VERSION 5.8 ;
BUSBITCHARS "[]" ;
DIVIDERCHAR "/" ;
UNITS
    DATABASE MICRONS 1000 ;
END UNITS

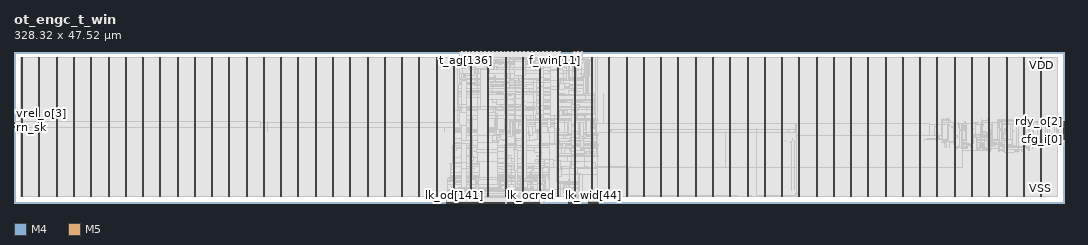
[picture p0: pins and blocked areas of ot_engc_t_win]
MACRO ot_engc_t_win
  FOREIGN ot_engc_t_win 0 0 ;
  CLASS BLOCK ;
  SIZE 328.32 BY 47.52 ;
  PIN cfg_i[0]
    DIRECTION INPUT ;
    USE SIGNAL ;
    PORT
      LAYER M4 ;
        RECT  328.236 19.92 328.32 19.944 ;
    END
  END cfg_i[0]
  PIN cfg_i[1]
    DIRECTION INPUT ;
    USE SIGNAL ;
    PORT
      LAYER M4 ;
        RECT  328.236 20.016 328.32 20.04 ;
    END
  END cfg_i[1]
  PIN cfg_i[2]
    DIRECTION INPUT ;
    USE SIGNAL ;
    PORT
      LAYER M4 ;
        RECT  328.236 20.112 328.32 20.136 ;
    END
  END cfg_i[2]
  PIN cfg_o[0]
    DIRECTION OUTPUT ;
    USE SIGNAL ;
    PORT
      LAYER M5 ;
        RECT  160.464 0 160.488 0.084 ;
    END
  END cfg_o[0]
  PIN cfg_o[1]
    DIRECTION OUTPUT ;
    USE SIGNAL ;
    PORT
      LAYER M5 ;
        RECT  160.56 0 160.584 0.084 ;
    END
  END cfg_o[1]
  PIN cfg_o[2]
    DIRECTION OUTPUT ;
    USE SIGNAL ;
    PORT
      LAYER M5 ;
        RECT  160.656 0 160.68 0.084 ;
    END
  END cfg_o[2]
  PIN ck
    DIRECTION INPUT ;
    USE SIGNAL ;
    PORT
      LAYER M5 ;
        RECT  167.856 47.436 167.88 47.52 ;
    END
  END ck
  PIN f_agc
    DIRECTION INPUT ;
    USE SIGNAL ;
    PORT
      LAYER M5 ;
        RECT  167.952 47.436 167.976 47.52 ;
    END
  END f_agc
  PIN f_win[0]
    DIRECTION INPUT ;
    USE SIGNAL ;
    PORT
      LAYER M5 ;
        RECT  168.048 47.436 168.072 47.52 ;
    END
  END f_win[0]
  PIN f_win[10]
    DIRECTION INPUT ;
    USE SIGNAL ;
    PORT
      LAYER M5 ;
        RECT  169.008 47.436 169.032 47.52 ;
    END
  END f_win[10]
  PIN f_win[11]
    DIRECTION INPUT ;
    USE SIGNAL ;
    PORT
      LAYER M5 ;
        RECT  169.104 47.436 169.128 47.52 ;
    END
  END f_win[11]
  PIN f_win[12]
    DIRECTION INPUT ;
    USE SIGNAL ;
    PORT
      LAYER M5 ;
        RECT  169.2 47.436 169.224 47.52 ;
    END
  END f_win[12]
  PIN f_win[13]
    DIRECTION INPUT ;
    USE SIGNAL ;
    PORT
      LAYER M5 ;
        RECT  169.296 47.436 169.32 47.52 ;
    END
  END f_win[13]
  PIN f_win[14]
    DIRECTION INPUT ;
    USE SIGNAL ;
    PORT
      LAYER M5 ;
        RECT  169.392 47.436 169.416 47.52 ;
    END
  END f_win[14]
  PIN f_win[15]
    DIRECTION INPUT ;
    USE SIGNAL ;
    PORT
      LAYER M5 ;
        RECT  169.488 47.436 169.512 47.52 ;
    END
  END f_win[15]
  PIN f_win[16]
    DIRECTION INPUT ;
    USE SIGNAL ;
    PORT
      LAYER M5 ;
        RECT  169.584 47.436 169.608 47.52 ;
    END
  END f_win[16]
  PIN f_win[17]
    DIRECTION INPUT ;
    USE SIGNAL ;
    PORT
      LAYER M5 ;
        RECT  169.68 47.436 169.704 47.52 ;
    END
  END f_win[17]
  PIN f_win[18]
    DIRECTION INPUT ;
    USE SIGNAL ;
    PORT
      LAYER M5 ;
        RECT  169.776 47.436 169.8 47.52 ;
    END
  END f_win[18]
  PIN f_win[19]
    DIRECTION INPUT ;
    USE SIGNAL ;
    PORT
      LAYER M5 ;
        RECT  169.872 47.436 169.896 47.52 ;
    END
  END f_win[19]
  PIN f_win[1]
    DIRECTION INPUT ;
    USE SIGNAL ;
    PORT
      LAYER M5 ;
        RECT  168.144 47.436 168.168 47.52 ;
    END
  END f_win[1]
  PIN f_win[20]
    DIRECTION INPUT ;
    USE SIGNAL ;
    PORT
      LAYER M5 ;
        RECT  169.968 47.436 169.992 47.52 ;
    END
  END f_win[20]
  PIN f_win[21]
    DIRECTION INPUT ;
    USE SIGNAL ;
    PORT
      LAYER M5 ;
        RECT  170.064 47.436 170.088 47.52 ;
    END
  END f_win[21]
  PIN f_win[22]
    DIRECTION INPUT ;
    USE SIGNAL ;
    PORT
      LAYER M5 ;
        RECT  170.16 47.436 170.184 47.52 ;
    END
  END f_win[22]
  PIN f_win[23]
    DIRECTION INPUT ;
    USE SIGNAL ;
    PORT
      LAYER M5 ;
        RECT  170.256 47.436 170.28 47.52 ;
    END
  END f_win[23]
  PIN f_win[24]
    DIRECTION INPUT ;
    USE SIGNAL ;
    PORT
      LAYER M5 ;
        RECT  170.352 47.436 170.376 47.52 ;
    END
  END f_win[24]
  PIN f_win[25]
    DIRECTION INPUT ;
    USE SIGNAL ;
    PORT
      LAYER M5 ;
        RECT  170.448 47.436 170.472 47.52 ;
    END
  END f_win[25]
  PIN f_win[26]
    DIRECTION INPUT ;
    USE SIGNAL ;
    PORT
      LAYER M5 ;
        RECT  170.544 47.436 170.568 47.52 ;
    END
  END f_win[26]
  PIN f_win[27]
    DIRECTION INPUT ;
    USE SIGNAL ;
    PORT
      LAYER M5 ;
        RECT  170.64 47.436 170.664 47.52 ;
    END
  END f_win[27]
  PIN f_win[28]
    DIRECTION INPUT ;
    USE SIGNAL ;
    PORT
      LAYER M5 ;
        RECT  170.736 47.436 170.76 47.52 ;
    END
  END f_win[28]
  PIN f_win[29]
    DIRECTION INPUT ;
    USE SIGNAL ;
    PORT
      LAYER M5 ;
        RECT  170.832 47.436 170.856 47.52 ;
    END
  END f_win[29]
  PIN f_win[2]
    DIRECTION INPUT ;
    USE SIGNAL ;
    PORT
      LAYER M5 ;
        RECT  168.24 47.436 168.264 47.52 ;
    END
  END f_win[2]
  PIN f_win[30]
    DIRECTION INPUT ;
    USE SIGNAL ;
    PORT
      LAYER M5 ;
        RECT  174.768 47.436 174.792 47.52 ;
    END
  END f_win[30]
  PIN f_win[31]
    DIRECTION INPUT ;
    USE SIGNAL ;
    PORT
      LAYER M5 ;
        RECT  174.864 47.436 174.888 47.52 ;
    END
  END f_win[31]
  PIN f_win[32]
    DIRECTION INPUT ;
    USE SIGNAL ;
    PORT
      LAYER M5 ;
        RECT  174.96 47.436 174.984 47.52 ;
    END
  END f_win[32]
  PIN f_win[33]
    DIRECTION INPUT ;
    USE SIGNAL ;
    PORT
      LAYER M5 ;
        RECT  175.056 47.436 175.08 47.52 ;
    END
  END f_win[33]
  PIN f_win[34]
    DIRECTION INPUT ;
    USE SIGNAL ;
    PORT
      LAYER M5 ;
        RECT  175.152 47.436 175.176 47.52 ;
    END
  END f_win[34]
  PIN f_win[35]
    DIRECTION INPUT ;
    USE SIGNAL ;
    PORT
      LAYER M5 ;
        RECT  175.248 47.436 175.272 47.52 ;
    END
  END f_win[35]
  PIN f_win[36]
    DIRECTION INPUT ;
    USE SIGNAL ;
    PORT
      LAYER M5 ;
        RECT  175.344 47.436 175.368 47.52 ;
    END
  END f_win[36]
  PIN f_win[37]
    DIRECTION INPUT ;
    USE SIGNAL ;
    PORT
      LAYER M5 ;
        RECT  175.44 47.436 175.464 47.52 ;
    END
  END f_win[37]
  PIN f_win[38]
    DIRECTION INPUT ;
    USE SIGNAL ;
    PORT
      LAYER M5 ;
        RECT  175.536 47.436 175.56 47.52 ;
    END
  END f_win[38]
  PIN f_win[39]
    DIRECTION INPUT ;
    USE SIGNAL ;
    PORT
      LAYER M5 ;
        RECT  175.632 47.436 175.656 47.52 ;
    END
  END f_win[39]
  PIN f_win[3]
    DIRECTION INPUT ;
    USE SIGNAL ;
    PORT
      LAYER M5 ;
        RECT  168.336 47.436 168.36 47.52 ;
    END
  END f_win[3]
  PIN f_win[40]
    DIRECTION INPUT ;
    USE SIGNAL ;
    PORT
      LAYER M5 ;
        RECT  175.728 47.436 175.752 47.52 ;
    END
  END f_win[40]
  PIN f_win[41]
    DIRECTION INPUT ;
    USE SIGNAL ;
    PORT
      LAYER M5 ;
        RECT  175.824 47.436 175.848 47.52 ;
    END
  END f_win[41]
  PIN f_win[42]
    DIRECTION INPUT ;
    USE SIGNAL ;
    PORT
      LAYER M5 ;
        RECT  175.92 47.436 175.944 47.52 ;
    END
  END f_win[42]
  PIN f_win[43]
    DIRECTION INPUT ;
    USE SIGNAL ;
    PORT
      LAYER M5 ;
        RECT  176.016 47.436 176.04 47.52 ;
    END
  END f_win[43]
  PIN f_win[44]
    DIRECTION INPUT ;
    USE SIGNAL ;
    PORT
      LAYER M5 ;
        RECT  176.112 47.436 176.136 47.52 ;
    END
  END f_win[44]
  PIN f_win[45]
    DIRECTION INPUT ;
    USE SIGNAL ;
    PORT
      LAYER M5 ;
        RECT  176.208 47.436 176.232 47.52 ;
    END
  END f_win[45]
  PIN f_win[46]
    DIRECTION INPUT ;
    USE SIGNAL ;
    PORT
      LAYER M5 ;
        RECT  176.304 47.436 176.328 47.52 ;
    END
  END f_win[46]
  PIN f_win[47]
    DIRECTION INPUT ;
    USE SIGNAL ;
    PORT
      LAYER M5 ;
        RECT  176.4 47.436 176.424 47.52 ;
    END
  END f_win[47]
  PIN f_win[48]
    DIRECTION INPUT ;
    USE SIGNAL ;
    PORT
      LAYER M5 ;
        RECT  176.496 47.436 176.52 47.52 ;
    END
  END f_win[48]
  PIN f_win[49]
    DIRECTION INPUT ;
    USE SIGNAL ;
    PORT
      LAYER M5 ;
        RECT  176.592 47.436 176.616 47.52 ;
    END
  END f_win[49]
  PIN f_win[4]
    DIRECTION INPUT ;
    USE SIGNAL ;
    PORT
      LAYER M5 ;
        RECT  168.432 47.436 168.456 47.52 ;
    END
  END f_win[4]
  PIN f_win[50]
    DIRECTION INPUT ;
    USE SIGNAL ;
    PORT
      LAYER M5 ;
        RECT  176.688 47.436 176.712 47.52 ;
    END
  END f_win[50]
  PIN f_win[51]
    DIRECTION INPUT ;
    USE SIGNAL ;
    PORT
      LAYER M5 ;
        RECT  176.784 47.436 176.808 47.52 ;
    END
  END f_win[51]
  PIN f_win[52]
    DIRECTION INPUT ;
    USE SIGNAL ;
    PORT
      LAYER M5 ;
        RECT  176.88 47.436 176.904 47.52 ;
    END
  END f_win[52]
  PIN f_win[53]
    DIRECTION INPUT ;
    USE SIGNAL ;
    PORT
      LAYER M5 ;
        RECT  176.976 47.436 177 47.52 ;
    END
  END f_win[53]
  PIN f_win[54]
    DIRECTION INPUT ;
    USE SIGNAL ;
    PORT
      LAYER M5 ;
        RECT  177.072 47.436 177.096 47.52 ;
    END
  END f_win[54]
  PIN f_win[55]
    DIRECTION INPUT ;
    USE SIGNAL ;
    PORT
      LAYER M5 ;
        RECT  177.168 47.436 177.192 47.52 ;
    END
  END f_win[55]
  PIN f_win[56]
    DIRECTION INPUT ;
    USE SIGNAL ;
    PORT
      LAYER M5 ;
        RECT  177.264 47.436 177.288 47.52 ;
    END
  END f_win[56]
  PIN f_win[57]
    DIRECTION INPUT ;
    USE SIGNAL ;
    PORT
      LAYER M5 ;
        RECT  177.36 47.436 177.384 47.52 ;
    END
  END f_win[57]
  PIN f_win[58]
    DIRECTION INPUT ;
    USE SIGNAL ;
    PORT
      LAYER M5 ;
        RECT  177.456 47.436 177.48 47.52 ;
    END
  END f_win[58]
  PIN f_win[59]
    DIRECTION INPUT ;
    USE SIGNAL ;
    PORT
      LAYER M5 ;
        RECT  177.552 47.436 177.576 47.52 ;
    END
  END f_win[59]
  PIN f_win[5]
    DIRECTION INPUT ;
    USE SIGNAL ;
    PORT
      LAYER M5 ;
        RECT  168.528 47.436 168.552 47.52 ;
    END
  END f_win[5]
  PIN f_win[60]
    DIRECTION INPUT ;
    USE SIGNAL ;
    PORT
      LAYER M5 ;
        RECT  177.648 47.436 177.672 47.52 ;
    END
  END f_win[60]
  PIN f_win[61]
    DIRECTION INPUT ;
    USE SIGNAL ;
    PORT
      LAYER M5 ;
        RECT  177.744 47.436 177.768 47.52 ;
    END
  END f_win[61]
  PIN f_win[62]
    DIRECTION INPUT ;
    USE SIGNAL ;
    PORT
      LAYER M5 ;
        RECT  164.784 47.436 164.808 47.52 ;
    END
  END f_win[62]
  PIN f_win[63]
    DIRECTION INPUT ;
    USE SIGNAL ;
    PORT
      LAYER M5 ;
        RECT  164.88 47.436 164.904 47.52 ;
    END
  END f_win[63]
  PIN f_win[64]
    DIRECTION INPUT ;
    USE SIGNAL ;
    PORT
      LAYER M5 ;
        RECT  164.976 47.436 165 47.52 ;
    END
  END f_win[64]
  PIN f_win[65]
    DIRECTION INPUT ;
    USE SIGNAL ;
    PORT
      LAYER M5 ;
        RECT  165.072 47.436 165.096 47.52 ;
    END
  END f_win[65]
  PIN f_win[66]
    DIRECTION INPUT ;
    USE SIGNAL ;
    PORT
      LAYER M5 ;
        RECT  165.168 47.436 165.192 47.52 ;
    END
  END f_win[66]
  PIN f_win[67]
    DIRECTION INPUT ;
    USE SIGNAL ;
    PORT
      LAYER M5 ;
        RECT  165.264 47.436 165.288 47.52 ;
    END
  END f_win[67]
  PIN f_win[68]
    DIRECTION INPUT ;
    USE SIGNAL ;
    PORT
      LAYER M5 ;
        RECT  165.36 47.436 165.384 47.52 ;
    END
  END f_win[68]
  PIN f_win[69]
    DIRECTION INPUT ;
    USE SIGNAL ;
    PORT
      LAYER M5 ;
        RECT  165.456 47.436 165.48 47.52 ;
    END
  END f_win[69]
  PIN f_win[6]
    DIRECTION INPUT ;
    USE SIGNAL ;
    PORT
      LAYER M5 ;
        RECT  168.624 47.436 168.648 47.52 ;
    END
  END f_win[6]
  PIN f_win[70]
    DIRECTION INPUT ;
    USE SIGNAL ;
    PORT
      LAYER M5 ;
        RECT  165.552 47.436 165.576 47.52 ;
    END
  END f_win[70]
  PIN f_win[71]
    DIRECTION INPUT ;
    USE SIGNAL ;
    PORT
      LAYER M5 ;
        RECT  165.648 47.436 165.672 47.52 ;
    END
  END f_win[71]
  PIN f_win[72]
    DIRECTION INPUT ;
    USE SIGNAL ;
    PORT
      LAYER M5 ;
        RECT  165.744 47.436 165.768 47.52 ;
    END
  END f_win[72]
  PIN f_win[7]
    DIRECTION INPUT ;
    USE SIGNAL ;
    PORT
      LAYER M5 ;
        RECT  168.72 47.436 168.744 47.52 ;
    END
  END f_win[7]
  PIN f_win[8]
    DIRECTION INPUT ;
    USE SIGNAL ;
    PORT
      LAYER M5 ;
        RECT  168.816 47.436 168.84 47.52 ;
    END
  END f_win[8]
  PIN f_win[9]
    DIRECTION INPUT ;
    USE SIGNAL ;
    PORT
      LAYER M5 ;
        RECT  168.912 47.436 168.936 47.52 ;
    END
  END f_win[9]
  PIN jf_o
    DIRECTION OUTPUT ;
    USE SIGNAL ;
    PORT
      LAYER M4 ;
        RECT  328.236 20.208 328.32 20.232 ;
    END
  END jf_o
  PIN jn_i[0]
    DIRECTION INPUT ;
    USE SIGNAL ;
    PORT
      LAYER M4 ;
        RECT  328.236 20.304 328.32 20.328 ;
    END
  END jn_i[0]
  PIN jn_i[10]
    DIRECTION INPUT ;
    USE SIGNAL ;
    PORT
      LAYER M4 ;
        RECT  328.236 21.264 328.32 21.288 ;
    END
  END jn_i[10]
  PIN jn_i[11]
    DIRECTION INPUT ;
    USE SIGNAL ;
    PORT
      LAYER M4 ;
        RECT  328.236 21.36 328.32 21.384 ;
    END
  END jn_i[11]
  PIN jn_i[12]
    DIRECTION INPUT ;
    USE SIGNAL ;
    PORT
      LAYER M4 ;
        RECT  328.236 21.456 328.32 21.48 ;
    END
  END jn_i[12]
  PIN jn_i[13]
    DIRECTION INPUT ;
    USE SIGNAL ;
    PORT
      LAYER M4 ;
        RECT  328.236 21.552 328.32 21.576 ;
    END
  END jn_i[13]
  PIN jn_i[14]
    DIRECTION INPUT ;
    USE SIGNAL ;
    PORT
      LAYER M4 ;
        RECT  328.236 21.648 328.32 21.672 ;
    END
  END jn_i[14]
  PIN jn_i[15]
    DIRECTION INPUT ;
    USE SIGNAL ;
    PORT
      LAYER M4 ;
        RECT  328.236 21.744 328.32 21.768 ;
    END
  END jn_i[15]
  PIN jn_i[16]
    DIRECTION INPUT ;
    USE SIGNAL ;
    PORT
      LAYER M4 ;
        RECT  328.236 21.84 328.32 21.864 ;
    END
  END jn_i[16]
  PIN jn_i[17]
    DIRECTION INPUT ;
    USE SIGNAL ;
    PORT
      LAYER M4 ;
        RECT  328.236 21.936 328.32 21.96 ;
    END
  END jn_i[17]
  PIN jn_i[1]
    DIRECTION INPUT ;
    USE SIGNAL ;
    PORT
      LAYER M4 ;
        RECT  328.236 20.4 328.32 20.424 ;
    END
  END jn_i[1]
  PIN jn_i[2]
    DIRECTION INPUT ;
    USE SIGNAL ;
    PORT
      LAYER M4 ;
        RECT  328.236 20.496 328.32 20.52 ;
    END
  END jn_i[2]
  PIN jn_i[3]
    DIRECTION INPUT ;
    USE SIGNAL ;
    PORT
      LAYER M4 ;
        RECT  328.236 20.592 328.32 20.616 ;
    END
  END jn_i[3]
  PIN jn_i[4]
    DIRECTION INPUT ;
    USE SIGNAL ;
    PORT
      LAYER M4 ;
        RECT  328.236 20.688 328.32 20.712 ;
    END
  END jn_i[4]
  PIN jn_i[5]
    DIRECTION INPUT ;
    USE SIGNAL ;
    PORT
      LAYER M4 ;
        RECT  328.236 20.784 328.32 20.808 ;
    END
  END jn_i[5]
  PIN jn_i[6]
    DIRECTION INPUT ;
    USE SIGNAL ;
    PORT
      LAYER M4 ;
        RECT  328.236 20.88 328.32 20.904 ;
    END
  END jn_i[6]
  PIN jn_i[7]
    DIRECTION INPUT ;
    USE SIGNAL ;
    PORT
      LAYER M4 ;
        RECT  328.236 20.976 328.32 21 ;
    END
  END jn_i[7]
  PIN jn_i[8]
    DIRECTION INPUT ;
    USE SIGNAL ;
    PORT
      LAYER M4 ;
        RECT  328.236 21.072 328.32 21.096 ;
    END
  END jn_i[8]
  PIN jn_i[9]
    DIRECTION INPUT ;
    USE SIGNAL ;
    PORT
      LAYER M4 ;
        RECT  328.236 21.168 328.32 21.192 ;
    END
  END jn_i[9]
  PIN lk_fault
    DIRECTION INPUT ;
    USE SIGNAL ;
    PORT
      LAYER M5 ;
        RECT  160.752 0 160.776 0.084 ;
    END
  END lk_fault
  PIN lk_ob[0]
    DIRECTION INPUT ;
    USE SIGNAL ;
    PORT
      LAYER M5 ;
        RECT  160.848 0 160.872 0.084 ;
    END
  END lk_ob[0]
  PIN lk_ob[1]
    DIRECTION INPUT ;
    USE SIGNAL ;
    PORT
      LAYER M5 ;
        RECT  160.944 0 160.968 0.084 ;
    END
  END lk_ob[1]
  PIN lk_ob[2]
    DIRECTION INPUT ;
    USE SIGNAL ;
    PORT
      LAYER M5 ;
        RECT  161.04 0 161.064 0.084 ;
    END
  END lk_ob[2]
  PIN lk_oc[0]
    DIRECTION INPUT ;
    USE SIGNAL ;
    PORT
      LAYER M5 ;
        RECT  161.136 0 161.16 0.084 ;
    END
  END lk_oc[0]
  PIN lk_oc[1]
    DIRECTION INPUT ;
    USE SIGNAL ;
    PORT
      LAYER M5 ;
        RECT  161.232 0 161.256 0.084 ;
    END
  END lk_oc[1]
  PIN lk_oc[2]
    DIRECTION INPUT ;
    USE SIGNAL ;
    PORT
      LAYER M5 ;
        RECT  161.328 0 161.352 0.084 ;
    END
  END lk_oc[2]
  PIN lk_oc[3]
    DIRECTION INPUT ;
    USE SIGNAL ;
    PORT
      LAYER M5 ;
        RECT  161.424 0 161.448 0.084 ;
    END
  END lk_oc[3]
  PIN lk_oc[4]
    DIRECTION INPUT ;
    USE SIGNAL ;
    PORT
      LAYER M5 ;
        RECT  161.52 0 161.544 0.084 ;
    END
  END lk_oc[4]
  PIN lk_ocred
    DIRECTION OUTPUT ;
    USE SIGNAL ;
    PORT
      LAYER M5 ;
        RECT  161.616 0 161.64 0.084 ;
    END
  END lk_ocred
  PIN lk_od[0]
    DIRECTION INPUT ;
    USE SIGNAL ;
    PORT
      LAYER M5 ;
        RECT  161.712 0 161.736 0.084 ;
    END
  END lk_od[0]
  PIN lk_od[100]
    DIRECTION INPUT ;
    USE SIGNAL ;
    PORT
      LAYER M5 ;
        RECT  139.824 0 139.848 0.084 ;
    END
  END lk_od[100]
  PIN lk_od[101]
    DIRECTION INPUT ;
    USE SIGNAL ;
    PORT
      LAYER M5 ;
        RECT  139.92 0 139.944 0.084 ;
    END
  END lk_od[101]
  PIN lk_od[102]
    DIRECTION INPUT ;
    USE SIGNAL ;
    PORT
      LAYER M5 ;
        RECT  140.016 0 140.04 0.084 ;
    END
  END lk_od[102]
  PIN lk_od[103]
    DIRECTION INPUT ;
    USE SIGNAL ;
    PORT
      LAYER M5 ;
        RECT  140.112 0 140.136 0.084 ;
    END
  END lk_od[103]
  PIN lk_od[104]
    DIRECTION INPUT ;
    USE SIGNAL ;
    PORT
      LAYER M5 ;
        RECT  140.208 0 140.232 0.084 ;
    END
  END lk_od[104]
  PIN lk_od[105]
    DIRECTION INPUT ;
    USE SIGNAL ;
    PORT
      LAYER M5 ;
        RECT  140.304 0 140.328 0.084 ;
    END
  END lk_od[105]
  PIN lk_od[106]
    DIRECTION INPUT ;
    USE SIGNAL ;
    PORT
      LAYER M5 ;
        RECT  140.4 0 140.424 0.084 ;
    END
  END lk_od[106]
  PIN lk_od[107]
    DIRECTION INPUT ;
    USE SIGNAL ;
    PORT
      LAYER M5 ;
        RECT  140.496 0 140.52 0.084 ;
    END
  END lk_od[107]
  PIN lk_od[108]
    DIRECTION INPUT ;
    USE SIGNAL ;
    PORT
      LAYER M5 ;
        RECT  140.592 0 140.616 0.084 ;
    END
  END lk_od[108]
  PIN lk_od[109]
    DIRECTION INPUT ;
    USE SIGNAL ;
    PORT
      LAYER M5 ;
        RECT  140.688 0 140.712 0.084 ;
    END
  END lk_od[109]
  PIN lk_od[10]
    DIRECTION INPUT ;
    USE SIGNAL ;
    PORT
      LAYER M5 ;
        RECT  162.672 0 162.696 0.084 ;
    END
  END lk_od[10]
  PIN lk_od[110]
    DIRECTION INPUT ;
    USE SIGNAL ;
    PORT
      LAYER M5 ;
        RECT  140.784 0 140.808 0.084 ;
    END
  END lk_od[110]
  PIN lk_od[111]
    DIRECTION INPUT ;
    USE SIGNAL ;
    PORT
      LAYER M5 ;
        RECT  140.88 0 140.904 0.084 ;
    END
  END lk_od[111]
  PIN lk_od[112]
    DIRECTION INPUT ;
    USE SIGNAL ;
    PORT
      LAYER M5 ;
        RECT  140.976 0 141 0.084 ;
    END
  END lk_od[112]
  PIN lk_od[113]
    DIRECTION INPUT ;
    USE SIGNAL ;
    PORT
      LAYER M5 ;
        RECT  141.072 0 141.096 0.084 ;
    END
  END lk_od[113]
  PIN lk_od[114]
    DIRECTION INPUT ;
    USE SIGNAL ;
    PORT
      LAYER M5 ;
        RECT  141.168 0 141.192 0.084 ;
    END
  END lk_od[114]
  PIN lk_od[115]
    DIRECTION INPUT ;
    USE SIGNAL ;
    PORT
      LAYER M5 ;
        RECT  135.12 0 135.144 0.084 ;
    END
  END lk_od[115]
  PIN lk_od[116]
    DIRECTION INPUT ;
    USE SIGNAL ;
    PORT
      LAYER M5 ;
        RECT  135.216 0 135.24 0.084 ;
    END
  END lk_od[116]
  PIN lk_od[117]
    DIRECTION INPUT ;
    USE SIGNAL ;
    PORT
      LAYER M5 ;
        RECT  135.312 0 135.336 0.084 ;
    END
  END lk_od[117]
  PIN lk_od[118]
    DIRECTION INPUT ;
    USE SIGNAL ;
    PORT
      LAYER M5 ;
        RECT  135.408 0 135.432 0.084 ;
    END
  END lk_od[118]
  PIN lk_od[119]
    DIRECTION INPUT ;
    USE SIGNAL ;
    PORT
      LAYER M5 ;
        RECT  135.504 0 135.528 0.084 ;
    END
  END lk_od[119]
  PIN lk_od[11]
    DIRECTION INPUT ;
    USE SIGNAL ;
    PORT
      LAYER M5 ;
        RECT  162.768 0 162.792 0.084 ;
    END
  END lk_od[11]
  PIN lk_od[120]
    DIRECTION INPUT ;
    USE SIGNAL ;
    PORT
      LAYER M5 ;
        RECT  135.6 0 135.624 0.084 ;
    END
  END lk_od[120]
  PIN lk_od[121]
    DIRECTION INPUT ;
    USE SIGNAL ;
    PORT
      LAYER M5 ;
        RECT  135.696 0 135.72 0.084 ;
    END
  END lk_od[121]
  PIN lk_od[122]
    DIRECTION INPUT ;
    USE SIGNAL ;
    PORT
      LAYER M5 ;
        RECT  135.792 0 135.816 0.084 ;
    END
  END lk_od[122]
  PIN lk_od[123]
    DIRECTION INPUT ;
    USE SIGNAL ;
    PORT
      LAYER M5 ;
        RECT  135.888 0 135.912 0.084 ;
    END
  END lk_od[123]
  PIN lk_od[124]
    DIRECTION INPUT ;
    USE SIGNAL ;
    PORT
      LAYER M5 ;
        RECT  135.984 0 136.008 0.084 ;
    END
  END lk_od[124]
  PIN lk_od[125]
    DIRECTION INPUT ;
    USE SIGNAL ;
    PORT
      LAYER M5 ;
        RECT  136.08 0 136.104 0.084 ;
    END
  END lk_od[125]
  PIN lk_od[126]
    DIRECTION INPUT ;
    USE SIGNAL ;
    PORT
      LAYER M5 ;
        RECT  136.176 0 136.2 0.084 ;
    END
  END lk_od[126]
  PIN lk_od[127]
    DIRECTION INPUT ;
    USE SIGNAL ;
    PORT
      LAYER M5 ;
        RECT  136.272 0 136.296 0.084 ;
    END
  END lk_od[127]
  PIN lk_od[128]
    DIRECTION INPUT ;
    USE SIGNAL ;
    PORT
      LAYER M5 ;
        RECT  136.368 0 136.392 0.084 ;
    END
  END lk_od[128]
  PIN lk_od[129]
    DIRECTION INPUT ;
    USE SIGNAL ;
    PORT
      LAYER M5 ;
        RECT  136.464 0 136.488 0.084 ;
    END
  END lk_od[129]
  PIN lk_od[12]
    DIRECTION INPUT ;
    USE SIGNAL ;
    PORT
      LAYER M5 ;
        RECT  162.864 0 162.888 0.084 ;
    END
  END lk_od[12]
  PIN lk_od[130]
    DIRECTION INPUT ;
    USE SIGNAL ;
    PORT
      LAYER M5 ;
        RECT  136.56 0 136.584 0.084 ;
    END
  END lk_od[130]
  PIN lk_od[131]
    DIRECTION INPUT ;
    USE SIGNAL ;
    PORT
      LAYER M5 ;
        RECT  136.656 0 136.68 0.084 ;
    END
  END lk_od[131]
  PIN lk_od[132]
    DIRECTION INPUT ;
    USE SIGNAL ;
    PORT
      LAYER M5 ;
        RECT  136.752 0 136.776 0.084 ;
    END
  END lk_od[132]
  PIN lk_od[133]
    DIRECTION INPUT ;
    USE SIGNAL ;
    PORT
      LAYER M5 ;
        RECT  136.848 0 136.872 0.084 ;
    END
  END lk_od[133]
  PIN lk_od[134]
    DIRECTION INPUT ;
    USE SIGNAL ;
    PORT
      LAYER M5 ;
        RECT  136.944 0 136.968 0.084 ;
    END
  END lk_od[134]
  PIN lk_od[135]
    DIRECTION INPUT ;
    USE SIGNAL ;
    PORT
      LAYER M5 ;
        RECT  137.04 0 137.064 0.084 ;
    END
  END lk_od[135]
  PIN lk_od[136]
    DIRECTION INPUT ;
    USE SIGNAL ;
    PORT
      LAYER M5 ;
        RECT  137.136 0 137.16 0.084 ;
    END
  END lk_od[136]
  PIN lk_od[137]
    DIRECTION INPUT ;
    USE SIGNAL ;
    PORT
      LAYER M5 ;
        RECT  137.232 0 137.256 0.084 ;
    END
  END lk_od[137]
  PIN lk_od[138]
    DIRECTION INPUT ;
    USE SIGNAL ;
    PORT
      LAYER M5 ;
        RECT  137.328 0 137.352 0.084 ;
    END
  END lk_od[138]
  PIN lk_od[139]
    DIRECTION INPUT ;
    USE SIGNAL ;
    PORT
      LAYER M5 ;
        RECT  137.424 0 137.448 0.084 ;
    END
  END lk_od[139]
  PIN lk_od[13]
    DIRECTION INPUT ;
    USE SIGNAL ;
    PORT
      LAYER M5 ;
        RECT  162.96 0 162.984 0.084 ;
    END
  END lk_od[13]
  PIN lk_od[140]
    DIRECTION INPUT ;
    USE SIGNAL ;
    PORT
      LAYER M5 ;
        RECT  137.52 0 137.544 0.084 ;
    END
  END lk_od[140]
  PIN lk_od[141]
    DIRECTION INPUT ;
    USE SIGNAL ;
    PORT
      LAYER M5 ;
        RECT  137.616 0 137.64 0.084 ;
    END
  END lk_od[141]
  PIN lk_od[142]
    DIRECTION INPUT ;
    USE SIGNAL ;
    PORT
      LAYER M5 ;
        RECT  137.712 0 137.736 0.084 ;
    END
  END lk_od[142]
  PIN lk_od[143]
    DIRECTION INPUT ;
    USE SIGNAL ;
    PORT
      LAYER M5 ;
        RECT  137.808 0 137.832 0.084 ;
    END
  END lk_od[143]
  PIN lk_od[144]
    DIRECTION INPUT ;
    USE SIGNAL ;
    PORT
      LAYER M5 ;
        RECT  137.904 0 137.928 0.084 ;
    END
  END lk_od[144]
  PIN lk_od[145]
    DIRECTION INPUT ;
    USE SIGNAL ;
    PORT
      LAYER M5 ;
        RECT  138 0 138.024 0.084 ;
    END
  END lk_od[145]
  PIN lk_od[146]
    DIRECTION INPUT ;
    USE SIGNAL ;
    PORT
      LAYER M5 ;
        RECT  138.096 0 138.12 0.084 ;
    END
  END lk_od[146]
  PIN lk_od[147]
    DIRECTION INPUT ;
    USE SIGNAL ;
    PORT
      LAYER M5 ;
        RECT  144.336 0 144.36 0.084 ;
    END
  END lk_od[147]
  PIN lk_od[148]
    DIRECTION INPUT ;
    USE SIGNAL ;
    PORT
      LAYER M5 ;
        RECT  144.432 0 144.456 0.084 ;
    END
  END lk_od[148]
  PIN lk_od[149]
    DIRECTION INPUT ;
    USE SIGNAL ;
    PORT
      LAYER M5 ;
        RECT  144.528 0 144.552 0.084 ;
    END
  END lk_od[149]
  PIN lk_od[14]
    DIRECTION INPUT ;
    USE SIGNAL ;
    PORT
      LAYER M5 ;
        RECT  163.056 0 163.08 0.084 ;
    END
  END lk_od[14]
  PIN lk_od[150]
    DIRECTION INPUT ;
    USE SIGNAL ;
    PORT
      LAYER M5 ;
        RECT  144.624 0 144.648 0.084 ;
    END
  END lk_od[150]
  PIN lk_od[151]
    DIRECTION INPUT ;
    USE SIGNAL ;
    PORT
      LAYER M5 ;
        RECT  144.72 0 144.744 0.084 ;
    END
  END lk_od[151]
  PIN lk_od[152]
    DIRECTION INPUT ;
    USE SIGNAL ;
    PORT
      LAYER M5 ;
        RECT  144.816 0 144.84 0.084 ;
    END
  END lk_od[152]
  PIN lk_od[153]
    DIRECTION INPUT ;
    USE SIGNAL ;
    PORT
      LAYER M5 ;
        RECT  144.912 0 144.936 0.084 ;
    END
  END lk_od[153]
  PIN lk_od[154]
    DIRECTION INPUT ;
    USE SIGNAL ;
    PORT
      LAYER M5 ;
        RECT  145.008 0 145.032 0.084 ;
    END
  END lk_od[154]
  PIN lk_od[155]
    DIRECTION INPUT ;
    USE SIGNAL ;
    PORT
      LAYER M5 ;
        RECT  145.104 0 145.128 0.084 ;
    END
  END lk_od[155]
  PIN lk_od[156]
    DIRECTION INPUT ;
    USE SIGNAL ;
    PORT
      LAYER M5 ;
        RECT  145.2 0 145.224 0.084 ;
    END
  END lk_od[156]
  PIN lk_od[157]
    DIRECTION INPUT ;
    USE SIGNAL ;
    PORT
      LAYER M5 ;
        RECT  145.296 0 145.32 0.084 ;
    END
  END lk_od[157]
  PIN lk_od[158]
    DIRECTION INPUT ;
    USE SIGNAL ;
    PORT
      LAYER M5 ;
        RECT  145.392 0 145.416 0.084 ;
    END
  END lk_od[158]
  PIN lk_od[159]
    DIRECTION INPUT ;
    USE SIGNAL ;
    PORT
      LAYER M5 ;
        RECT  145.488 0 145.512 0.084 ;
    END
  END lk_od[159]
  PIN lk_od[15]
    DIRECTION INPUT ;
    USE SIGNAL ;
    PORT
      LAYER M5 ;
        RECT  163.152 0 163.176 0.084 ;
    END
  END lk_od[15]
  PIN lk_od[160]
    DIRECTION INPUT ;
    USE SIGNAL ;
    PORT
      LAYER M5 ;
        RECT  145.584 0 145.608 0.084 ;
    END
  END lk_od[160]
  PIN lk_od[161]
    DIRECTION INPUT ;
    USE SIGNAL ;
    PORT
      LAYER M5 ;
        RECT  145.68 0 145.704 0.084 ;
    END
  END lk_od[161]
  PIN lk_od[162]
    DIRECTION INPUT ;
    USE SIGNAL ;
    PORT
      LAYER M5 ;
        RECT  145.776 0 145.8 0.084 ;
    END
  END lk_od[162]
  PIN lk_od[163]
    DIRECTION INPUT ;
    USE SIGNAL ;
    PORT
      LAYER M5 ;
        RECT  145.872 0 145.896 0.084 ;
    END
  END lk_od[163]
  PIN lk_od[164]
    DIRECTION INPUT ;
    USE SIGNAL ;
    PORT
      LAYER M5 ;
        RECT  145.968 0 145.992 0.084 ;
    END
  END lk_od[164]
  PIN lk_od[165]
    DIRECTION INPUT ;
    USE SIGNAL ;
    PORT
      LAYER M5 ;
        RECT  146.064 0 146.088 0.084 ;
    END
  END lk_od[165]
  PIN lk_od[166]
    DIRECTION INPUT ;
    USE SIGNAL ;
    PORT
      LAYER M5 ;
        RECT  146.16 0 146.184 0.084 ;
    END
  END lk_od[166]
  PIN lk_od[167]
    DIRECTION INPUT ;
    USE SIGNAL ;
    PORT
      LAYER M5 ;
        RECT  146.256 0 146.28 0.084 ;
    END
  END lk_od[167]
  PIN lk_od[168]
    DIRECTION INPUT ;
    USE SIGNAL ;
    PORT
      LAYER M5 ;
        RECT  146.352 0 146.376 0.084 ;
    END
  END lk_od[168]
  PIN lk_od[169]
    DIRECTION INPUT ;
    USE SIGNAL ;
    PORT
      LAYER M5 ;
        RECT  146.448 0 146.472 0.084 ;
    END
  END lk_od[169]
  PIN lk_od[16]
    DIRECTION INPUT ;
    USE SIGNAL ;
    PORT
      LAYER M5 ;
        RECT  163.248 0 163.272 0.084 ;
    END
  END lk_od[16]
  PIN lk_od[170]
    DIRECTION INPUT ;
    USE SIGNAL ;
    PORT
      LAYER M5 ;
        RECT  146.544 0 146.568 0.084 ;
    END
  END lk_od[170]
  PIN lk_od[171]
    DIRECTION INPUT ;
    USE SIGNAL ;
    PORT
      LAYER M5 ;
        RECT  146.64 0 146.664 0.084 ;
    END
  END lk_od[171]
  PIN lk_od[172]
    DIRECTION INPUT ;
    USE SIGNAL ;
    PORT
      LAYER M5 ;
        RECT  146.736 0 146.76 0.084 ;
    END
  END lk_od[172]
  PIN lk_od[173]
    DIRECTION INPUT ;
    USE SIGNAL ;
    PORT
      LAYER M5 ;
        RECT  146.832 0 146.856 0.084 ;
    END
  END lk_od[173]
  PIN lk_od[174]
    DIRECTION INPUT ;
    USE SIGNAL ;
    PORT
      LAYER M5 ;
        RECT  146.928 0 146.952 0.084 ;
    END
  END lk_od[174]
  PIN lk_od[175]
    DIRECTION INPUT ;
    USE SIGNAL ;
    PORT
      LAYER M5 ;
        RECT  147.024 0 147.048 0.084 ;
    END
  END lk_od[175]
  PIN lk_od[176]
    DIRECTION INPUT ;
    USE SIGNAL ;
    PORT
      LAYER M5 ;
        RECT  147.12 0 147.144 0.084 ;
    END
  END lk_od[176]
  PIN lk_od[177]
    DIRECTION INPUT ;
    USE SIGNAL ;
    PORT
      LAYER M5 ;
        RECT  147.216 0 147.24 0.084 ;
    END
  END lk_od[177]
  PIN lk_od[178]
    DIRECTION INPUT ;
    USE SIGNAL ;
    PORT
      LAYER M5 ;
        RECT  147.312 0 147.336 0.084 ;
    END
  END lk_od[178]
  PIN lk_od[179]
    DIRECTION INPUT ;
    USE SIGNAL ;
    PORT
      LAYER M5 ;
        RECT  141.264 0 141.288 0.084 ;
    END
  END lk_od[179]
  PIN lk_od[17]
    DIRECTION INPUT ;
    USE SIGNAL ;
    PORT
      LAYER M5 ;
        RECT  163.344 0 163.368 0.084 ;
    END
  END lk_od[17]
  PIN lk_od[180]
    DIRECTION INPUT ;
    USE SIGNAL ;
    PORT
      LAYER M5 ;
        RECT  141.36 0 141.384 0.084 ;
    END
  END lk_od[180]
  PIN lk_od[181]
    DIRECTION INPUT ;
    USE SIGNAL ;
    PORT
      LAYER M5 ;
        RECT  141.456 0 141.48 0.084 ;
    END
  END lk_od[181]
  PIN lk_od[182]
    DIRECTION INPUT ;
    USE SIGNAL ;
    PORT
      LAYER M5 ;
        RECT  141.552 0 141.576 0.084 ;
    END
  END lk_od[182]
  PIN lk_od[183]
    DIRECTION INPUT ;
    USE SIGNAL ;
    PORT
      LAYER M5 ;
        RECT  141.648 0 141.672 0.084 ;
    END
  END lk_od[183]
  PIN lk_od[184]
    DIRECTION INPUT ;
    USE SIGNAL ;
    PORT
      LAYER M5 ;
        RECT  141.744 0 141.768 0.084 ;
    END
  END lk_od[184]
  PIN lk_od[185]
    DIRECTION INPUT ;
    USE SIGNAL ;
    PORT
      LAYER M5 ;
        RECT  141.84 0 141.864 0.084 ;
    END
  END lk_od[185]
  PIN lk_od[186]
    DIRECTION INPUT ;
    USE SIGNAL ;
    PORT
      LAYER M5 ;
        RECT  141.936 0 141.96 0.084 ;
    END
  END lk_od[186]
  PIN lk_od[187]
    DIRECTION INPUT ;
    USE SIGNAL ;
    PORT
      LAYER M5 ;
        RECT  142.032 0 142.056 0.084 ;
    END
  END lk_od[187]
  PIN lk_od[188]
    DIRECTION INPUT ;
    USE SIGNAL ;
    PORT
      LAYER M5 ;
        RECT  142.128 0 142.152 0.084 ;
    END
  END lk_od[188]
  PIN lk_od[189]
    DIRECTION INPUT ;
    USE SIGNAL ;
    PORT
      LAYER M5 ;
        RECT  142.224 0 142.248 0.084 ;
    END
  END lk_od[189]
  PIN lk_od[18]
    DIRECTION INPUT ;
    USE SIGNAL ;
    PORT
      LAYER M5 ;
        RECT  163.44 0 163.464 0.084 ;
    END
  END lk_od[18]
  PIN lk_od[190]
    DIRECTION INPUT ;
    USE SIGNAL ;
    PORT
      LAYER M5 ;
        RECT  142.32 0 142.344 0.084 ;
    END
  END lk_od[190]
  PIN lk_od[191]
    DIRECTION INPUT ;
    USE SIGNAL ;
    PORT
      LAYER M5 ;
        RECT  142.416 0 142.44 0.084 ;
    END
  END lk_od[191]
  PIN lk_od[192]
    DIRECTION INPUT ;
    USE SIGNAL ;
    PORT
      LAYER M5 ;
        RECT  142.512 0 142.536 0.084 ;
    END
  END lk_od[192]
  PIN lk_od[193]
    DIRECTION INPUT ;
    USE SIGNAL ;
    PORT
      LAYER M5 ;
        RECT  142.608 0 142.632 0.084 ;
    END
  END lk_od[193]
  PIN lk_od[194]
    DIRECTION INPUT ;
    USE SIGNAL ;
    PORT
      LAYER M5 ;
        RECT  142.704 0 142.728 0.084 ;
    END
  END lk_od[194]
  PIN lk_od[195]
    DIRECTION INPUT ;
    USE SIGNAL ;
    PORT
      LAYER M5 ;
        RECT  142.8 0 142.824 0.084 ;
    END
  END lk_od[195]
  PIN lk_od[196]
    DIRECTION INPUT ;
    USE SIGNAL ;
    PORT
      LAYER M5 ;
        RECT  142.896 0 142.92 0.084 ;
    END
  END lk_od[196]
  PIN lk_od[197]
    DIRECTION INPUT ;
    USE SIGNAL ;
    PORT
      LAYER M5 ;
        RECT  142.992 0 143.016 0.084 ;
    END
  END lk_od[197]
  PIN lk_od[198]
    DIRECTION INPUT ;
    USE SIGNAL ;
    PORT
      LAYER M5 ;
        RECT  143.088 0 143.112 0.084 ;
    END
  END lk_od[198]
  PIN lk_od[199]
    DIRECTION INPUT ;
    USE SIGNAL ;
    PORT
      LAYER M5 ;
        RECT  143.184 0 143.208 0.084 ;
    END
  END lk_od[199]
  PIN lk_od[19]
    DIRECTION INPUT ;
    USE SIGNAL ;
    PORT
      LAYER M5 ;
        RECT  147.408 0 147.432 0.084 ;
    END
  END lk_od[19]
  PIN lk_od[1]
    DIRECTION INPUT ;
    USE SIGNAL ;
    PORT
      LAYER M5 ;
        RECT  161.808 0 161.832 0.084 ;
    END
  END lk_od[1]
  PIN lk_od[200]
    DIRECTION INPUT ;
    USE SIGNAL ;
    PORT
      LAYER M5 ;
        RECT  143.28 0 143.304 0.084 ;
    END
  END lk_od[200]
  PIN lk_od[201]
    DIRECTION INPUT ;
    USE SIGNAL ;
    PORT
      LAYER M5 ;
        RECT  143.376 0 143.4 0.084 ;
    END
  END lk_od[201]
  PIN lk_od[202]
    DIRECTION INPUT ;
    USE SIGNAL ;
    PORT
      LAYER M5 ;
        RECT  143.472 0 143.496 0.084 ;
    END
  END lk_od[202]
  PIN lk_od[203]
    DIRECTION INPUT ;
    USE SIGNAL ;
    PORT
      LAYER M5 ;
        RECT  143.568 0 143.592 0.084 ;
    END
  END lk_od[203]
  PIN lk_od[204]
    DIRECTION INPUT ;
    USE SIGNAL ;
    PORT
      LAYER M5 ;
        RECT  143.664 0 143.688 0.084 ;
    END
  END lk_od[204]
  PIN lk_od[205]
    DIRECTION INPUT ;
    USE SIGNAL ;
    PORT
      LAYER M5 ;
        RECT  143.76 0 143.784 0.084 ;
    END
  END lk_od[205]
  PIN lk_od[206]
    DIRECTION INPUT ;
    USE SIGNAL ;
    PORT
      LAYER M5 ;
        RECT  143.856 0 143.88 0.084 ;
    END
  END lk_od[206]
  PIN lk_od[207]
    DIRECTION INPUT ;
    USE SIGNAL ;
    PORT
      LAYER M5 ;
        RECT  143.952 0 143.976 0.084 ;
    END
  END lk_od[207]
  PIN lk_od[208]
    DIRECTION INPUT ;
    USE SIGNAL ;
    PORT
      LAYER M5 ;
        RECT  144.048 0 144.072 0.084 ;
    END
  END lk_od[208]
  PIN lk_od[209]
    DIRECTION INPUT ;
    USE SIGNAL ;
    PORT
      LAYER M5 ;
        RECT  144.144 0 144.168 0.084 ;
    END
  END lk_od[209]
  PIN lk_od[20]
    DIRECTION INPUT ;
    USE SIGNAL ;
    PORT
      LAYER M5 ;
        RECT  147.504 0 147.528 0.084 ;
    END
  END lk_od[20]
  PIN lk_od[210]
    DIRECTION INPUT ;
    USE SIGNAL ;
    PORT
      LAYER M5 ;
        RECT  144.24 0 144.264 0.084 ;
    END
  END lk_od[210]
  PIN lk_od[211]
    DIRECTION INPUT ;
    USE SIGNAL ;
    PORT
      LAYER M5 ;
        RECT  154.32 0 154.344 0.084 ;
    END
  END lk_od[211]
  PIN lk_od[212]
    DIRECTION INPUT ;
    USE SIGNAL ;
    PORT
      LAYER M5 ;
        RECT  154.416 0 154.44 0.084 ;
    END
  END lk_od[212]
  PIN lk_od[213]
    DIRECTION INPUT ;
    USE SIGNAL ;
    PORT
      LAYER M5 ;
        RECT  154.512 0 154.536 0.084 ;
    END
  END lk_od[213]
  PIN lk_od[214]
    DIRECTION INPUT ;
    USE SIGNAL ;
    PORT
      LAYER M5 ;
        RECT  154.608 0 154.632 0.084 ;
    END
  END lk_od[214]
  PIN lk_od[215]
    DIRECTION INPUT ;
    USE SIGNAL ;
    PORT
      LAYER M5 ;
        RECT  154.704 0 154.728 0.084 ;
    END
  END lk_od[215]
  PIN lk_od[216]
    DIRECTION INPUT ;
    USE SIGNAL ;
    PORT
      LAYER M5 ;
        RECT  154.8 0 154.824 0.084 ;
    END
  END lk_od[216]
  PIN lk_od[217]
    DIRECTION INPUT ;
    USE SIGNAL ;
    PORT
      LAYER M5 ;
        RECT  154.896 0 154.92 0.084 ;
    END
  END lk_od[217]
  PIN lk_od[218]
    DIRECTION INPUT ;
    USE SIGNAL ;
    PORT
      LAYER M5 ;
        RECT  154.992 0 155.016 0.084 ;
    END
  END lk_od[218]
  PIN lk_od[219]
    DIRECTION INPUT ;
    USE SIGNAL ;
    PORT
      LAYER M5 ;
        RECT  155.088 0 155.112 0.084 ;
    END
  END lk_od[219]
  PIN lk_od[21]
    DIRECTION INPUT ;
    USE SIGNAL ;
    PORT
      LAYER M5 ;
        RECT  147.6 0 147.624 0.084 ;
    END
  END lk_od[21]
  PIN lk_od[220]
    DIRECTION INPUT ;
    USE SIGNAL ;
    PORT
      LAYER M5 ;
        RECT  155.184 0 155.208 0.084 ;
    END
  END lk_od[220]
  PIN lk_od[221]
    DIRECTION INPUT ;
    USE SIGNAL ;
    PORT
      LAYER M5 ;
        RECT  155.28 0 155.304 0.084 ;
    END
  END lk_od[221]
  PIN lk_od[222]
    DIRECTION INPUT ;
    USE SIGNAL ;
    PORT
      LAYER M5 ;
        RECT  155.376 0 155.4 0.084 ;
    END
  END lk_od[222]
  PIN lk_od[223]
    DIRECTION INPUT ;
    USE SIGNAL ;
    PORT
      LAYER M5 ;
        RECT  155.472 0 155.496 0.084 ;
    END
  END lk_od[223]
  PIN lk_od[224]
    DIRECTION INPUT ;
    USE SIGNAL ;
    PORT
      LAYER M5 ;
        RECT  155.568 0 155.592 0.084 ;
    END
  END lk_od[224]
  PIN lk_od[225]
    DIRECTION INPUT ;
    USE SIGNAL ;
    PORT
      LAYER M5 ;
        RECT  155.664 0 155.688 0.084 ;
    END
  END lk_od[225]
  PIN lk_od[226]
    DIRECTION INPUT ;
    USE SIGNAL ;
    PORT
      LAYER M5 ;
        RECT  155.76 0 155.784 0.084 ;
    END
  END lk_od[226]
  PIN lk_od[227]
    DIRECTION INPUT ;
    USE SIGNAL ;
    PORT
      LAYER M5 ;
        RECT  155.856 0 155.88 0.084 ;
    END
  END lk_od[227]
  PIN lk_od[228]
    DIRECTION INPUT ;
    USE SIGNAL ;
    PORT
      LAYER M5 ;
        RECT  155.952 0 155.976 0.084 ;
    END
  END lk_od[228]
  PIN lk_od[229]
    DIRECTION INPUT ;
    USE SIGNAL ;
    PORT
      LAYER M5 ;
        RECT  156.048 0 156.072 0.084 ;
    END
  END lk_od[229]
  PIN lk_od[22]
    DIRECTION INPUT ;
    USE SIGNAL ;
    PORT
      LAYER M5 ;
        RECT  147.696 0 147.72 0.084 ;
    END
  END lk_od[22]
  PIN lk_od[230]
    DIRECTION INPUT ;
    USE SIGNAL ;
    PORT
      LAYER M5 ;
        RECT  156.144 0 156.168 0.084 ;
    END
  END lk_od[230]
  PIN lk_od[231]
    DIRECTION INPUT ;
    USE SIGNAL ;
    PORT
      LAYER M5 ;
        RECT  156.24 0 156.264 0.084 ;
    END
  END lk_od[231]
  PIN lk_od[232]
    DIRECTION INPUT ;
    USE SIGNAL ;
    PORT
      LAYER M5 ;
        RECT  156.336 0 156.36 0.084 ;
    END
  END lk_od[232]
  PIN lk_od[233]
    DIRECTION INPUT ;
    USE SIGNAL ;
    PORT
      LAYER M5 ;
        RECT  156.432 0 156.456 0.084 ;
    END
  END lk_od[233]
  PIN lk_od[234]
    DIRECTION INPUT ;
    USE SIGNAL ;
    PORT
      LAYER M5 ;
        RECT  156.528 0 156.552 0.084 ;
    END
  END lk_od[234]
  PIN lk_od[235]
    DIRECTION INPUT ;
    USE SIGNAL ;
    PORT
      LAYER M5 ;
        RECT  156.624 0 156.648 0.084 ;
    END
  END lk_od[235]
  PIN lk_od[236]
    DIRECTION INPUT ;
    USE SIGNAL ;
    PORT
      LAYER M5 ;
        RECT  156.72 0 156.744 0.084 ;
    END
  END lk_od[236]
  PIN lk_od[237]
    DIRECTION INPUT ;
    USE SIGNAL ;
    PORT
      LAYER M5 ;
        RECT  156.816 0 156.84 0.084 ;
    END
  END lk_od[237]
  PIN lk_od[238]
    DIRECTION INPUT ;
    USE SIGNAL ;
    PORT
      LAYER M5 ;
        RECT  156.912 0 156.936 0.084 ;
    END
  END lk_od[238]
  PIN lk_od[239]
    DIRECTION INPUT ;
    USE SIGNAL ;
    PORT
      LAYER M5 ;
        RECT  157.008 0 157.032 0.084 ;
    END
  END lk_od[239]
  PIN lk_od[23]
    DIRECTION INPUT ;
    USE SIGNAL ;
    PORT
      LAYER M5 ;
        RECT  147.792 0 147.816 0.084 ;
    END
  END lk_od[23]
  PIN lk_od[240]
    DIRECTION INPUT ;
    USE SIGNAL ;
    PORT
      LAYER M5 ;
        RECT  157.104 0 157.128 0.084 ;
    END
  END lk_od[240]
  PIN lk_od[241]
    DIRECTION INPUT ;
    USE SIGNAL ;
    PORT
      LAYER M5 ;
        RECT  157.2 0 157.224 0.084 ;
    END
  END lk_od[241]
  PIN lk_od[242]
    DIRECTION INPUT ;
    USE SIGNAL ;
    PORT
      LAYER M5 ;
        RECT  157.296 0 157.32 0.084 ;
    END
  END lk_od[242]
  PIN lk_od[243]
    DIRECTION INPUT ;
    USE SIGNAL ;
    PORT
      LAYER M5 ;
        RECT  157.392 0 157.416 0.084 ;
    END
  END lk_od[243]
  PIN lk_od[244]
    DIRECTION INPUT ;
    USE SIGNAL ;
    PORT
      LAYER M5 ;
        RECT  157.488 0 157.512 0.084 ;
    END
  END lk_od[244]
  PIN lk_od[245]
    DIRECTION INPUT ;
    USE SIGNAL ;
    PORT
      LAYER M5 ;
        RECT  157.584 0 157.608 0.084 ;
    END
  END lk_od[245]
  PIN lk_od[246]
    DIRECTION INPUT ;
    USE SIGNAL ;
    PORT
      LAYER M5 ;
        RECT  157.68 0 157.704 0.084 ;
    END
  END lk_od[246]
  PIN lk_od[247]
    DIRECTION INPUT ;
    USE SIGNAL ;
    PORT
      LAYER M5 ;
        RECT  157.776 0 157.8 0.084 ;
    END
  END lk_od[247]
  PIN lk_od[248]
    DIRECTION INPUT ;
    USE SIGNAL ;
    PORT
      LAYER M5 ;
        RECT  157.872 0 157.896 0.084 ;
    END
  END lk_od[248]
  PIN lk_od[249]
    DIRECTION INPUT ;
    USE SIGNAL ;
    PORT
      LAYER M5 ;
        RECT  157.968 0 157.992 0.084 ;
    END
  END lk_od[249]
  PIN lk_od[24]
    DIRECTION INPUT ;
    USE SIGNAL ;
    PORT
      LAYER M5 ;
        RECT  147.888 0 147.912 0.084 ;
    END
  END lk_od[24]
  PIN lk_od[250]
    DIRECTION INPUT ;
    USE SIGNAL ;
    PORT
      LAYER M5 ;
        RECT  158.064 0 158.088 0.084 ;
    END
  END lk_od[250]
  PIN lk_od[251]
    DIRECTION INPUT ;
    USE SIGNAL ;
    PORT
      LAYER M5 ;
        RECT  158.16 0 158.184 0.084 ;
    END
  END lk_od[251]
  PIN lk_od[252]
    DIRECTION INPUT ;
    USE SIGNAL ;
    PORT
      LAYER M5 ;
        RECT  158.256 0 158.28 0.084 ;
    END
  END lk_od[252]
  PIN lk_od[253]
    DIRECTION INPUT ;
    USE SIGNAL ;
    PORT
      LAYER M5 ;
        RECT  158.352 0 158.376 0.084 ;
    END
  END lk_od[253]
  PIN lk_od[254]
    DIRECTION INPUT ;
    USE SIGNAL ;
    PORT
      LAYER M5 ;
        RECT  158.448 0 158.472 0.084 ;
    END
  END lk_od[254]
  PIN lk_od[255]
    DIRECTION INPUT ;
    USE SIGNAL ;
    PORT
      LAYER M5 ;
        RECT  158.544 0 158.568 0.084 ;
    END
  END lk_od[255]
  PIN lk_od[256]
    DIRECTION INPUT ;
    USE SIGNAL ;
    PORT
      LAYER M5 ;
        RECT  158.64 0 158.664 0.084 ;
    END
  END lk_od[256]
  PIN lk_od[257]
    DIRECTION INPUT ;
    USE SIGNAL ;
    PORT
      LAYER M5 ;
        RECT  158.736 0 158.76 0.084 ;
    END
  END lk_od[257]
  PIN lk_od[258]
    DIRECTION INPUT ;
    USE SIGNAL ;
    PORT
      LAYER M5 ;
        RECT  158.832 0 158.856 0.084 ;
    END
  END lk_od[258]
  PIN lk_od[259]
    DIRECTION INPUT ;
    USE SIGNAL ;
    PORT
      LAYER M5 ;
        RECT  158.928 0 158.952 0.084 ;
    END
  END lk_od[259]
  PIN lk_od[25]
    DIRECTION INPUT ;
    USE SIGNAL ;
    PORT
      LAYER M5 ;
        RECT  147.984 0 148.008 0.084 ;
    END
  END lk_od[25]
  PIN lk_od[260]
    DIRECTION INPUT ;
    USE SIGNAL ;
    PORT
      LAYER M5 ;
        RECT  159.024 0 159.048 0.084 ;
    END
  END lk_od[260]
  PIN lk_od[261]
    DIRECTION INPUT ;
    USE SIGNAL ;
    PORT
      LAYER M5 ;
        RECT  159.12 0 159.144 0.084 ;
    END
  END lk_od[261]
  PIN lk_od[262]
    DIRECTION INPUT ;
    USE SIGNAL ;
    PORT
      LAYER M5 ;
        RECT  159.216 0 159.24 0.084 ;
    END
  END lk_od[262]
  PIN lk_od[263]
    DIRECTION INPUT ;
    USE SIGNAL ;
    PORT
      LAYER M5 ;
        RECT  159.312 0 159.336 0.084 ;
    END
  END lk_od[263]
  PIN lk_od[26]
    DIRECTION INPUT ;
    USE SIGNAL ;
    PORT
      LAYER M5 ;
        RECT  148.08 0 148.104 0.084 ;
    END
  END lk_od[26]
  PIN lk_od[27]
    DIRECTION INPUT ;
    USE SIGNAL ;
    PORT
      LAYER M5 ;
        RECT  148.176 0 148.2 0.084 ;
    END
  END lk_od[27]
  PIN lk_od[28]
    DIRECTION INPUT ;
    USE SIGNAL ;
    PORT
      LAYER M5 ;
        RECT  148.272 0 148.296 0.084 ;
    END
  END lk_od[28]
  PIN lk_od[29]
    DIRECTION INPUT ;
    USE SIGNAL ;
    PORT
      LAYER M5 ;
        RECT  148.368 0 148.392 0.084 ;
    END
  END lk_od[29]
  PIN lk_od[2]
    DIRECTION INPUT ;
    USE SIGNAL ;
    PORT
      LAYER M5 ;
        RECT  161.904 0 161.928 0.084 ;
    END
  END lk_od[2]
  PIN lk_od[30]
    DIRECTION INPUT ;
    USE SIGNAL ;
    PORT
      LAYER M5 ;
        RECT  148.464 0 148.488 0.084 ;
    END
  END lk_od[30]
  PIN lk_od[31]
    DIRECTION INPUT ;
    USE SIGNAL ;
    PORT
      LAYER M5 ;
        RECT  148.56 0 148.584 0.084 ;
    END
  END lk_od[31]
  PIN lk_od[32]
    DIRECTION INPUT ;
    USE SIGNAL ;
    PORT
      LAYER M5 ;
        RECT  148.656 0 148.68 0.084 ;
    END
  END lk_od[32]
  PIN lk_od[33]
    DIRECTION INPUT ;
    USE SIGNAL ;
    PORT
      LAYER M5 ;
        RECT  148.752 0 148.776 0.084 ;
    END
  END lk_od[33]
  PIN lk_od[34]
    DIRECTION INPUT ;
    USE SIGNAL ;
    PORT
      LAYER M5 ;
        RECT  148.848 0 148.872 0.084 ;
    END
  END lk_od[34]
  PIN lk_od[35]
    DIRECTION INPUT ;
    USE SIGNAL ;
    PORT
      LAYER M5 ;
        RECT  148.944 0 148.968 0.084 ;
    END
  END lk_od[35]
  PIN lk_od[36]
    DIRECTION INPUT ;
    USE SIGNAL ;
    PORT
      LAYER M5 ;
        RECT  149.04 0 149.064 0.084 ;
    END
  END lk_od[36]
  PIN lk_od[37]
    DIRECTION INPUT ;
    USE SIGNAL ;
    PORT
      LAYER M5 ;
        RECT  149.136 0 149.16 0.084 ;
    END
  END lk_od[37]
  PIN lk_od[38]
    DIRECTION INPUT ;
    USE SIGNAL ;
    PORT
      LAYER M5 ;
        RECT  149.232 0 149.256 0.084 ;
    END
  END lk_od[38]
  PIN lk_od[39]
    DIRECTION INPUT ;
    USE SIGNAL ;
    PORT
      LAYER M5 ;
        RECT  149.328 0 149.352 0.084 ;
    END
  END lk_od[39]
  PIN lk_od[3]
    DIRECTION INPUT ;
    USE SIGNAL ;
    PORT
      LAYER M5 ;
        RECT  162 0 162.024 0.084 ;
    END
  END lk_od[3]
  PIN lk_od[40]
    DIRECTION INPUT ;
    USE SIGNAL ;
    PORT
      LAYER M5 ;
        RECT  149.424 0 149.448 0.084 ;
    END
  END lk_od[40]
  PIN lk_od[41]
    DIRECTION INPUT ;
    USE SIGNAL ;
    PORT
      LAYER M5 ;
        RECT  149.52 0 149.544 0.084 ;
    END
  END lk_od[41]
  PIN lk_od[42]
    DIRECTION INPUT ;
    USE SIGNAL ;
    PORT
      LAYER M5 ;
        RECT  149.616 0 149.64 0.084 ;
    END
  END lk_od[42]
  PIN lk_od[43]
    DIRECTION INPUT ;
    USE SIGNAL ;
    PORT
      LAYER M5 ;
        RECT  149.712 0 149.736 0.084 ;
    END
  END lk_od[43]
  PIN lk_od[44]
    DIRECTION INPUT ;
    USE SIGNAL ;
    PORT
      LAYER M5 ;
        RECT  149.808 0 149.832 0.084 ;
    END
  END lk_od[44]
  PIN lk_od[45]
    DIRECTION INPUT ;
    USE SIGNAL ;
    PORT
      LAYER M5 ;
        RECT  149.904 0 149.928 0.084 ;
    END
  END lk_od[45]
  PIN lk_od[46]
    DIRECTION INPUT ;
    USE SIGNAL ;
    PORT
      LAYER M5 ;
        RECT  150 0 150.024 0.084 ;
    END
  END lk_od[46]
  PIN lk_od[47]
    DIRECTION INPUT ;
    USE SIGNAL ;
    PORT
      LAYER M5 ;
        RECT  150.096 0 150.12 0.084 ;
    END
  END lk_od[47]
  PIN lk_od[48]
    DIRECTION INPUT ;
    USE SIGNAL ;
    PORT
      LAYER M5 ;
        RECT  150.192 0 150.216 0.084 ;
    END
  END lk_od[48]
  PIN lk_od[49]
    DIRECTION INPUT ;
    USE SIGNAL ;
    PORT
      LAYER M5 ;
        RECT  150.288 0 150.312 0.084 ;
    END
  END lk_od[49]
  PIN lk_od[4]
    DIRECTION INPUT ;
    USE SIGNAL ;
    PORT
      LAYER M5 ;
        RECT  162.096 0 162.12 0.084 ;
    END
  END lk_od[4]
  PIN lk_od[50]
    DIRECTION INPUT ;
    USE SIGNAL ;
    PORT
      LAYER M5 ;
        RECT  150.384 0 150.408 0.084 ;
    END
  END lk_od[50]
  PIN lk_od[51]
    DIRECTION INPUT ;
    USE SIGNAL ;
    PORT
      LAYER M5 ;
        RECT  150.48 0 150.504 0.084 ;
    END
  END lk_od[51]
  PIN lk_od[52]
    DIRECTION INPUT ;
    USE SIGNAL ;
    PORT
      LAYER M5 ;
        RECT  150.576 0 150.6 0.084 ;
    END
  END lk_od[52]
  PIN lk_od[53]
    DIRECTION INPUT ;
    USE SIGNAL ;
    PORT
      LAYER M5 ;
        RECT  150.672 0 150.696 0.084 ;
    END
  END lk_od[53]
  PIN lk_od[54]
    DIRECTION INPUT ;
    USE SIGNAL ;
    PORT
      LAYER M5 ;
        RECT  150.768 0 150.792 0.084 ;
    END
  END lk_od[54]
  PIN lk_od[55]
    DIRECTION INPUT ;
    USE SIGNAL ;
    PORT
      LAYER M5 ;
        RECT  150.864 0 150.888 0.084 ;
    END
  END lk_od[55]
  PIN lk_od[56]
    DIRECTION INPUT ;
    USE SIGNAL ;
    PORT
      LAYER M5 ;
        RECT  150.96 0 150.984 0.084 ;
    END
  END lk_od[56]
  PIN lk_od[57]
    DIRECTION INPUT ;
    USE SIGNAL ;
    PORT
      LAYER M5 ;
        RECT  151.056 0 151.08 0.084 ;
    END
  END lk_od[57]
  PIN lk_od[58]
    DIRECTION INPUT ;
    USE SIGNAL ;
    PORT
      LAYER M5 ;
        RECT  151.152 0 151.176 0.084 ;
    END
  END lk_od[58]
  PIN lk_od[59]
    DIRECTION INPUT ;
    USE SIGNAL ;
    PORT
      LAYER M5 ;
        RECT  151.248 0 151.272 0.084 ;
    END
  END lk_od[59]
  PIN lk_od[5]
    DIRECTION INPUT ;
    USE SIGNAL ;
    PORT
      LAYER M5 ;
        RECT  162.192 0 162.216 0.084 ;
    END
  END lk_od[5]
  PIN lk_od[60]
    DIRECTION INPUT ;
    USE SIGNAL ;
    PORT
      LAYER M5 ;
        RECT  151.344 0 151.368 0.084 ;
    END
  END lk_od[60]
  PIN lk_od[61]
    DIRECTION INPUT ;
    USE SIGNAL ;
    PORT
      LAYER M5 ;
        RECT  151.44 0 151.464 0.084 ;
    END
  END lk_od[61]
  PIN lk_od[62]
    DIRECTION INPUT ;
    USE SIGNAL ;
    PORT
      LAYER M5 ;
        RECT  151.536 0 151.56 0.084 ;
    END
  END lk_od[62]
  PIN lk_od[63]
    DIRECTION INPUT ;
    USE SIGNAL ;
    PORT
      LAYER M5 ;
        RECT  151.632 0 151.656 0.084 ;
    END
  END lk_od[63]
  PIN lk_od[64]
    DIRECTION INPUT ;
    USE SIGNAL ;
    PORT
      LAYER M5 ;
        RECT  151.728 0 151.752 0.084 ;
    END
  END lk_od[64]
  PIN lk_od[65]
    DIRECTION INPUT ;
    USE SIGNAL ;
    PORT
      LAYER M5 ;
        RECT  151.824 0 151.848 0.084 ;
    END
  END lk_od[65]
  PIN lk_od[66]
    DIRECTION INPUT ;
    USE SIGNAL ;
    PORT
      LAYER M5 ;
        RECT  151.92 0 151.944 0.084 ;
    END
  END lk_od[66]
  PIN lk_od[67]
    DIRECTION INPUT ;
    USE SIGNAL ;
    PORT
      LAYER M5 ;
        RECT  152.016 0 152.04 0.084 ;
    END
  END lk_od[67]
  PIN lk_od[68]
    DIRECTION INPUT ;
    USE SIGNAL ;
    PORT
      LAYER M5 ;
        RECT  152.112 0 152.136 0.084 ;
    END
  END lk_od[68]
  PIN lk_od[69]
    DIRECTION INPUT ;
    USE SIGNAL ;
    PORT
      LAYER M5 ;
        RECT  152.208 0 152.232 0.084 ;
    END
  END lk_od[69]
  PIN lk_od[6]
    DIRECTION INPUT ;
    USE SIGNAL ;
    PORT
      LAYER M5 ;
        RECT  162.288 0 162.312 0.084 ;
    END
  END lk_od[6]
  PIN lk_od[70]
    DIRECTION INPUT ;
    USE SIGNAL ;
    PORT
      LAYER M5 ;
        RECT  152.304 0 152.328 0.084 ;
    END
  END lk_od[70]
  PIN lk_od[71]
    DIRECTION INPUT ;
    USE SIGNAL ;
    PORT
      LAYER M5 ;
        RECT  152.4 0 152.424 0.084 ;
    END
  END lk_od[71]
  PIN lk_od[72]
    DIRECTION INPUT ;
    USE SIGNAL ;
    PORT
      LAYER M5 ;
        RECT  152.496 0 152.52 0.084 ;
    END
  END lk_od[72]
  PIN lk_od[73]
    DIRECTION INPUT ;
    USE SIGNAL ;
    PORT
      LAYER M5 ;
        RECT  152.592 0 152.616 0.084 ;
    END
  END lk_od[73]
  PIN lk_od[74]
    DIRECTION INPUT ;
    USE SIGNAL ;
    PORT
      LAYER M5 ;
        RECT  152.688 0 152.712 0.084 ;
    END
  END lk_od[74]
  PIN lk_od[75]
    DIRECTION INPUT ;
    USE SIGNAL ;
    PORT
      LAYER M5 ;
        RECT  152.784 0 152.808 0.084 ;
    END
  END lk_od[75]
  PIN lk_od[76]
    DIRECTION INPUT ;
    USE SIGNAL ;
    PORT
      LAYER M5 ;
        RECT  152.88 0 152.904 0.084 ;
    END
  END lk_od[76]
  PIN lk_od[77]
    DIRECTION INPUT ;
    USE SIGNAL ;
    PORT
      LAYER M5 ;
        RECT  152.976 0 153 0.084 ;
    END
  END lk_od[77]
  PIN lk_od[78]
    DIRECTION INPUT ;
    USE SIGNAL ;
    PORT
      LAYER M5 ;
        RECT  153.072 0 153.096 0.084 ;
    END
  END lk_od[78]
  PIN lk_od[79]
    DIRECTION INPUT ;
    USE SIGNAL ;
    PORT
      LAYER M5 ;
        RECT  153.168 0 153.192 0.084 ;
    END
  END lk_od[79]
  PIN lk_od[7]
    DIRECTION INPUT ;
    USE SIGNAL ;
    PORT
      LAYER M5 ;
        RECT  162.384 0 162.408 0.084 ;
    END
  END lk_od[7]
  PIN lk_od[80]
    DIRECTION INPUT ;
    USE SIGNAL ;
    PORT
      LAYER M5 ;
        RECT  153.264 0 153.288 0.084 ;
    END
  END lk_od[80]
  PIN lk_od[81]
    DIRECTION INPUT ;
    USE SIGNAL ;
    PORT
      LAYER M5 ;
        RECT  153.36 0 153.384 0.084 ;
    END
  END lk_od[81]
  PIN lk_od[82]
    DIRECTION INPUT ;
    USE SIGNAL ;
    PORT
      LAYER M5 ;
        RECT  153.456 0 153.48 0.084 ;
    END
  END lk_od[82]
  PIN lk_od[83]
    DIRECTION INPUT ;
    USE SIGNAL ;
    PORT
      LAYER M5 ;
        RECT  138.192 0 138.216 0.084 ;
    END
  END lk_od[83]
  PIN lk_od[84]
    DIRECTION INPUT ;
    USE SIGNAL ;
    PORT
      LAYER M5 ;
        RECT  138.288 0 138.312 0.084 ;
    END
  END lk_od[84]
  PIN lk_od[85]
    DIRECTION INPUT ;
    USE SIGNAL ;
    PORT
      LAYER M5 ;
        RECT  138.384 0 138.408 0.084 ;
    END
  END lk_od[85]
  PIN lk_od[86]
    DIRECTION INPUT ;
    USE SIGNAL ;
    PORT
      LAYER M5 ;
        RECT  138.48 0 138.504 0.084 ;
    END
  END lk_od[86]
  PIN lk_od[87]
    DIRECTION INPUT ;
    USE SIGNAL ;
    PORT
      LAYER M5 ;
        RECT  138.576 0 138.6 0.084 ;
    END
  END lk_od[87]
  PIN lk_od[88]
    DIRECTION INPUT ;
    USE SIGNAL ;
    PORT
      LAYER M5 ;
        RECT  138.672 0 138.696 0.084 ;
    END
  END lk_od[88]
  PIN lk_od[89]
    DIRECTION INPUT ;
    USE SIGNAL ;
    PORT
      LAYER M5 ;
        RECT  138.768 0 138.792 0.084 ;
    END
  END lk_od[89]
  PIN lk_od[8]
    DIRECTION INPUT ;
    USE SIGNAL ;
    PORT
      LAYER M5 ;
        RECT  162.48 0 162.504 0.084 ;
    END
  END lk_od[8]
  PIN lk_od[90]
    DIRECTION INPUT ;
    USE SIGNAL ;
    PORT
      LAYER M5 ;
        RECT  138.864 0 138.888 0.084 ;
    END
  END lk_od[90]
  PIN lk_od[91]
    DIRECTION INPUT ;
    USE SIGNAL ;
    PORT
      LAYER M5 ;
        RECT  138.96 0 138.984 0.084 ;
    END
  END lk_od[91]
  PIN lk_od[92]
    DIRECTION INPUT ;
    USE SIGNAL ;
    PORT
      LAYER M5 ;
        RECT  139.056 0 139.08 0.084 ;
    END
  END lk_od[92]
  PIN lk_od[93]
    DIRECTION INPUT ;
    USE SIGNAL ;
    PORT
      LAYER M5 ;
        RECT  139.152 0 139.176 0.084 ;
    END
  END lk_od[93]
  PIN lk_od[94]
    DIRECTION INPUT ;
    USE SIGNAL ;
    PORT
      LAYER M5 ;
        RECT  139.248 0 139.272 0.084 ;
    END
  END lk_od[94]
  PIN lk_od[95]
    DIRECTION INPUT ;
    USE SIGNAL ;
    PORT
      LAYER M5 ;
        RECT  139.344 0 139.368 0.084 ;
    END
  END lk_od[95]
  PIN lk_od[96]
    DIRECTION INPUT ;
    USE SIGNAL ;
    PORT
      LAYER M5 ;
        RECT  139.44 0 139.464 0.084 ;
    END
  END lk_od[96]
  PIN lk_od[97]
    DIRECTION INPUT ;
    USE SIGNAL ;
    PORT
      LAYER M5 ;
        RECT  139.536 0 139.56 0.084 ;
    END
  END lk_od[97]
  PIN lk_od[98]
    DIRECTION INPUT ;
    USE SIGNAL ;
    PORT
      LAYER M5 ;
        RECT  139.632 0 139.656 0.084 ;
    END
  END lk_od[98]
  PIN lk_od[99]
    DIRECTION INPUT ;
    USE SIGNAL ;
    PORT
      LAYER M5 ;
        RECT  139.728 0 139.752 0.084 ;
    END
  END lk_od[99]
  PIN lk_od[9]
    DIRECTION INPUT ;
    USE SIGNAL ;
    PORT
      LAYER M5 ;
        RECT  162.576 0 162.6 0.084 ;
    END
  END lk_od[9]
  PIN lk_os[0]
    DIRECTION INPUT ;
    USE SIGNAL ;
    PORT
      LAYER M5 ;
        RECT  159.408 0 159.432 0.084 ;
    END
  END lk_os[0]
  PIN lk_os[1]
    DIRECTION INPUT ;
    USE SIGNAL ;
    PORT
      LAYER M5 ;
        RECT  159.504 0 159.528 0.084 ;
    END
  END lk_os[1]
  PIN lk_os[2]
    DIRECTION INPUT ;
    USE SIGNAL ;
    PORT
      LAYER M5 ;
        RECT  159.6 0 159.624 0.084 ;
    END
  END lk_os[2]
  PIN lk_ov
    DIRECTION INPUT ;
    USE SIGNAL ;
    PORT
      LAYER M5 ;
        RECT  159.696 0 159.72 0.084 ;
    END
  END lk_ov
  PIN lk_rel[0]
    DIRECTION OUTPUT ;
    USE SIGNAL ;
    PORT
      LAYER M5 ;
        RECT  159.792 0 159.816 0.084 ;
    END
  END lk_rel[0]
  PIN lk_rel[1]
    DIRECTION OUTPUT ;
    USE SIGNAL ;
    PORT
      LAYER M5 ;
        RECT  159.888 0 159.912 0.084 ;
    END
  END lk_rel[1]
  PIN lk_rel[2]
    DIRECTION OUTPUT ;
    USE SIGNAL ;
    PORT
      LAYER M5 ;
        RECT  159.984 0 160.008 0.084 ;
    END
  END lk_rel[2]
  PIN lk_rel[3]
    DIRECTION OUTPUT ;
    USE SIGNAL ;
    PORT
      LAYER M5 ;
        RECT  160.08 0 160.104 0.084 ;
    END
  END lk_rel[3]
  PIN lk_stb
    DIRECTION INPUT ;
    USE SIGNAL ;
    PORT
      LAYER M5 ;
        RECT  160.176 0 160.2 0.084 ;
    END
  END lk_stb
  PIN lk_sts[0]
    DIRECTION INPUT ;
    USE SIGNAL ;
    PORT
      LAYER M5 ;
        RECT  160.272 0 160.296 0.084 ;
    END
  END lk_sts[0]
  PIN lk_sts[1]
    DIRECTION INPUT ;
    USE SIGNAL ;
    PORT
      LAYER M5 ;
        RECT  160.368 0 160.392 0.084 ;
    END
  END lk_sts[1]
  PIN lk_sts[2]
    DIRECTION INPUT ;
    USE SIGNAL ;
    PORT
      LAYER M5 ;
        RECT  173.52 0 173.544 0.084 ;
    END
  END lk_sts[2]
  PIN lk_stv
    DIRECTION INPUT ;
    USE SIGNAL ;
    PORT
      LAYER M5 ;
        RECT  173.616 0 173.64 0.084 ;
    END
  END lk_stv
  PIN lk_wcred
    DIRECTION INPUT ;
    USE SIGNAL ;
    PORT
      LAYER M5 ;
        RECT  173.712 0 173.736 0.084 ;
    END
  END lk_wcred
  PIN lk_wid[0]
    DIRECTION OUTPUT ;
    USE SIGNAL ;
    PORT
      LAYER M5 ;
        RECT  173.808 0 173.832 0.084 ;
    END
  END lk_wid[0]
  PIN lk_wid[10]
    DIRECTION OUTPUT ;
    USE SIGNAL ;
    PORT
      LAYER M5 ;
        RECT  174.768 0 174.792 0.084 ;
    END
  END lk_wid[10]
  PIN lk_wid[11]
    DIRECTION OUTPUT ;
    USE SIGNAL ;
    PORT
      LAYER M5 ;
        RECT  174.864 0 174.888 0.084 ;
    END
  END lk_wid[11]
  PIN lk_wid[12]
    DIRECTION OUTPUT ;
    USE SIGNAL ;
    PORT
      LAYER M5 ;
        RECT  174.96 0 174.984 0.084 ;
    END
  END lk_wid[12]
  PIN lk_wid[13]
    DIRECTION OUTPUT ;
    USE SIGNAL ;
    PORT
      LAYER M5 ;
        RECT  175.056 0 175.08 0.084 ;
    END
  END lk_wid[13]
  PIN lk_wid[14]
    DIRECTION OUTPUT ;
    USE SIGNAL ;
    PORT
      LAYER M5 ;
        RECT  175.152 0 175.176 0.084 ;
    END
  END lk_wid[14]
  PIN lk_wid[15]
    DIRECTION OUTPUT ;
    USE SIGNAL ;
    PORT
      LAYER M5 ;
        RECT  175.248 0 175.272 0.084 ;
    END
  END lk_wid[15]
  PIN lk_wid[16]
    DIRECTION OUTPUT ;
    USE SIGNAL ;
    PORT
      LAYER M5 ;
        RECT  175.344 0 175.368 0.084 ;
    END
  END lk_wid[16]
  PIN lk_wid[17]
    DIRECTION OUTPUT ;
    USE SIGNAL ;
    PORT
      LAYER M5 ;
        RECT  175.44 0 175.464 0.084 ;
    END
  END lk_wid[17]
  PIN lk_wid[18]
    DIRECTION OUTPUT ;
    USE SIGNAL ;
    PORT
      LAYER M5 ;
        RECT  175.536 0 175.56 0.084 ;
    END
  END lk_wid[18]
  PIN lk_wid[19]
    DIRECTION OUTPUT ;
    USE SIGNAL ;
    PORT
      LAYER M5 ;
        RECT  175.632 0 175.656 0.084 ;
    END
  END lk_wid[19]
  PIN lk_wid[1]
    DIRECTION OUTPUT ;
    USE SIGNAL ;
    PORT
      LAYER M5 ;
        RECT  173.904 0 173.928 0.084 ;
    END
  END lk_wid[1]
  PIN lk_wid[20]
    DIRECTION OUTPUT ;
    USE SIGNAL ;
    PORT
      LAYER M5 ;
        RECT  175.728 0 175.752 0.084 ;
    END
  END lk_wid[20]
  PIN lk_wid[21]
    DIRECTION OUTPUT ;
    USE SIGNAL ;
    PORT
      LAYER M5 ;
        RECT  175.824 0 175.848 0.084 ;
    END
  END lk_wid[21]
  PIN lk_wid[22]
    DIRECTION OUTPUT ;
    USE SIGNAL ;
    PORT
      LAYER M5 ;
        RECT  175.92 0 175.944 0.084 ;
    END
  END lk_wid[22]
  PIN lk_wid[23]
    DIRECTION OUTPUT ;
    USE SIGNAL ;
    PORT
      LAYER M5 ;
        RECT  176.016 0 176.04 0.084 ;
    END
  END lk_wid[23]
  PIN lk_wid[24]
    DIRECTION OUTPUT ;
    USE SIGNAL ;
    PORT
      LAYER M5 ;
        RECT  176.112 0 176.136 0.084 ;
    END
  END lk_wid[24]
  PIN lk_wid[25]
    DIRECTION OUTPUT ;
    USE SIGNAL ;
    PORT
      LAYER M5 ;
        RECT  176.208 0 176.232 0.084 ;
    END
  END lk_wid[25]
  PIN lk_wid[26]
    DIRECTION OUTPUT ;
    USE SIGNAL ;
    PORT
      LAYER M5 ;
        RECT  176.304 0 176.328 0.084 ;
    END
  END lk_wid[26]
  PIN lk_wid[27]
    DIRECTION OUTPUT ;
    USE SIGNAL ;
    PORT
      LAYER M5 ;
        RECT  176.4 0 176.424 0.084 ;
    END
  END lk_wid[27]
  PIN lk_wid[28]
    DIRECTION OUTPUT ;
    USE SIGNAL ;
    PORT
      LAYER M5 ;
        RECT  176.496 0 176.52 0.084 ;
    END
  END lk_wid[28]
  PIN lk_wid[29]
    DIRECTION OUTPUT ;
    USE SIGNAL ;
    PORT
      LAYER M5 ;
        RECT  179.664 0 179.688 0.084 ;
    END
  END lk_wid[29]
  PIN lk_wid[2]
    DIRECTION OUTPUT ;
    USE SIGNAL ;
    PORT
      LAYER M5 ;
        RECT  174 0 174.024 0.084 ;
    END
  END lk_wid[2]
  PIN lk_wid[30]
    DIRECTION OUTPUT ;
    USE SIGNAL ;
    PORT
      LAYER M5 ;
        RECT  179.76 0 179.784 0.084 ;
    END
  END lk_wid[30]
  PIN lk_wid[31]
    DIRECTION OUTPUT ;
    USE SIGNAL ;
    PORT
      LAYER M5 ;
        RECT  179.856 0 179.88 0.084 ;
    END
  END lk_wid[31]
  PIN lk_wid[32]
    DIRECTION OUTPUT ;
    USE SIGNAL ;
    PORT
      LAYER M5 ;
        RECT  179.952 0 179.976 0.084 ;
    END
  END lk_wid[32]
  PIN lk_wid[33]
    DIRECTION OUTPUT ;
    USE SIGNAL ;
    PORT
      LAYER M5 ;
        RECT  180.048 0 180.072 0.084 ;
    END
  END lk_wid[33]
  PIN lk_wid[34]
    DIRECTION OUTPUT ;
    USE SIGNAL ;
    PORT
      LAYER M5 ;
        RECT  180.144 0 180.168 0.084 ;
    END
  END lk_wid[34]
  PIN lk_wid[35]
    DIRECTION OUTPUT ;
    USE SIGNAL ;
    PORT
      LAYER M5 ;
        RECT  180.24 0 180.264 0.084 ;
    END
  END lk_wid[35]
  PIN lk_wid[36]
    DIRECTION OUTPUT ;
    USE SIGNAL ;
    PORT
      LAYER M5 ;
        RECT  180.336 0 180.36 0.084 ;
    END
  END lk_wid[36]
  PIN lk_wid[37]
    DIRECTION OUTPUT ;
    USE SIGNAL ;
    PORT
      LAYER M5 ;
        RECT  180.432 0 180.456 0.084 ;
    END
  END lk_wid[37]
  PIN lk_wid[38]
    DIRECTION OUTPUT ;
    USE SIGNAL ;
    PORT
      LAYER M5 ;
        RECT  180.528 0 180.552 0.084 ;
    END
  END lk_wid[38]
  PIN lk_wid[39]
    DIRECTION OUTPUT ;
    USE SIGNAL ;
    PORT
      LAYER M5 ;
        RECT  180.624 0 180.648 0.084 ;
    END
  END lk_wid[39]
  PIN lk_wid[3]
    DIRECTION OUTPUT ;
    USE SIGNAL ;
    PORT
      LAYER M5 ;
        RECT  174.096 0 174.12 0.084 ;
    END
  END lk_wid[3]
  PIN lk_wid[40]
    DIRECTION OUTPUT ;
    USE SIGNAL ;
    PORT
      LAYER M5 ;
        RECT  180.72 0 180.744 0.084 ;
    END
  END lk_wid[40]
  PIN lk_wid[41]
    DIRECTION OUTPUT ;
    USE SIGNAL ;
    PORT
      LAYER M5 ;
        RECT  180.816 0 180.84 0.084 ;
    END
  END lk_wid[41]
  PIN lk_wid[42]
    DIRECTION OUTPUT ;
    USE SIGNAL ;
    PORT
      LAYER M5 ;
        RECT  180.912 0 180.936 0.084 ;
    END
  END lk_wid[42]
  PIN lk_wid[43]
    DIRECTION OUTPUT ;
    USE SIGNAL ;
    PORT
      LAYER M5 ;
        RECT  181.008 0 181.032 0.084 ;
    END
  END lk_wid[43]
  PIN lk_wid[44]
    DIRECTION OUTPUT ;
    USE SIGNAL ;
    PORT
      LAYER M5 ;
        RECT  181.104 0 181.128 0.084 ;
    END
  END lk_wid[44]
  PIN lk_wid[45]
    DIRECTION OUTPUT ;
    USE SIGNAL ;
    PORT
      LAYER M5 ;
        RECT  181.2 0 181.224 0.084 ;
    END
  END lk_wid[45]
  PIN lk_wid[46]
    DIRECTION OUTPUT ;
    USE SIGNAL ;
    PORT
      LAYER M5 ;
        RECT  181.296 0 181.32 0.084 ;
    END
  END lk_wid[46]
  PIN lk_wid[47]
    DIRECTION OUTPUT ;
    USE SIGNAL ;
    PORT
      LAYER M5 ;
        RECT  181.392 0 181.416 0.084 ;
    END
  END lk_wid[47]
  PIN lk_wid[48]
    DIRECTION OUTPUT ;
    USE SIGNAL ;
    PORT
      LAYER M5 ;
        RECT  181.488 0 181.512 0.084 ;
    END
  END lk_wid[48]
  PIN lk_wid[49]
    DIRECTION OUTPUT ;
    USE SIGNAL ;
    PORT
      LAYER M5 ;
        RECT  181.584 0 181.608 0.084 ;
    END
  END lk_wid[49]
  PIN lk_wid[4]
    DIRECTION OUTPUT ;
    USE SIGNAL ;
    PORT
      LAYER M5 ;
        RECT  174.192 0 174.216 0.084 ;
    END
  END lk_wid[4]
  PIN lk_wid[50]
    DIRECTION OUTPUT ;
    USE SIGNAL ;
    PORT
      LAYER M5 ;
        RECT  181.68 0 181.704 0.084 ;
    END
  END lk_wid[50]
  PIN lk_wid[51]
    DIRECTION OUTPUT ;
    USE SIGNAL ;
    PORT
      LAYER M5 ;
        RECT  181.776 0 181.8 0.084 ;
    END
  END lk_wid[51]
  PIN lk_wid[52]
    DIRECTION OUTPUT ;
    USE SIGNAL ;
    PORT
      LAYER M5 ;
        RECT  181.872 0 181.896 0.084 ;
    END
  END lk_wid[52]
  PIN lk_wid[53]
    DIRECTION OUTPUT ;
    USE SIGNAL ;
    PORT
      LAYER M5 ;
        RECT  181.968 0 181.992 0.084 ;
    END
  END lk_wid[53]
  PIN lk_wid[54]
    DIRECTION OUTPUT ;
    USE SIGNAL ;
    PORT
      LAYER M5 ;
        RECT  182.064 0 182.088 0.084 ;
    END
  END lk_wid[54]
  PIN lk_wid[55]
    DIRECTION OUTPUT ;
    USE SIGNAL ;
    PORT
      LAYER M5 ;
        RECT  182.16 0 182.184 0.084 ;
    END
  END lk_wid[55]
  PIN lk_wid[56]
    DIRECTION OUTPUT ;
    USE SIGNAL ;
    PORT
      LAYER M5 ;
        RECT  182.256 0 182.28 0.084 ;
    END
  END lk_wid[56]
  PIN lk_wid[57]
    DIRECTION OUTPUT ;
    USE SIGNAL ;
    PORT
      LAYER M5 ;
        RECT  182.352 0 182.376 0.084 ;
    END
  END lk_wid[57]
  PIN lk_wid[58]
    DIRECTION OUTPUT ;
    USE SIGNAL ;
    PORT
      LAYER M5 ;
        RECT  182.448 0 182.472 0.084 ;
    END
  END lk_wid[58]
  PIN lk_wid[59]
    DIRECTION OUTPUT ;
    USE SIGNAL ;
    PORT
      LAYER M5 ;
        RECT  182.544 0 182.568 0.084 ;
    END
  END lk_wid[59]
  PIN lk_wid[5]
    DIRECTION OUTPUT ;
    USE SIGNAL ;
    PORT
      LAYER M5 ;
        RECT  174.288 0 174.312 0.084 ;
    END
  END lk_wid[5]
  PIN lk_wid[60]
    DIRECTION OUTPUT ;
    USE SIGNAL ;
    PORT
      LAYER M5 ;
        RECT  182.64 0 182.664 0.084 ;
    END
  END lk_wid[60]
  PIN lk_wid[61]
    DIRECTION OUTPUT ;
    USE SIGNAL ;
    PORT
      LAYER M5 ;
        RECT  163.536 0 163.56 0.084 ;
    END
  END lk_wid[61]
  PIN lk_wid[62]
    DIRECTION OUTPUT ;
    USE SIGNAL ;
    PORT
      LAYER M5 ;
        RECT  163.632 0 163.656 0.084 ;
    END
  END lk_wid[62]
  PIN lk_wid[63]
    DIRECTION OUTPUT ;
    USE SIGNAL ;
    PORT
      LAYER M5 ;
        RECT  163.728 0 163.752 0.084 ;
    END
  END lk_wid[63]
  PIN lk_wid[64]
    DIRECTION OUTPUT ;
    USE SIGNAL ;
    PORT
      LAYER M5 ;
        RECT  163.824 0 163.848 0.084 ;
    END
  END lk_wid[64]
  PIN lk_wid[65]
    DIRECTION OUTPUT ;
    USE SIGNAL ;
    PORT
      LAYER M5 ;
        RECT  163.92 0 163.944 0.084 ;
    END
  END lk_wid[65]
  PIN lk_wid[66]
    DIRECTION OUTPUT ;
    USE SIGNAL ;
    PORT
      LAYER M5 ;
        RECT  164.016 0 164.04 0.084 ;
    END
  END lk_wid[66]
  PIN lk_wid[67]
    DIRECTION OUTPUT ;
    USE SIGNAL ;
    PORT
      LAYER M5 ;
        RECT  164.112 0 164.136 0.084 ;
    END
  END lk_wid[67]
  PIN lk_wid[6]
    DIRECTION OUTPUT ;
    USE SIGNAL ;
    PORT
      LAYER M5 ;
        RECT  174.384 0 174.408 0.084 ;
    END
  END lk_wid[6]
  PIN lk_wid[7]
    DIRECTION OUTPUT ;
    USE SIGNAL ;
    PORT
      LAYER M5 ;
        RECT  174.48 0 174.504 0.084 ;
    END
  END lk_wid[7]
  PIN lk_wid[8]
    DIRECTION OUTPUT ;
    USE SIGNAL ;
    PORT
      LAYER M5 ;
        RECT  174.576 0 174.6 0.084 ;
    END
  END lk_wid[8]
  PIN lk_wid[9]
    DIRECTION OUTPUT ;
    USE SIGNAL ;
    PORT
      LAYER M5 ;
        RECT  174.672 0 174.696 0.084 ;
    END
  END lk_wid[9]
  PIN lk_wv
    DIRECTION OUTPUT ;
    USE SIGNAL ;
    PORT
      LAYER M5 ;
        RECT  164.208 0 164.232 0.084 ;
    END
  END lk_wv
  PIN perr_o[0]
    DIRECTION OUTPUT ;
    USE SIGNAL ;
    PORT
      LAYER M4 ;
        RECT  328.236 22.032 328.32 22.056 ;
    END
  END perr_o[0]
  PIN perr_o[1]
    DIRECTION OUTPUT ;
    USE SIGNAL ;
    PORT
      LAYER M4 ;
        RECT  328.236 22.128 328.32 22.152 ;
    END
  END perr_o[1]
  PIN perr_o[2]
    DIRECTION OUTPUT ;
    USE SIGNAL ;
    PORT
      LAYER M4 ;
        RECT  328.236 22.224 328.32 22.248 ;
    END
  END perr_o[2]
  PIN perr_o[3]
    DIRECTION OUTPUT ;
    USE SIGNAL ;
    PORT
      LAYER M4 ;
        RECT  328.236 22.32 328.32 22.344 ;
    END
  END perr_o[3]
  PIN perr_o[4]
    DIRECTION OUTPUT ;
    USE SIGNAL ;
    PORT
      LAYER M4 ;
        RECT  328.236 22.416 328.32 22.44 ;
    END
  END perr_o[4]
  PIN perr_o[5]
    DIRECTION OUTPUT ;
    USE SIGNAL ;
    PORT
      LAYER M4 ;
        RECT  328.236 22.512 328.32 22.536 ;
    END
  END perr_o[5]
  PIN perr_o[6]
    DIRECTION OUTPUT ;
    USE SIGNAL ;
    PORT
      LAYER M4 ;
        RECT  328.236 22.608 328.32 22.632 ;
    END
  END perr_o[6]
  PIN perr_o[7]
    DIRECTION OUTPUT ;
    USE SIGNAL ;
    PORT
      LAYER M4 ;
        RECT  328.236 22.704 328.32 22.728 ;
    END
  END perr_o[7]
  PIN rdy_o[0]
    DIRECTION OUTPUT ;
    USE SIGNAL ;
    PORT
      LAYER M4 ;
        RECT  328.236 22.8 328.32 22.824 ;
    END
  END rdy_o[0]
  PIN rdy_o[1]
    DIRECTION OUTPUT ;
    USE SIGNAL ;
    PORT
      LAYER M4 ;
        RECT  328.236 22.896 328.32 22.92 ;
    END
  END rdy_o[1]
  PIN rdy_o[2]
    DIRECTION OUTPUT ;
    USE SIGNAL ;
    PORT
      LAYER M4 ;
        RECT  328.236 22.992 328.32 23.016 ;
    END
  END rdy_o[2]
  PIN rdy_o[3]
    DIRECTION OUTPUT ;
    USE SIGNAL ;
    PORT
      LAYER M4 ;
        RECT  328.236 23.088 328.32 23.112 ;
    END
  END rdy_o[3]
  PIN rdy_o[4]
    DIRECTION OUTPUT ;
    USE SIGNAL ;
    PORT
      LAYER M4 ;
        RECT  328.236 23.184 328.32 23.208 ;
    END
  END rdy_o[4]
  PIN rdy_o[5]
    DIRECTION OUTPUT ;
    USE SIGNAL ;
    PORT
      LAYER M4 ;
        RECT  328.236 23.28 328.32 23.304 ;
    END
  END rdy_o[5]
  PIN rdy_o[6]
    DIRECTION OUTPUT ;
    USE SIGNAL ;
    PORT
      LAYER M4 ;
        RECT  328.236 23.376 328.32 23.4 ;
    END
  END rdy_o[6]
  PIN rdy_o[7]
    DIRECTION OUTPUT ;
    USE SIGNAL ;
    PORT
      LAYER M4 ;
        RECT  328.236 23.472 328.32 23.496 ;
    END
  END rdy_o[7]
  PIN rn_lk
    DIRECTION OUTPUT ;
    USE SIGNAL ;
    PORT
      LAYER M5 ;
        RECT  164.304 0 164.328 0.084 ;
    END
  END rn_lk
  PIN rn_sk
    DIRECTION OUTPUT ;
    USE SIGNAL ;
    PORT
      LAYER M4 ;
        RECT  0 23.568 0.084 23.592 ;
    END
  END rn_sk
  PIN rst
    DIRECTION INPUT ;
    USE SIGNAL ;
    PORT
      LAYER M5 ;
        RECT  165.84 47.436 165.864 47.52 ;
    END
  END rst
  PIN s_perr[0]
    DIRECTION INPUT ;
    USE SIGNAL ;
    PORT
      LAYER M4 ;
        RECT  0 23.664 0.084 23.688 ;
    END
  END s_perr[0]
  PIN s_perr[1]
    DIRECTION INPUT ;
    USE SIGNAL ;
    PORT
      LAYER M4 ;
        RECT  0 23.76 0.084 23.784 ;
    END
  END s_perr[1]
  PIN s_perr[2]
    DIRECTION INPUT ;
    USE SIGNAL ;
    PORT
      LAYER M4 ;
        RECT  0 23.856 0.084 23.88 ;
    END
  END s_perr[2]
  PIN s_perr[3]
    DIRECTION INPUT ;
    USE SIGNAL ;
    PORT
      LAYER M4 ;
        RECT  0 23.952 0.084 23.976 ;
    END
  END s_perr[3]
  PIN s_perr[4]
    DIRECTION INPUT ;
    USE SIGNAL ;
    PORT
      LAYER M4 ;
        RECT  0 24.048 0.084 24.072 ;
    END
  END s_perr[4]
  PIN s_perr[5]
    DIRECTION INPUT ;
    USE SIGNAL ;
    PORT
      LAYER M4 ;
        RECT  0 24.144 0.084 24.168 ;
    END
  END s_perr[5]
  PIN s_perr[6]
    DIRECTION INPUT ;
    USE SIGNAL ;
    PORT
      LAYER M4 ;
        RECT  0 24.24 0.084 24.264 ;
    END
  END s_perr[6]
  PIN s_perr[7]
    DIRECTION INPUT ;
    USE SIGNAL ;
    PORT
      LAYER M4 ;
        RECT  0 24.336 0.084 24.36 ;
    END
  END s_perr[7]
  PIN s_rdy[0]
    DIRECTION INPUT ;
    USE SIGNAL ;
    PORT
      LAYER M4 ;
        RECT  0 24.432 0.084 24.456 ;
    END
  END s_rdy[0]
  PIN s_rdy[1]
    DIRECTION INPUT ;
    USE SIGNAL ;
    PORT
      LAYER M4 ;
        RECT  0 24.528 0.084 24.552 ;
    END
  END s_rdy[1]
  PIN s_rdy[2]
    DIRECTION INPUT ;
    USE SIGNAL ;
    PORT
      LAYER M4 ;
        RECT  0 24.624 0.084 24.648 ;
    END
  END s_rdy[2]
  PIN s_rdy[3]
    DIRECTION INPUT ;
    USE SIGNAL ;
    PORT
      LAYER M4 ;
        RECT  0 24.72 0.084 24.744 ;
    END
  END s_rdy[3]
  PIN s_rdy[4]
    DIRECTION INPUT ;
    USE SIGNAL ;
    PORT
      LAYER M4 ;
        RECT  0 24.816 0.084 24.84 ;
    END
  END s_rdy[4]
  PIN s_rdy[5]
    DIRECTION INPUT ;
    USE SIGNAL ;
    PORT
      LAYER M4 ;
        RECT  0 24.912 0.084 24.936 ;
    END
  END s_rdy[5]
  PIN s_rdy[6]
    DIRECTION INPUT ;
    USE SIGNAL ;
    PORT
      LAYER M4 ;
        RECT  0 25.008 0.084 25.032 ;
    END
  END s_rdy[6]
  PIN s_rdy[7]
    DIRECTION INPUT ;
    USE SIGNAL ;
    PORT
      LAYER M4 ;
        RECT  0 25.104 0.084 25.128 ;
    END
  END s_rdy[7]
  PIN t_ag[0]
    DIRECTION OUTPUT ;
    USE SIGNAL ;
    PORT
      LAYER M5 ;
        RECT  165.936 47.436 165.96 47.52 ;
    END
  END t_ag[0]
  PIN t_ag[100]
    DIRECTION OUTPUT ;
    USE SIGNAL ;
    PORT
      LAYER M5 ;
        RECT  160.176 47.436 160.2 47.52 ;
    END
  END t_ag[100]
  PIN t_ag[101]
    DIRECTION OUTPUT ;
    USE SIGNAL ;
    PORT
      LAYER M5 ;
        RECT  160.272 47.436 160.296 47.52 ;
    END
  END t_ag[101]
  PIN t_ag[102]
    DIRECTION OUTPUT ;
    USE SIGNAL ;
    PORT
      LAYER M5 ;
        RECT  160.368 47.436 160.392 47.52 ;
    END
  END t_ag[102]
  PIN t_ag[103]
    DIRECTION OUTPUT ;
    USE SIGNAL ;
    PORT
      LAYER M5 ;
        RECT  160.464 47.436 160.488 47.52 ;
    END
  END t_ag[103]
  PIN t_ag[104]
    DIRECTION OUTPUT ;
    USE SIGNAL ;
    PORT
      LAYER M5 ;
        RECT  160.56 47.436 160.584 47.52 ;
    END
  END t_ag[104]
  PIN t_ag[105]
    DIRECTION OUTPUT ;
    USE SIGNAL ;
    PORT
      LAYER M5 ;
        RECT  160.656 47.436 160.68 47.52 ;
    END
  END t_ag[105]
  PIN t_ag[106]
    DIRECTION OUTPUT ;
    USE SIGNAL ;
    PORT
      LAYER M5 ;
        RECT  160.752 47.436 160.776 47.52 ;
    END
  END t_ag[106]
  PIN t_ag[107]
    DIRECTION OUTPUT ;
    USE SIGNAL ;
    PORT
      LAYER M5 ;
        RECT  160.848 47.436 160.872 47.52 ;
    END
  END t_ag[107]
  PIN t_ag[108]
    DIRECTION OUTPUT ;
    USE SIGNAL ;
    PORT
      LAYER M5 ;
        RECT  160.944 47.436 160.968 47.52 ;
    END
  END t_ag[108]
  PIN t_ag[109]
    DIRECTION OUTPUT ;
    USE SIGNAL ;
    PORT
      LAYER M5 ;
        RECT  161.04 47.436 161.064 47.52 ;
    END
  END t_ag[109]
  PIN t_ag[10]
    DIRECTION OUTPUT ;
    USE SIGNAL ;
    PORT
      LAYER M5 ;
        RECT  166.896 47.436 166.92 47.52 ;
    END
  END t_ag[10]
  PIN t_ag[110]
    DIRECTION OUTPUT ;
    USE SIGNAL ;
    PORT
      LAYER M5 ;
        RECT  161.136 47.436 161.16 47.52 ;
    END
  END t_ag[110]
  PIN t_ag[111]
    DIRECTION OUTPUT ;
    USE SIGNAL ;
    PORT
      LAYER M5 ;
        RECT  161.232 47.436 161.256 47.52 ;
    END
  END t_ag[111]
  PIN t_ag[112]
    DIRECTION OUTPUT ;
    USE SIGNAL ;
    PORT
      LAYER M5 ;
        RECT  161.328 47.436 161.352 47.52 ;
    END
  END t_ag[112]
  PIN t_ag[113]
    DIRECTION OUTPUT ;
    USE SIGNAL ;
    PORT
      LAYER M5 ;
        RECT  161.424 47.436 161.448 47.52 ;
    END
  END t_ag[113]
  PIN t_ag[114]
    DIRECTION OUTPUT ;
    USE SIGNAL ;
    PORT
      LAYER M5 ;
        RECT  161.52 47.436 161.544 47.52 ;
    END
  END t_ag[114]
  PIN t_ag[115]
    DIRECTION OUTPUT ;
    USE SIGNAL ;
    PORT
      LAYER M5 ;
        RECT  161.616 47.436 161.64 47.52 ;
    END
  END t_ag[115]
  PIN t_ag[116]
    DIRECTION OUTPUT ;
    USE SIGNAL ;
    PORT
      LAYER M5 ;
        RECT  139.44 47.436 139.464 47.52 ;
    END
  END t_ag[116]
  PIN t_ag[117]
    DIRECTION OUTPUT ;
    USE SIGNAL ;
    PORT
      LAYER M5 ;
        RECT  139.536 47.436 139.56 47.52 ;
    END
  END t_ag[117]
  PIN t_ag[118]
    DIRECTION OUTPUT ;
    USE SIGNAL ;
    PORT
      LAYER M5 ;
        RECT  139.632 47.436 139.656 47.52 ;
    END
  END t_ag[118]
  PIN t_ag[119]
    DIRECTION OUTPUT ;
    USE SIGNAL ;
    PORT
      LAYER M5 ;
        RECT  139.728 47.436 139.752 47.52 ;
    END
  END t_ag[119]
  PIN t_ag[11]
    DIRECTION OUTPUT ;
    USE SIGNAL ;
    PORT
      LAYER M5 ;
        RECT  166.992 47.436 167.016 47.52 ;
    END
  END t_ag[11]
  PIN t_ag[120]
    DIRECTION OUTPUT ;
    USE SIGNAL ;
    PORT
      LAYER M5 ;
        RECT  139.824 47.436 139.848 47.52 ;
    END
  END t_ag[120]
  PIN t_ag[121]
    DIRECTION OUTPUT ;
    USE SIGNAL ;
    PORT
      LAYER M5 ;
        RECT  139.92 47.436 139.944 47.52 ;
    END
  END t_ag[121]
  PIN t_ag[122]
    DIRECTION OUTPUT ;
    USE SIGNAL ;
    PORT
      LAYER M5 ;
        RECT  140.016 47.436 140.04 47.52 ;
    END
  END t_ag[122]
  PIN t_ag[123]
    DIRECTION OUTPUT ;
    USE SIGNAL ;
    PORT
      LAYER M5 ;
        RECT  140.112 47.436 140.136 47.52 ;
    END
  END t_ag[123]
  PIN t_ag[124]
    DIRECTION OUTPUT ;
    USE SIGNAL ;
    PORT
      LAYER M5 ;
        RECT  140.208 47.436 140.232 47.52 ;
    END
  END t_ag[124]
  PIN t_ag[125]
    DIRECTION OUTPUT ;
    USE SIGNAL ;
    PORT
      LAYER M5 ;
        RECT  140.304 47.436 140.328 47.52 ;
    END
  END t_ag[125]
  PIN t_ag[126]
    DIRECTION OUTPUT ;
    USE SIGNAL ;
    PORT
      LAYER M5 ;
        RECT  140.4 47.436 140.424 47.52 ;
    END
  END t_ag[126]
  PIN t_ag[127]
    DIRECTION OUTPUT ;
    USE SIGNAL ;
    PORT
      LAYER M5 ;
        RECT  140.496 47.436 140.52 47.52 ;
    END
  END t_ag[127]
  PIN t_ag[128]
    DIRECTION OUTPUT ;
    USE SIGNAL ;
    PORT
      LAYER M5 ;
        RECT  140.592 47.436 140.616 47.52 ;
    END
  END t_ag[128]
  PIN t_ag[129]
    DIRECTION OUTPUT ;
    USE SIGNAL ;
    PORT
      LAYER M5 ;
        RECT  140.688 47.436 140.712 47.52 ;
    END
  END t_ag[129]
  PIN t_ag[12]
    DIRECTION OUTPUT ;
    USE SIGNAL ;
    PORT
      LAYER M5 ;
        RECT  167.088 47.436 167.112 47.52 ;
    END
  END t_ag[12]
  PIN t_ag[130]
    DIRECTION OUTPUT ;
    USE SIGNAL ;
    PORT
      LAYER M5 ;
        RECT  140.784 47.436 140.808 47.52 ;
    END
  END t_ag[130]
  PIN t_ag[131]
    DIRECTION OUTPUT ;
    USE SIGNAL ;
    PORT
      LAYER M5 ;
        RECT  140.88 47.436 140.904 47.52 ;
    END
  END t_ag[131]
  PIN t_ag[132]
    DIRECTION OUTPUT ;
    USE SIGNAL ;
    PORT
      LAYER M5 ;
        RECT  140.976 47.436 141 47.52 ;
    END
  END t_ag[132]
  PIN t_ag[133]
    DIRECTION OUTPUT ;
    USE SIGNAL ;
    PORT
      LAYER M5 ;
        RECT  141.072 47.436 141.096 47.52 ;
    END
  END t_ag[133]
  PIN t_ag[134]
    DIRECTION OUTPUT ;
    USE SIGNAL ;
    PORT
      LAYER M5 ;
        RECT  141.168 47.436 141.192 47.52 ;
    END
  END t_ag[134]
  PIN t_ag[135]
    DIRECTION OUTPUT ;
    USE SIGNAL ;
    PORT
      LAYER M5 ;
        RECT  141.264 47.436 141.288 47.52 ;
    END
  END t_ag[135]
  PIN t_ag[136]
    DIRECTION OUTPUT ;
    USE SIGNAL ;
    PORT
      LAYER M5 ;
        RECT  141.36 47.436 141.384 47.52 ;
    END
  END t_ag[136]
  PIN t_ag[137]
    DIRECTION OUTPUT ;
    USE SIGNAL ;
    PORT
      LAYER M5 ;
        RECT  141.456 47.436 141.48 47.52 ;
    END
  END t_ag[137]
  PIN t_ag[138]
    DIRECTION OUTPUT ;
    USE SIGNAL ;
    PORT
      LAYER M5 ;
        RECT  141.552 47.436 141.576 47.52 ;
    END
  END t_ag[138]
  PIN t_ag[139]
    DIRECTION OUTPUT ;
    USE SIGNAL ;
    PORT
      LAYER M5 ;
        RECT  141.648 47.436 141.672 47.52 ;
    END
  END t_ag[139]
  PIN t_ag[13]
    DIRECTION OUTPUT ;
    USE SIGNAL ;
    PORT
      LAYER M5 ;
        RECT  167.184 47.436 167.208 47.52 ;
    END
  END t_ag[13]
  PIN t_ag[140]
    DIRECTION OUTPUT ;
    USE SIGNAL ;
    PORT
      LAYER M5 ;
        RECT  141.744 47.436 141.768 47.52 ;
    END
  END t_ag[140]
  PIN t_ag[141]
    DIRECTION OUTPUT ;
    USE SIGNAL ;
    PORT
      LAYER M5 ;
        RECT  141.84 47.436 141.864 47.52 ;
    END
  END t_ag[141]
  PIN t_ag[142]
    DIRECTION OUTPUT ;
    USE SIGNAL ;
    PORT
      LAYER M5 ;
        RECT  141.936 47.436 141.96 47.52 ;
    END
  END t_ag[142]
  PIN t_ag[143]
    DIRECTION OUTPUT ;
    USE SIGNAL ;
    PORT
      LAYER M5 ;
        RECT  142.032 47.436 142.056 47.52 ;
    END
  END t_ag[143]
  PIN t_ag[144]
    DIRECTION OUTPUT ;
    USE SIGNAL ;
    PORT
      LAYER M5 ;
        RECT  142.128 47.436 142.152 47.52 ;
    END
  END t_ag[144]
  PIN t_ag[145]
    DIRECTION OUTPUT ;
    USE SIGNAL ;
    PORT
      LAYER M5 ;
        RECT  142.224 47.436 142.248 47.52 ;
    END
  END t_ag[145]
  PIN t_ag[146]
    DIRECTION OUTPUT ;
    USE SIGNAL ;
    PORT
      LAYER M5 ;
        RECT  142.32 47.436 142.344 47.52 ;
    END
  END t_ag[146]
  PIN t_ag[147]
    DIRECTION OUTPUT ;
    USE SIGNAL ;
    PORT
      LAYER M5 ;
        RECT  142.416 47.436 142.44 47.52 ;
    END
  END t_ag[147]
  PIN t_ag[148]
    DIRECTION OUTPUT ;
    USE SIGNAL ;
    PORT
      LAYER M5 ;
        RECT  161.712 47.436 161.736 47.52 ;
    END
  END t_ag[148]
  PIN t_ag[149]
    DIRECTION OUTPUT ;
    USE SIGNAL ;
    PORT
      LAYER M5 ;
        RECT  161.808 47.436 161.832 47.52 ;
    END
  END t_ag[149]
  PIN t_ag[14]
    DIRECTION OUTPUT ;
    USE SIGNAL ;
    PORT
      LAYER M5 ;
        RECT  167.28 47.436 167.304 47.52 ;
    END
  END t_ag[14]
  PIN t_ag[150]
    DIRECTION OUTPUT ;
    USE SIGNAL ;
    PORT
      LAYER M5 ;
        RECT  161.904 47.436 161.928 47.52 ;
    END
  END t_ag[150]
  PIN t_ag[151]
    DIRECTION OUTPUT ;
    USE SIGNAL ;
    PORT
      LAYER M5 ;
        RECT  162 47.436 162.024 47.52 ;
    END
  END t_ag[151]
  PIN t_ag[152]
    DIRECTION OUTPUT ;
    USE SIGNAL ;
    PORT
      LAYER M5 ;
        RECT  162.096 47.436 162.12 47.52 ;
    END
  END t_ag[152]
  PIN t_ag[153]
    DIRECTION OUTPUT ;
    USE SIGNAL ;
    PORT
      LAYER M5 ;
        RECT  162.192 47.436 162.216 47.52 ;
    END
  END t_ag[153]
  PIN t_ag[154]
    DIRECTION OUTPUT ;
    USE SIGNAL ;
    PORT
      LAYER M5 ;
        RECT  162.288 47.436 162.312 47.52 ;
    END
  END t_ag[154]
  PIN t_ag[155]
    DIRECTION OUTPUT ;
    USE SIGNAL ;
    PORT
      LAYER M5 ;
        RECT  162.384 47.436 162.408 47.52 ;
    END
  END t_ag[155]
  PIN t_ag[156]
    DIRECTION OUTPUT ;
    USE SIGNAL ;
    PORT
      LAYER M5 ;
        RECT  162.48 47.436 162.504 47.52 ;
    END
  END t_ag[156]
  PIN t_ag[157]
    DIRECTION OUTPUT ;
    USE SIGNAL ;
    PORT
      LAYER M5 ;
        RECT  162.576 47.436 162.6 47.52 ;
    END
  END t_ag[157]
  PIN t_ag[158]
    DIRECTION OUTPUT ;
    USE SIGNAL ;
    PORT
      LAYER M5 ;
        RECT  162.672 47.436 162.696 47.52 ;
    END
  END t_ag[158]
  PIN t_ag[159]
    DIRECTION OUTPUT ;
    USE SIGNAL ;
    PORT
      LAYER M5 ;
        RECT  162.768 47.436 162.792 47.52 ;
    END
  END t_ag[159]
  PIN t_ag[15]
    DIRECTION OUTPUT ;
    USE SIGNAL ;
    PORT
      LAYER M5 ;
        RECT  167.376 47.436 167.4 47.52 ;
    END
  END t_ag[15]
  PIN t_ag[160]
    DIRECTION OUTPUT ;
    USE SIGNAL ;
    PORT
      LAYER M5 ;
        RECT  162.864 47.436 162.888 47.52 ;
    END
  END t_ag[160]
  PIN t_ag[161]
    DIRECTION OUTPUT ;
    USE SIGNAL ;
    PORT
      LAYER M5 ;
        RECT  162.96 47.436 162.984 47.52 ;
    END
  END t_ag[161]
  PIN t_ag[162]
    DIRECTION OUTPUT ;
    USE SIGNAL ;
    PORT
      LAYER M5 ;
        RECT  163.056 47.436 163.08 47.52 ;
    END
  END t_ag[162]
  PIN t_ag[163]
    DIRECTION OUTPUT ;
    USE SIGNAL ;
    PORT
      LAYER M5 ;
        RECT  163.152 47.436 163.176 47.52 ;
    END
  END t_ag[163]
  PIN t_ag[164]
    DIRECTION OUTPUT ;
    USE SIGNAL ;
    PORT
      LAYER M5 ;
        RECT  163.248 47.436 163.272 47.52 ;
    END
  END t_ag[164]
  PIN t_ag[165]
    DIRECTION OUTPUT ;
    USE SIGNAL ;
    PORT
      LAYER M5 ;
        RECT  163.344 47.436 163.368 47.52 ;
    END
  END t_ag[165]
  PIN t_ag[166]
    DIRECTION OUTPUT ;
    USE SIGNAL ;
    PORT
      LAYER M5 ;
        RECT  163.44 47.436 163.464 47.52 ;
    END
  END t_ag[166]
  PIN t_ag[167]
    DIRECTION OUTPUT ;
    USE SIGNAL ;
    PORT
      LAYER M5 ;
        RECT  163.536 47.436 163.56 47.52 ;
    END
  END t_ag[167]
  PIN t_ag[168]
    DIRECTION OUTPUT ;
    USE SIGNAL ;
    PORT
      LAYER M5 ;
        RECT  163.632 47.436 163.656 47.52 ;
    END
  END t_ag[168]
  PIN t_ag[169]
    DIRECTION OUTPUT ;
    USE SIGNAL ;
    PORT
      LAYER M5 ;
        RECT  163.728 47.436 163.752 47.52 ;
    END
  END t_ag[169]
  PIN t_ag[16]
    DIRECTION OUTPUT ;
    USE SIGNAL ;
    PORT
      LAYER M5 ;
        RECT  167.472 47.436 167.496 47.52 ;
    END
  END t_ag[16]
  PIN t_ag[170]
    DIRECTION OUTPUT ;
    USE SIGNAL ;
    PORT
      LAYER M5 ;
        RECT  163.824 47.436 163.848 47.52 ;
    END
  END t_ag[170]
  PIN t_ag[171]
    DIRECTION OUTPUT ;
    USE SIGNAL ;
    PORT
      LAYER M5 ;
        RECT  163.92 47.436 163.944 47.52 ;
    END
  END t_ag[171]
  PIN t_ag[172]
    DIRECTION OUTPUT ;
    USE SIGNAL ;
    PORT
      LAYER M5 ;
        RECT  164.016 47.436 164.04 47.52 ;
    END
  END t_ag[172]
  PIN t_ag[173]
    DIRECTION OUTPUT ;
    USE SIGNAL ;
    PORT
      LAYER M5 ;
        RECT  164.112 47.436 164.136 47.52 ;
    END
  END t_ag[173]
  PIN t_ag[174]
    DIRECTION OUTPUT ;
    USE SIGNAL ;
    PORT
      LAYER M5 ;
        RECT  164.208 47.436 164.232 47.52 ;
    END
  END t_ag[174]
  PIN t_ag[175]
    DIRECTION OUTPUT ;
    USE SIGNAL ;
    PORT
      LAYER M5 ;
        RECT  164.304 47.436 164.328 47.52 ;
    END
  END t_ag[175]
  PIN t_ag[176]
    DIRECTION OUTPUT ;
    USE SIGNAL ;
    PORT
      LAYER M5 ;
        RECT  164.4 47.436 164.424 47.52 ;
    END
  END t_ag[176]
  PIN t_ag[177]
    DIRECTION OUTPUT ;
    USE SIGNAL ;
    PORT
      LAYER M5 ;
        RECT  164.496 47.436 164.52 47.52 ;
    END
  END t_ag[177]
  PIN t_ag[178]
    DIRECTION OUTPUT ;
    USE SIGNAL ;
    PORT
      LAYER M5 ;
        RECT  164.592 47.436 164.616 47.52 ;
    END
  END t_ag[178]
  PIN t_ag[179]
    DIRECTION OUTPUT ;
    USE SIGNAL ;
    PORT
      LAYER M5 ;
        RECT  164.688 47.436 164.712 47.52 ;
    END
  END t_ag[179]
  PIN t_ag[17]
    DIRECTION OUTPUT ;
    USE SIGNAL ;
    PORT
      LAYER M5 ;
        RECT  167.568 47.436 167.592 47.52 ;
    END
  END t_ag[17]
  PIN t_ag[180]
    DIRECTION OUTPUT ;
    USE SIGNAL ;
    PORT
      LAYER M5 ;
        RECT  145.584 47.436 145.608 47.52 ;
    END
  END t_ag[180]
  PIN t_ag[181]
    DIRECTION OUTPUT ;
    USE SIGNAL ;
    PORT
      LAYER M5 ;
        RECT  145.68 47.436 145.704 47.52 ;
    END
  END t_ag[181]
  PIN t_ag[182]
    DIRECTION OUTPUT ;
    USE SIGNAL ;
    PORT
      LAYER M5 ;
        RECT  145.776 47.436 145.8 47.52 ;
    END
  END t_ag[182]
  PIN t_ag[183]
    DIRECTION OUTPUT ;
    USE SIGNAL ;
    PORT
      LAYER M5 ;
        RECT  145.872 47.436 145.896 47.52 ;
    END
  END t_ag[183]
  PIN t_ag[184]
    DIRECTION OUTPUT ;
    USE SIGNAL ;
    PORT
      LAYER M5 ;
        RECT  145.968 47.436 145.992 47.52 ;
    END
  END t_ag[184]
  PIN t_ag[185]
    DIRECTION OUTPUT ;
    USE SIGNAL ;
    PORT
      LAYER M5 ;
        RECT  146.064 47.436 146.088 47.52 ;
    END
  END t_ag[185]
  PIN t_ag[186]
    DIRECTION OUTPUT ;
    USE SIGNAL ;
    PORT
      LAYER M5 ;
        RECT  146.16 47.436 146.184 47.52 ;
    END
  END t_ag[186]
  PIN t_ag[187]
    DIRECTION OUTPUT ;
    USE SIGNAL ;
    PORT
      LAYER M5 ;
        RECT  146.256 47.436 146.28 47.52 ;
    END
  END t_ag[187]
  PIN t_ag[188]
    DIRECTION OUTPUT ;
    USE SIGNAL ;
    PORT
      LAYER M5 ;
        RECT  146.352 47.436 146.376 47.52 ;
    END
  END t_ag[188]
  PIN t_ag[189]
    DIRECTION OUTPUT ;
    USE SIGNAL ;
    PORT
      LAYER M5 ;
        RECT  146.448 47.436 146.472 47.52 ;
    END
  END t_ag[189]
  PIN t_ag[18]
    DIRECTION OUTPUT ;
    USE SIGNAL ;
    PORT
      LAYER M5 ;
        RECT  167.664 47.436 167.688 47.52 ;
    END
  END t_ag[18]
  PIN t_ag[190]
    DIRECTION OUTPUT ;
    USE SIGNAL ;
    PORT
      LAYER M5 ;
        RECT  146.544 47.436 146.568 47.52 ;
    END
  END t_ag[190]
  PIN t_ag[191]
    DIRECTION OUTPUT ;
    USE SIGNAL ;
    PORT
      LAYER M5 ;
        RECT  146.64 47.436 146.664 47.52 ;
    END
  END t_ag[191]
  PIN t_ag[192]
    DIRECTION OUTPUT ;
    USE SIGNAL ;
    PORT
      LAYER M5 ;
        RECT  146.736 47.436 146.76 47.52 ;
    END
  END t_ag[192]
  PIN t_ag[193]
    DIRECTION OUTPUT ;
    USE SIGNAL ;
    PORT
      LAYER M5 ;
        RECT  146.832 47.436 146.856 47.52 ;
    END
  END t_ag[193]
  PIN t_ag[194]
    DIRECTION OUTPUT ;
    USE SIGNAL ;
    PORT
      LAYER M5 ;
        RECT  146.928 47.436 146.952 47.52 ;
    END
  END t_ag[194]
  PIN t_ag[195]
    DIRECTION OUTPUT ;
    USE SIGNAL ;
    PORT
      LAYER M5 ;
        RECT  147.024 47.436 147.048 47.52 ;
    END
  END t_ag[195]
  PIN t_ag[196]
    DIRECTION OUTPUT ;
    USE SIGNAL ;
    PORT
      LAYER M5 ;
        RECT  147.12 47.436 147.144 47.52 ;
    END
  END t_ag[196]
  PIN t_ag[197]
    DIRECTION OUTPUT ;
    USE SIGNAL ;
    PORT
      LAYER M5 ;
        RECT  147.216 47.436 147.24 47.52 ;
    END
  END t_ag[197]
  PIN t_ag[198]
    DIRECTION OUTPUT ;
    USE SIGNAL ;
    PORT
      LAYER M5 ;
        RECT  147.312 47.436 147.336 47.52 ;
    END
  END t_ag[198]
  PIN t_ag[199]
    DIRECTION OUTPUT ;
    USE SIGNAL ;
    PORT
      LAYER M5 ;
        RECT  147.408 47.436 147.432 47.52 ;
    END
  END t_ag[199]
  PIN t_ag[19]
    DIRECTION OUTPUT ;
    USE SIGNAL ;
    PORT
      LAYER M5 ;
        RECT  167.76 47.436 167.784 47.52 ;
    END
  END t_ag[19]
  PIN t_ag[1]
    DIRECTION OUTPUT ;
    USE SIGNAL ;
    PORT
      LAYER M5 ;
        RECT  166.032 47.436 166.056 47.52 ;
    END
  END t_ag[1]
  PIN t_ag[200]
    DIRECTION OUTPUT ;
    USE SIGNAL ;
    PORT
      LAYER M5 ;
        RECT  147.504 47.436 147.528 47.52 ;
    END
  END t_ag[200]
  PIN t_ag[201]
    DIRECTION OUTPUT ;
    USE SIGNAL ;
    PORT
      LAYER M5 ;
        RECT  147.6 47.436 147.624 47.52 ;
    END
  END t_ag[201]
  PIN t_ag[202]
    DIRECTION OUTPUT ;
    USE SIGNAL ;
    PORT
      LAYER M5 ;
        RECT  147.696 47.436 147.72 47.52 ;
    END
  END t_ag[202]
  PIN t_ag[203]
    DIRECTION OUTPUT ;
    USE SIGNAL ;
    PORT
      LAYER M5 ;
        RECT  147.792 47.436 147.816 47.52 ;
    END
  END t_ag[203]
  PIN t_ag[204]
    DIRECTION OUTPUT ;
    USE SIGNAL ;
    PORT
      LAYER M5 ;
        RECT  147.888 47.436 147.912 47.52 ;
    END
  END t_ag[204]
  PIN t_ag[205]
    DIRECTION OUTPUT ;
    USE SIGNAL ;
    PORT
      LAYER M5 ;
        RECT  147.984 47.436 148.008 47.52 ;
    END
  END t_ag[205]
  PIN t_ag[206]
    DIRECTION OUTPUT ;
    USE SIGNAL ;
    PORT
      LAYER M5 ;
        RECT  148.08 47.436 148.104 47.52 ;
    END
  END t_ag[206]
  PIN t_ag[207]
    DIRECTION OUTPUT ;
    USE SIGNAL ;
    PORT
      LAYER M5 ;
        RECT  148.176 47.436 148.2 47.52 ;
    END
  END t_ag[207]
  PIN t_ag[208]
    DIRECTION OUTPUT ;
    USE SIGNAL ;
    PORT
      LAYER M5 ;
        RECT  148.272 47.436 148.296 47.52 ;
    END
  END t_ag[208]
  PIN t_ag[209]
    DIRECTION OUTPUT ;
    USE SIGNAL ;
    PORT
      LAYER M5 ;
        RECT  148.368 47.436 148.392 47.52 ;
    END
  END t_ag[209]
  PIN t_ag[20]
    DIRECTION OUTPUT ;
    USE SIGNAL ;
    PORT
      LAYER M5 ;
        RECT  151.728 47.436 151.752 47.52 ;
    END
  END t_ag[20]
  PIN t_ag[210]
    DIRECTION OUTPUT ;
    USE SIGNAL ;
    PORT
      LAYER M5 ;
        RECT  148.464 47.436 148.488 47.52 ;
    END
  END t_ag[210]
  PIN t_ag[211]
    DIRECTION OUTPUT ;
    USE SIGNAL ;
    PORT
      LAYER M5 ;
        RECT  148.56 47.436 148.584 47.52 ;
    END
  END t_ag[211]
  PIN t_ag[212]
    DIRECTION OUTPUT ;
    USE SIGNAL ;
    PORT
      LAYER M5 ;
        RECT  142.512 47.436 142.536 47.52 ;
    END
  END t_ag[212]
  PIN t_ag[213]
    DIRECTION OUTPUT ;
    USE SIGNAL ;
    PORT
      LAYER M5 ;
        RECT  142.608 47.436 142.632 47.52 ;
    END
  END t_ag[213]
  PIN t_ag[214]
    DIRECTION OUTPUT ;
    USE SIGNAL ;
    PORT
      LAYER M5 ;
        RECT  142.704 47.436 142.728 47.52 ;
    END
  END t_ag[214]
  PIN t_ag[215]
    DIRECTION OUTPUT ;
    USE SIGNAL ;
    PORT
      LAYER M5 ;
        RECT  142.8 47.436 142.824 47.52 ;
    END
  END t_ag[215]
  PIN t_ag[216]
    DIRECTION OUTPUT ;
    USE SIGNAL ;
    PORT
      LAYER M5 ;
        RECT  142.896 47.436 142.92 47.52 ;
    END
  END t_ag[216]
  PIN t_ag[217]
    DIRECTION OUTPUT ;
    USE SIGNAL ;
    PORT
      LAYER M5 ;
        RECT  142.992 47.436 143.016 47.52 ;
    END
  END t_ag[217]
  PIN t_ag[218]
    DIRECTION OUTPUT ;
    USE SIGNAL ;
    PORT
      LAYER M5 ;
        RECT  143.088 47.436 143.112 47.52 ;
    END
  END t_ag[218]
  PIN t_ag[219]
    DIRECTION OUTPUT ;
    USE SIGNAL ;
    PORT
      LAYER M5 ;
        RECT  143.184 47.436 143.208 47.52 ;
    END
  END t_ag[219]
  PIN t_ag[21]
    DIRECTION OUTPUT ;
    USE SIGNAL ;
    PORT
      LAYER M5 ;
        RECT  151.824 47.436 151.848 47.52 ;
    END
  END t_ag[21]
  PIN t_ag[220]
    DIRECTION OUTPUT ;
    USE SIGNAL ;
    PORT
      LAYER M5 ;
        RECT  143.28 47.436 143.304 47.52 ;
    END
  END t_ag[220]
  PIN t_ag[221]
    DIRECTION OUTPUT ;
    USE SIGNAL ;
    PORT
      LAYER M5 ;
        RECT  143.376 47.436 143.4 47.52 ;
    END
  END t_ag[221]
  PIN t_ag[222]
    DIRECTION OUTPUT ;
    USE SIGNAL ;
    PORT
      LAYER M5 ;
        RECT  143.472 47.436 143.496 47.52 ;
    END
  END t_ag[222]
  PIN t_ag[223]
    DIRECTION OUTPUT ;
    USE SIGNAL ;
    PORT
      LAYER M5 ;
        RECT  143.568 47.436 143.592 47.52 ;
    END
  END t_ag[223]
  PIN t_ag[224]
    DIRECTION OUTPUT ;
    USE SIGNAL ;
    PORT
      LAYER M5 ;
        RECT  143.664 47.436 143.688 47.52 ;
    END
  END t_ag[224]
  PIN t_ag[225]
    DIRECTION OUTPUT ;
    USE SIGNAL ;
    PORT
      LAYER M5 ;
        RECT  143.76 47.436 143.784 47.52 ;
    END
  END t_ag[225]
  PIN t_ag[226]
    DIRECTION OUTPUT ;
    USE SIGNAL ;
    PORT
      LAYER M5 ;
        RECT  143.856 47.436 143.88 47.52 ;
    END
  END t_ag[226]
  PIN t_ag[227]
    DIRECTION OUTPUT ;
    USE SIGNAL ;
    PORT
      LAYER M5 ;
        RECT  143.952 47.436 143.976 47.52 ;
    END
  END t_ag[227]
  PIN t_ag[228]
    DIRECTION OUTPUT ;
    USE SIGNAL ;
    PORT
      LAYER M5 ;
        RECT  144.048 47.436 144.072 47.52 ;
    END
  END t_ag[228]
  PIN t_ag[229]
    DIRECTION OUTPUT ;
    USE SIGNAL ;
    PORT
      LAYER M5 ;
        RECT  144.144 47.436 144.168 47.52 ;
    END
  END t_ag[229]
  PIN t_ag[22]
    DIRECTION OUTPUT ;
    USE SIGNAL ;
    PORT
      LAYER M5 ;
        RECT  151.92 47.436 151.944 47.52 ;
    END
  END t_ag[22]
  PIN t_ag[230]
    DIRECTION OUTPUT ;
    USE SIGNAL ;
    PORT
      LAYER M5 ;
        RECT  144.24 47.436 144.264 47.52 ;
    END
  END t_ag[230]
  PIN t_ag[231]
    DIRECTION OUTPUT ;
    USE SIGNAL ;
    PORT
      LAYER M5 ;
        RECT  144.336 47.436 144.36 47.52 ;
    END
  END t_ag[231]
  PIN t_ag[232]
    DIRECTION OUTPUT ;
    USE SIGNAL ;
    PORT
      LAYER M5 ;
        RECT  144.432 47.436 144.456 47.52 ;
    END
  END t_ag[232]
  PIN t_ag[233]
    DIRECTION OUTPUT ;
    USE SIGNAL ;
    PORT
      LAYER M5 ;
        RECT  144.528 47.436 144.552 47.52 ;
    END
  END t_ag[233]
  PIN t_ag[234]
    DIRECTION OUTPUT ;
    USE SIGNAL ;
    PORT
      LAYER M5 ;
        RECT  144.624 47.436 144.648 47.52 ;
    END
  END t_ag[234]
  PIN t_ag[235]
    DIRECTION OUTPUT ;
    USE SIGNAL ;
    PORT
      LAYER M5 ;
        RECT  144.72 47.436 144.744 47.52 ;
    END
  END t_ag[235]
  PIN t_ag[236]
    DIRECTION OUTPUT ;
    USE SIGNAL ;
    PORT
      LAYER M5 ;
        RECT  144.816 47.436 144.84 47.52 ;
    END
  END t_ag[236]
  PIN t_ag[237]
    DIRECTION OUTPUT ;
    USE SIGNAL ;
    PORT
      LAYER M5 ;
        RECT  144.912 47.436 144.936 47.52 ;
    END
  END t_ag[237]
  PIN t_ag[238]
    DIRECTION OUTPUT ;
    USE SIGNAL ;
    PORT
      LAYER M5 ;
        RECT  145.008 47.436 145.032 47.52 ;
    END
  END t_ag[238]
  PIN t_ag[239]
    DIRECTION OUTPUT ;
    USE SIGNAL ;
    PORT
      LAYER M5 ;
        RECT  145.104 47.436 145.128 47.52 ;
    END
  END t_ag[239]
  PIN t_ag[23]
    DIRECTION OUTPUT ;
    USE SIGNAL ;
    PORT
      LAYER M5 ;
        RECT  152.016 47.436 152.04 47.52 ;
    END
  END t_ag[23]
  PIN t_ag[240]
    DIRECTION OUTPUT ;
    USE SIGNAL ;
    PORT
      LAYER M5 ;
        RECT  145.2 47.436 145.224 47.52 ;
    END
  END t_ag[240]
  PIN t_ag[241]
    DIRECTION OUTPUT ;
    USE SIGNAL ;
    PORT
      LAYER M5 ;
        RECT  145.296 47.436 145.32 47.52 ;
    END
  END t_ag[241]
  PIN t_ag[242]
    DIRECTION OUTPUT ;
    USE SIGNAL ;
    PORT
      LAYER M5 ;
        RECT  145.392 47.436 145.416 47.52 ;
    END
  END t_ag[242]
  PIN t_ag[243]
    DIRECTION OUTPUT ;
    USE SIGNAL ;
    PORT
      LAYER M5 ;
        RECT  145.488 47.436 145.512 47.52 ;
    END
  END t_ag[243]
  PIN t_ag[244]
    DIRECTION OUTPUT ;
    USE SIGNAL ;
    PORT
      LAYER M5 ;
        RECT  155.568 47.436 155.592 47.52 ;
    END
  END t_ag[244]
  PIN t_ag[245]
    DIRECTION OUTPUT ;
    USE SIGNAL ;
    PORT
      LAYER M5 ;
        RECT  155.664 47.436 155.688 47.52 ;
    END
  END t_ag[245]
  PIN t_ag[246]
    DIRECTION OUTPUT ;
    USE SIGNAL ;
    PORT
      LAYER M5 ;
        RECT  155.76 47.436 155.784 47.52 ;
    END
  END t_ag[246]
  PIN t_ag[247]
    DIRECTION OUTPUT ;
    USE SIGNAL ;
    PORT
      LAYER M5 ;
        RECT  155.856 47.436 155.88 47.52 ;
    END
  END t_ag[247]
  PIN t_ag[248]
    DIRECTION OUTPUT ;
    USE SIGNAL ;
    PORT
      LAYER M5 ;
        RECT  155.952 47.436 155.976 47.52 ;
    END
  END t_ag[248]
  PIN t_ag[249]
    DIRECTION OUTPUT ;
    USE SIGNAL ;
    PORT
      LAYER M5 ;
        RECT  156.048 47.436 156.072 47.52 ;
    END
  END t_ag[249]
  PIN t_ag[24]
    DIRECTION OUTPUT ;
    USE SIGNAL ;
    PORT
      LAYER M5 ;
        RECT  152.112 47.436 152.136 47.52 ;
    END
  END t_ag[24]
  PIN t_ag[250]
    DIRECTION OUTPUT ;
    USE SIGNAL ;
    PORT
      LAYER M5 ;
        RECT  156.144 47.436 156.168 47.52 ;
    END
  END t_ag[250]
  PIN t_ag[251]
    DIRECTION OUTPUT ;
    USE SIGNAL ;
    PORT
      LAYER M5 ;
        RECT  156.24 47.436 156.264 47.52 ;
    END
  END t_ag[251]
  PIN t_ag[252]
    DIRECTION OUTPUT ;
    USE SIGNAL ;
    PORT
      LAYER M5 ;
        RECT  156.336 47.436 156.36 47.52 ;
    END
  END t_ag[252]
  PIN t_ag[253]
    DIRECTION OUTPUT ;
    USE SIGNAL ;
    PORT
      LAYER M5 ;
        RECT  156.432 47.436 156.456 47.52 ;
    END
  END t_ag[253]
  PIN t_ag[254]
    DIRECTION OUTPUT ;
    USE SIGNAL ;
    PORT
      LAYER M5 ;
        RECT  156.528 47.436 156.552 47.52 ;
    END
  END t_ag[254]
  PIN t_ag[255]
    DIRECTION OUTPUT ;
    USE SIGNAL ;
    PORT
      LAYER M5 ;
        RECT  156.624 47.436 156.648 47.52 ;
    END
  END t_ag[255]
  PIN t_ag[256]
    DIRECTION OUTPUT ;
    USE SIGNAL ;
    PORT
      LAYER M5 ;
        RECT  156.72 47.436 156.744 47.52 ;
    END
  END t_ag[256]
  PIN t_ag[257]
    DIRECTION OUTPUT ;
    USE SIGNAL ;
    PORT
      LAYER M5 ;
        RECT  156.816 47.436 156.84 47.52 ;
    END
  END t_ag[257]
  PIN t_ag[258]
    DIRECTION OUTPUT ;
    USE SIGNAL ;
    PORT
      LAYER M5 ;
        RECT  156.912 47.436 156.936 47.52 ;
    END
  END t_ag[258]
  PIN t_ag[259]
    DIRECTION OUTPUT ;
    USE SIGNAL ;
    PORT
      LAYER M5 ;
        RECT  157.008 47.436 157.032 47.52 ;
    END
  END t_ag[259]
  PIN t_ag[25]
    DIRECTION OUTPUT ;
    USE SIGNAL ;
    PORT
      LAYER M5 ;
        RECT  152.208 47.436 152.232 47.52 ;
    END
  END t_ag[25]
  PIN t_ag[260]
    DIRECTION OUTPUT ;
    USE SIGNAL ;
    PORT
      LAYER M5 ;
        RECT  157.104 47.436 157.128 47.52 ;
    END
  END t_ag[260]
  PIN t_ag[261]
    DIRECTION OUTPUT ;
    USE SIGNAL ;
    PORT
      LAYER M5 ;
        RECT  157.2 47.436 157.224 47.52 ;
    END
  END t_ag[261]
  PIN t_ag[262]
    DIRECTION OUTPUT ;
    USE SIGNAL ;
    PORT
      LAYER M5 ;
        RECT  157.296 47.436 157.32 47.52 ;
    END
  END t_ag[262]
  PIN t_ag[263]
    DIRECTION OUTPUT ;
    USE SIGNAL ;
    PORT
      LAYER M5 ;
        RECT  157.392 47.436 157.416 47.52 ;
    END
  END t_ag[263]
  PIN t_ag[264]
    DIRECTION OUTPUT ;
    USE SIGNAL ;
    PORT
      LAYER M5 ;
        RECT  157.488 47.436 157.512 47.52 ;
    END
  END t_ag[264]
  PIN t_ag[265]
    DIRECTION OUTPUT ;
    USE SIGNAL ;
    PORT
      LAYER M5 ;
        RECT  157.584 47.436 157.608 47.52 ;
    END
  END t_ag[265]
  PIN t_ag[266]
    DIRECTION OUTPUT ;
    USE SIGNAL ;
    PORT
      LAYER M5 ;
        RECT  157.68 47.436 157.704 47.52 ;
    END
  END t_ag[266]
  PIN t_ag[267]
    DIRECTION OUTPUT ;
    USE SIGNAL ;
    PORT
      LAYER M5 ;
        RECT  157.776 47.436 157.8 47.52 ;
    END
  END t_ag[267]
  PIN t_ag[268]
    DIRECTION OUTPUT ;
    USE SIGNAL ;
    PORT
      LAYER M5 ;
        RECT  157.872 47.436 157.896 47.52 ;
    END
  END t_ag[268]
  PIN t_ag[269]
    DIRECTION OUTPUT ;
    USE SIGNAL ;
    PORT
      LAYER M5 ;
        RECT  157.968 47.436 157.992 47.52 ;
    END
  END t_ag[269]
  PIN t_ag[26]
    DIRECTION OUTPUT ;
    USE SIGNAL ;
    PORT
      LAYER M5 ;
        RECT  152.304 47.436 152.328 47.52 ;
    END
  END t_ag[26]
  PIN t_ag[270]
    DIRECTION OUTPUT ;
    USE SIGNAL ;
    PORT
      LAYER M5 ;
        RECT  158.064 47.436 158.088 47.52 ;
    END
  END t_ag[270]
  PIN t_ag[271]
    DIRECTION OUTPUT ;
    USE SIGNAL ;
    PORT
      LAYER M5 ;
        RECT  158.16 47.436 158.184 47.52 ;
    END
  END t_ag[271]
  PIN t_ag[272]
    DIRECTION OUTPUT ;
    USE SIGNAL ;
    PORT
      LAYER M5 ;
        RECT  158.256 47.436 158.28 47.52 ;
    END
  END t_ag[272]
  PIN t_ag[273]
    DIRECTION OUTPUT ;
    USE SIGNAL ;
    PORT
      LAYER M5 ;
        RECT  158.352 47.436 158.376 47.52 ;
    END
  END t_ag[273]
  PIN t_ag[274]
    DIRECTION OUTPUT ;
    USE SIGNAL ;
    PORT
      LAYER M5 ;
        RECT  158.448 47.436 158.472 47.52 ;
    END
  END t_ag[274]
  PIN t_ag[275]
    DIRECTION OUTPUT ;
    USE SIGNAL ;
    PORT
      LAYER M5 ;
        RECT  158.544 47.436 158.568 47.52 ;
    END
  END t_ag[275]
  PIN t_ag[276]
    DIRECTION OUTPUT ;
    USE SIGNAL ;
    PORT
      LAYER M5 ;
        RECT  154.896 47.436 154.92 47.52 ;
    END
  END t_ag[276]
  PIN t_ag[277]
    DIRECTION OUTPUT ;
    USE SIGNAL ;
    PORT
      LAYER M5 ;
        RECT  154.992 47.436 155.016 47.52 ;
    END
  END t_ag[277]
  PIN t_ag[278]
    DIRECTION OUTPUT ;
    USE SIGNAL ;
    PORT
      LAYER M5 ;
        RECT  155.088 47.436 155.112 47.52 ;
    END
  END t_ag[278]
  PIN t_ag[279]
    DIRECTION OUTPUT ;
    USE SIGNAL ;
    PORT
      LAYER M5 ;
        RECT  155.184 47.436 155.208 47.52 ;
    END
  END t_ag[279]
  PIN t_ag[27]
    DIRECTION OUTPUT ;
    USE SIGNAL ;
    PORT
      LAYER M5 ;
        RECT  152.4 47.436 152.424 47.52 ;
    END
  END t_ag[27]
  PIN t_ag[280]
    DIRECTION OUTPUT ;
    USE SIGNAL ;
    PORT
      LAYER M5 ;
        RECT  155.28 47.436 155.304 47.52 ;
    END
  END t_ag[280]
  PIN t_ag[281]
    DIRECTION OUTPUT ;
    USE SIGNAL ;
    PORT
      LAYER M5 ;
        RECT  155.376 47.436 155.4 47.52 ;
    END
  END t_ag[281]
  PIN t_ag[28]
    DIRECTION OUTPUT ;
    USE SIGNAL ;
    PORT
      LAYER M5 ;
        RECT  152.496 47.436 152.52 47.52 ;
    END
  END t_ag[28]
  PIN t_ag[29]
    DIRECTION OUTPUT ;
    USE SIGNAL ;
    PORT
      LAYER M5 ;
        RECT  152.592 47.436 152.616 47.52 ;
    END
  END t_ag[29]
  PIN t_ag[2]
    DIRECTION OUTPUT ;
    USE SIGNAL ;
    PORT
      LAYER M5 ;
        RECT  166.128 47.436 166.152 47.52 ;
    END
  END t_ag[2]
  PIN t_ag[30]
    DIRECTION OUTPUT ;
    USE SIGNAL ;
    PORT
      LAYER M5 ;
        RECT  152.688 47.436 152.712 47.52 ;
    END
  END t_ag[30]
  PIN t_ag[31]
    DIRECTION OUTPUT ;
    USE SIGNAL ;
    PORT
      LAYER M5 ;
        RECT  152.784 47.436 152.808 47.52 ;
    END
  END t_ag[31]
  PIN t_ag[32]
    DIRECTION OUTPUT ;
    USE SIGNAL ;
    PORT
      LAYER M5 ;
        RECT  152.88 47.436 152.904 47.52 ;
    END
  END t_ag[32]
  PIN t_ag[33]
    DIRECTION OUTPUT ;
    USE SIGNAL ;
    PORT
      LAYER M5 ;
        RECT  152.976 47.436 153 47.52 ;
    END
  END t_ag[33]
  PIN t_ag[34]
    DIRECTION OUTPUT ;
    USE SIGNAL ;
    PORT
      LAYER M5 ;
        RECT  153.072 47.436 153.096 47.52 ;
    END
  END t_ag[34]
  PIN t_ag[35]
    DIRECTION OUTPUT ;
    USE SIGNAL ;
    PORT
      LAYER M5 ;
        RECT  153.168 47.436 153.192 47.52 ;
    END
  END t_ag[35]
  PIN t_ag[36]
    DIRECTION OUTPUT ;
    USE SIGNAL ;
    PORT
      LAYER M5 ;
        RECT  153.264 47.436 153.288 47.52 ;
    END
  END t_ag[36]
  PIN t_ag[37]
    DIRECTION OUTPUT ;
    USE SIGNAL ;
    PORT
      LAYER M5 ;
        RECT  153.36 47.436 153.384 47.52 ;
    END
  END t_ag[37]
  PIN t_ag[38]
    DIRECTION OUTPUT ;
    USE SIGNAL ;
    PORT
      LAYER M5 ;
        RECT  153.456 47.436 153.48 47.52 ;
    END
  END t_ag[38]
  PIN t_ag[39]
    DIRECTION OUTPUT ;
    USE SIGNAL ;
    PORT
      LAYER M5 ;
        RECT  153.552 47.436 153.576 47.52 ;
    END
  END t_ag[39]
  PIN t_ag[3]
    DIRECTION OUTPUT ;
    USE SIGNAL ;
    PORT
      LAYER M5 ;
        RECT  166.224 47.436 166.248 47.52 ;
    END
  END t_ag[3]
  PIN t_ag[40]
    DIRECTION OUTPUT ;
    USE SIGNAL ;
    PORT
      LAYER M5 ;
        RECT  153.648 47.436 153.672 47.52 ;
    END
  END t_ag[40]
  PIN t_ag[41]
    DIRECTION OUTPUT ;
    USE SIGNAL ;
    PORT
      LAYER M5 ;
        RECT  153.744 47.436 153.768 47.52 ;
    END
  END t_ag[41]
  PIN t_ag[42]
    DIRECTION OUTPUT ;
    USE SIGNAL ;
    PORT
      LAYER M5 ;
        RECT  153.84 47.436 153.864 47.52 ;
    END
  END t_ag[42]
  PIN t_ag[43]
    DIRECTION OUTPUT ;
    USE SIGNAL ;
    PORT
      LAYER M5 ;
        RECT  153.936 47.436 153.96 47.52 ;
    END
  END t_ag[43]
  PIN t_ag[44]
    DIRECTION OUTPUT ;
    USE SIGNAL ;
    PORT
      LAYER M5 ;
        RECT  154.032 47.436 154.056 47.52 ;
    END
  END t_ag[44]
  PIN t_ag[45]
    DIRECTION OUTPUT ;
    USE SIGNAL ;
    PORT
      LAYER M5 ;
        RECT  154.128 47.436 154.152 47.52 ;
    END
  END t_ag[45]
  PIN t_ag[46]
    DIRECTION OUTPUT ;
    USE SIGNAL ;
    PORT
      LAYER M5 ;
        RECT  154.224 47.436 154.248 47.52 ;
    END
  END t_ag[46]
  PIN t_ag[47]
    DIRECTION OUTPUT ;
    USE SIGNAL ;
    PORT
      LAYER M5 ;
        RECT  154.32 47.436 154.344 47.52 ;
    END
  END t_ag[47]
  PIN t_ag[48]
    DIRECTION OUTPUT ;
    USE SIGNAL ;
    PORT
      LAYER M5 ;
        RECT  154.416 47.436 154.44 47.52 ;
    END
  END t_ag[48]
  PIN t_ag[49]
    DIRECTION OUTPUT ;
    USE SIGNAL ;
    PORT
      LAYER M5 ;
        RECT  154.512 47.436 154.536 47.52 ;
    END
  END t_ag[49]
  PIN t_ag[4]
    DIRECTION OUTPUT ;
    USE SIGNAL ;
    PORT
      LAYER M5 ;
        RECT  166.32 47.436 166.344 47.52 ;
    END
  END t_ag[4]
  PIN t_ag[50]
    DIRECTION OUTPUT ;
    USE SIGNAL ;
    PORT
      LAYER M5 ;
        RECT  154.608 47.436 154.632 47.52 ;
    END
  END t_ag[50]
  PIN t_ag[51]
    DIRECTION OUTPUT ;
    USE SIGNAL ;
    PORT
      LAYER M5 ;
        RECT  154.704 47.436 154.728 47.52 ;
    END
  END t_ag[51]
  PIN t_ag[52]
    DIRECTION OUTPUT ;
    USE SIGNAL ;
    PORT
      LAYER M5 ;
        RECT  148.656 47.436 148.68 47.52 ;
    END
  END t_ag[52]
  PIN t_ag[53]
    DIRECTION OUTPUT ;
    USE SIGNAL ;
    PORT
      LAYER M5 ;
        RECT  148.752 47.436 148.776 47.52 ;
    END
  END t_ag[53]
  PIN t_ag[54]
    DIRECTION OUTPUT ;
    USE SIGNAL ;
    PORT
      LAYER M5 ;
        RECT  148.848 47.436 148.872 47.52 ;
    END
  END t_ag[54]
  PIN t_ag[55]
    DIRECTION OUTPUT ;
    USE SIGNAL ;
    PORT
      LAYER M5 ;
        RECT  148.944 47.436 148.968 47.52 ;
    END
  END t_ag[55]
  PIN t_ag[56]
    DIRECTION OUTPUT ;
    USE SIGNAL ;
    PORT
      LAYER M5 ;
        RECT  149.04 47.436 149.064 47.52 ;
    END
  END t_ag[56]
  PIN t_ag[57]
    DIRECTION OUTPUT ;
    USE SIGNAL ;
    PORT
      LAYER M5 ;
        RECT  149.136 47.436 149.16 47.52 ;
    END
  END t_ag[57]
  PIN t_ag[58]
    DIRECTION OUTPUT ;
    USE SIGNAL ;
    PORT
      LAYER M5 ;
        RECT  149.232 47.436 149.256 47.52 ;
    END
  END t_ag[58]
  PIN t_ag[59]
    DIRECTION OUTPUT ;
    USE SIGNAL ;
    PORT
      LAYER M5 ;
        RECT  149.328 47.436 149.352 47.52 ;
    END
  END t_ag[59]
  PIN t_ag[5]
    DIRECTION OUTPUT ;
    USE SIGNAL ;
    PORT
      LAYER M5 ;
        RECT  166.416 47.436 166.44 47.52 ;
    END
  END t_ag[5]
  PIN t_ag[60]
    DIRECTION OUTPUT ;
    USE SIGNAL ;
    PORT
      LAYER M5 ;
        RECT  149.424 47.436 149.448 47.52 ;
    END
  END t_ag[60]
  PIN t_ag[61]
    DIRECTION OUTPUT ;
    USE SIGNAL ;
    PORT
      LAYER M5 ;
        RECT  149.52 47.436 149.544 47.52 ;
    END
  END t_ag[61]
  PIN t_ag[62]
    DIRECTION OUTPUT ;
    USE SIGNAL ;
    PORT
      LAYER M5 ;
        RECT  149.616 47.436 149.64 47.52 ;
    END
  END t_ag[62]
  PIN t_ag[63]
    DIRECTION OUTPUT ;
    USE SIGNAL ;
    PORT
      LAYER M5 ;
        RECT  149.712 47.436 149.736 47.52 ;
    END
  END t_ag[63]
  PIN t_ag[64]
    DIRECTION OUTPUT ;
    USE SIGNAL ;
    PORT
      LAYER M5 ;
        RECT  149.808 47.436 149.832 47.52 ;
    END
  END t_ag[64]
  PIN t_ag[65]
    DIRECTION OUTPUT ;
    USE SIGNAL ;
    PORT
      LAYER M5 ;
        RECT  149.904 47.436 149.928 47.52 ;
    END
  END t_ag[65]
  PIN t_ag[66]
    DIRECTION OUTPUT ;
    USE SIGNAL ;
    PORT
      LAYER M5 ;
        RECT  150 47.436 150.024 47.52 ;
    END
  END t_ag[66]
  PIN t_ag[67]
    DIRECTION OUTPUT ;
    USE SIGNAL ;
    PORT
      LAYER M5 ;
        RECT  150.096 47.436 150.12 47.52 ;
    END
  END t_ag[67]
  PIN t_ag[68]
    DIRECTION OUTPUT ;
    USE SIGNAL ;
    PORT
      LAYER M5 ;
        RECT  150.192 47.436 150.216 47.52 ;
    END
  END t_ag[68]
  PIN t_ag[69]
    DIRECTION OUTPUT ;
    USE SIGNAL ;
    PORT
      LAYER M5 ;
        RECT  150.288 47.436 150.312 47.52 ;
    END
  END t_ag[69]
  PIN t_ag[6]
    DIRECTION OUTPUT ;
    USE SIGNAL ;
    PORT
      LAYER M5 ;
        RECT  166.512 47.436 166.536 47.52 ;
    END
  END t_ag[6]
  PIN t_ag[70]
    DIRECTION OUTPUT ;
    USE SIGNAL ;
    PORT
      LAYER M5 ;
        RECT  150.384 47.436 150.408 47.52 ;
    END
  END t_ag[70]
  PIN t_ag[71]
    DIRECTION OUTPUT ;
    USE SIGNAL ;
    PORT
      LAYER M5 ;
        RECT  150.48 47.436 150.504 47.52 ;
    END
  END t_ag[71]
  PIN t_ag[72]
    DIRECTION OUTPUT ;
    USE SIGNAL ;
    PORT
      LAYER M5 ;
        RECT  150.576 47.436 150.6 47.52 ;
    END
  END t_ag[72]
  PIN t_ag[73]
    DIRECTION OUTPUT ;
    USE SIGNAL ;
    PORT
      LAYER M5 ;
        RECT  150.672 47.436 150.696 47.52 ;
    END
  END t_ag[73]
  PIN t_ag[74]
    DIRECTION OUTPUT ;
    USE SIGNAL ;
    PORT
      LAYER M5 ;
        RECT  150.768 47.436 150.792 47.52 ;
    END
  END t_ag[74]
  PIN t_ag[75]
    DIRECTION OUTPUT ;
    USE SIGNAL ;
    PORT
      LAYER M5 ;
        RECT  150.864 47.436 150.888 47.52 ;
    END
  END t_ag[75]
  PIN t_ag[76]
    DIRECTION OUTPUT ;
    USE SIGNAL ;
    PORT
      LAYER M5 ;
        RECT  150.96 47.436 150.984 47.52 ;
    END
  END t_ag[76]
  PIN t_ag[77]
    DIRECTION OUTPUT ;
    USE SIGNAL ;
    PORT
      LAYER M5 ;
        RECT  151.056 47.436 151.08 47.52 ;
    END
  END t_ag[77]
  PIN t_ag[78]
    DIRECTION OUTPUT ;
    USE SIGNAL ;
    PORT
      LAYER M5 ;
        RECT  151.152 47.436 151.176 47.52 ;
    END
  END t_ag[78]
  PIN t_ag[79]
    DIRECTION OUTPUT ;
    USE SIGNAL ;
    PORT
      LAYER M5 ;
        RECT  151.248 47.436 151.272 47.52 ;
    END
  END t_ag[79]
  PIN t_ag[7]
    DIRECTION OUTPUT ;
    USE SIGNAL ;
    PORT
      LAYER M5 ;
        RECT  166.608 47.436 166.632 47.52 ;
    END
  END t_ag[7]
  PIN t_ag[80]
    DIRECTION OUTPUT ;
    USE SIGNAL ;
    PORT
      LAYER M5 ;
        RECT  151.344 47.436 151.368 47.52 ;
    END
  END t_ag[80]
  PIN t_ag[81]
    DIRECTION OUTPUT ;
    USE SIGNAL ;
    PORT
      LAYER M5 ;
        RECT  151.44 47.436 151.464 47.52 ;
    END
  END t_ag[81]
  PIN t_ag[82]
    DIRECTION OUTPUT ;
    USE SIGNAL ;
    PORT
      LAYER M5 ;
        RECT  151.536 47.436 151.56 47.52 ;
    END
  END t_ag[82]
  PIN t_ag[83]
    DIRECTION OUTPUT ;
    USE SIGNAL ;
    PORT
      LAYER M5 ;
        RECT  151.632 47.436 151.656 47.52 ;
    END
  END t_ag[83]
  PIN t_ag[84]
    DIRECTION OUTPUT ;
    USE SIGNAL ;
    PORT
      LAYER M5 ;
        RECT  158.64 47.436 158.664 47.52 ;
    END
  END t_ag[84]
  PIN t_ag[85]
    DIRECTION OUTPUT ;
    USE SIGNAL ;
    PORT
      LAYER M5 ;
        RECT  158.736 47.436 158.76 47.52 ;
    END
  END t_ag[85]
  PIN t_ag[86]
    DIRECTION OUTPUT ;
    USE SIGNAL ;
    PORT
      LAYER M5 ;
        RECT  158.832 47.436 158.856 47.52 ;
    END
  END t_ag[86]
  PIN t_ag[87]
    DIRECTION OUTPUT ;
    USE SIGNAL ;
    PORT
      LAYER M5 ;
        RECT  158.928 47.436 158.952 47.52 ;
    END
  END t_ag[87]
  PIN t_ag[88]
    DIRECTION OUTPUT ;
    USE SIGNAL ;
    PORT
      LAYER M5 ;
        RECT  159.024 47.436 159.048 47.52 ;
    END
  END t_ag[88]
  PIN t_ag[89]
    DIRECTION OUTPUT ;
    USE SIGNAL ;
    PORT
      LAYER M5 ;
        RECT  159.12 47.436 159.144 47.52 ;
    END
  END t_ag[89]
  PIN t_ag[8]
    DIRECTION OUTPUT ;
    USE SIGNAL ;
    PORT
      LAYER M5 ;
        RECT  166.704 47.436 166.728 47.52 ;
    END
  END t_ag[8]
  PIN t_ag[90]
    DIRECTION OUTPUT ;
    USE SIGNAL ;
    PORT
      LAYER M5 ;
        RECT  159.216 47.436 159.24 47.52 ;
    END
  END t_ag[90]
  PIN t_ag[91]
    DIRECTION OUTPUT ;
    USE SIGNAL ;
    PORT
      LAYER M5 ;
        RECT  159.312 47.436 159.336 47.52 ;
    END
  END t_ag[91]
  PIN t_ag[92]
    DIRECTION OUTPUT ;
    USE SIGNAL ;
    PORT
      LAYER M5 ;
        RECT  159.408 47.436 159.432 47.52 ;
    END
  END t_ag[92]
  PIN t_ag[93]
    DIRECTION OUTPUT ;
    USE SIGNAL ;
    PORT
      LAYER M5 ;
        RECT  159.504 47.436 159.528 47.52 ;
    END
  END t_ag[93]
  PIN t_ag[94]
    DIRECTION OUTPUT ;
    USE SIGNAL ;
    PORT
      LAYER M5 ;
        RECT  159.6 47.436 159.624 47.52 ;
    END
  END t_ag[94]
  PIN t_ag[95]
    DIRECTION OUTPUT ;
    USE SIGNAL ;
    PORT
      LAYER M5 ;
        RECT  159.696 47.436 159.72 47.52 ;
    END
  END t_ag[95]
  PIN t_ag[96]
    DIRECTION OUTPUT ;
    USE SIGNAL ;
    PORT
      LAYER M5 ;
        RECT  159.792 47.436 159.816 47.52 ;
    END
  END t_ag[96]
  PIN t_ag[97]
    DIRECTION OUTPUT ;
    USE SIGNAL ;
    PORT
      LAYER M5 ;
        RECT  159.888 47.436 159.912 47.52 ;
    END
  END t_ag[97]
  PIN t_ag[98]
    DIRECTION OUTPUT ;
    USE SIGNAL ;
    PORT
      LAYER M5 ;
        RECT  159.984 47.436 160.008 47.52 ;
    END
  END t_ag[98]
  PIN t_ag[99]
    DIRECTION OUTPUT ;
    USE SIGNAL ;
    PORT
      LAYER M5 ;
        RECT  160.08 47.436 160.104 47.52 ;
    END
  END t_ag[99]
  PIN t_ag[9]
    DIRECTION OUTPUT ;
    USE SIGNAL ;
    PORT
      LAYER M5 ;
        RECT  166.8 47.436 166.824 47.52 ;
    END
  END t_ag[9]
  PIN t_collective
    DIRECTION OUTPUT ;
    USE SIGNAL ;
    PORT
      LAYER M5 ;
        RECT  155.472 47.436 155.496 47.52 ;
    END
  END t_collective
  PIN vrel_i[0]
    DIRECTION INPUT ;
    USE SIGNAL ;
    PORT
      LAYER M4 ;
        RECT  328.236 23.568 328.32 23.592 ;
    END
  END vrel_i[0]
  PIN vrel_i[1]
    DIRECTION INPUT ;
    USE SIGNAL ;
    PORT
      LAYER M4 ;
        RECT  328.236 23.664 328.32 23.688 ;
    END
  END vrel_i[1]
  PIN vrel_i[2]
    DIRECTION INPUT ;
    USE SIGNAL ;
    PORT
      LAYER M4 ;
        RECT  328.236 23.76 328.32 23.784 ;
    END
  END vrel_i[2]
  PIN vrel_i[3]
    DIRECTION INPUT ;
    USE SIGNAL ;
    PORT
      LAYER M4 ;
        RECT  328.236 23.856 328.32 23.88 ;
    END
  END vrel_i[3]
  PIN vrel_o[0]
    DIRECTION OUTPUT ;
    USE SIGNAL ;
    PORT
      LAYER M4 ;
        RECT  0 25.2 0.084 25.224 ;
    END
  END vrel_o[0]
  PIN vrel_o[1]
    DIRECTION OUTPUT ;
    USE SIGNAL ;
    PORT
      LAYER M4 ;
        RECT  0 25.296 0.084 25.32 ;
    END
  END vrel_o[1]
  PIN vrel_o[2]
    DIRECTION OUTPUT ;
    USE SIGNAL ;
    PORT
      LAYER M4 ;
        RECT  0 25.392 0.084 25.416 ;
    END
  END vrel_o[2]
  PIN vrel_o[3]
    DIRECTION OUTPUT ;
    USE SIGNAL ;
    PORT
      LAYER M4 ;
        RECT  0 25.488 0.084 25.512 ;
    END
  END vrel_o[3]
  PIN werr_i
    DIRECTION INPUT ;
    USE SIGNAL ;
    PORT
      LAYER M5 ;
        RECT  164.4 0 164.424 0.084 ;
    END
  END werr_i
  PIN werr_o
    DIRECTION OUTPUT ;
    USE SIGNAL ;
    PORT
      LAYER M4 ;
        RECT  328.236 23.952 328.32 23.976 ;
    END
  END werr_o
  PIN wn_o[0]
    DIRECTION OUTPUT ;
    USE SIGNAL ;
    PORT
      LAYER M4 ;
        RECT  328.236 24.048 328.32 24.072 ;
    END
  END wn_o[0]
  PIN wn_o[10]
    DIRECTION OUTPUT ;
    USE SIGNAL ;
    PORT
      LAYER M4 ;
        RECT  328.236 25.008 328.32 25.032 ;
    END
  END wn_o[10]
  PIN wn_o[11]
    DIRECTION OUTPUT ;
    USE SIGNAL ;
    PORT
      LAYER M4 ;
        RECT  328.236 25.104 328.32 25.128 ;
    END
  END wn_o[11]
  PIN wn_o[12]
    DIRECTION OUTPUT ;
    USE SIGNAL ;
    PORT
      LAYER M4 ;
        RECT  328.236 25.2 328.32 25.224 ;
    END
  END wn_o[12]
  PIN wn_o[13]
    DIRECTION OUTPUT ;
    USE SIGNAL ;
    PORT
      LAYER M4 ;
        RECT  328.236 25.296 328.32 25.32 ;
    END
  END wn_o[13]
  PIN wn_o[14]
    DIRECTION OUTPUT ;
    USE SIGNAL ;
    PORT
      LAYER M4 ;
        RECT  328.236 25.392 328.32 25.416 ;
    END
  END wn_o[14]
  PIN wn_o[15]
    DIRECTION OUTPUT ;
    USE SIGNAL ;
    PORT
      LAYER M4 ;
        RECT  328.236 25.488 328.32 25.512 ;
    END
  END wn_o[15]
  PIN wn_o[1]
    DIRECTION OUTPUT ;
    USE SIGNAL ;
    PORT
      LAYER M4 ;
        RECT  328.236 24.144 328.32 24.168 ;
    END
  END wn_o[1]
  PIN wn_o[2]
    DIRECTION OUTPUT ;
    USE SIGNAL ;
    PORT
      LAYER M4 ;
        RECT  328.236 24.24 328.32 24.264 ;
    END
  END wn_o[2]
  PIN wn_o[3]
    DIRECTION OUTPUT ;
    USE SIGNAL ;
    PORT
      LAYER M4 ;
        RECT  328.236 24.336 328.32 24.36 ;
    END
  END wn_o[3]
  PIN wn_o[4]
    DIRECTION OUTPUT ;
    USE SIGNAL ;
    PORT
      LAYER M4 ;
        RECT  328.236 24.432 328.32 24.456 ;
    END
  END wn_o[4]
  PIN wn_o[5]
    DIRECTION OUTPUT ;
    USE SIGNAL ;
    PORT
      LAYER M4 ;
        RECT  328.236 24.528 328.32 24.552 ;
    END
  END wn_o[5]
  PIN wn_o[6]
    DIRECTION OUTPUT ;
    USE SIGNAL ;
    PORT
      LAYER M4 ;
        RECT  328.236 24.624 328.32 24.648 ;
    END
  END wn_o[6]
  PIN wn_o[7]
    DIRECTION OUTPUT ;
    USE SIGNAL ;
    PORT
      LAYER M4 ;
        RECT  328.236 24.72 328.32 24.744 ;
    END
  END wn_o[7]
  PIN wn_o[8]
    DIRECTION OUTPUT ;
    USE SIGNAL ;
    PORT
      LAYER M4 ;
        RECT  328.236 24.816 328.32 24.84 ;
    END
  END wn_o[8]
  PIN wn_o[9]
    DIRECTION OUTPUT ;
    USE SIGNAL ;
    PORT
      LAYER M4 ;
        RECT  328.236 24.912 328.32 24.936 ;
    END
  END wn_o[9]
  PIN VDD
    DIRECTION INOUT ;
    USE POWER ;
    PORT
      LAYER M5 ;
        RECT  321.192 2.151 321.312 45.369 ;
        RECT  315.792 2.151 315.912 45.369 ;
        RECT  310.392 2.151 310.512 45.369 ;
        RECT  304.992 2.151 305.112 45.369 ;
        RECT  299.592 2.151 299.712 45.369 ;
        RECT  294.192 2.151 294.312 45.369 ;
        RECT  288.792 2.151 288.912 45.369 ;
        RECT  283.392 2.151 283.512 45.369 ;
        RECT  277.992 2.151 278.112 45.369 ;
        RECT  272.592 2.151 272.712 45.369 ;
        RECT  267.192 2.151 267.312 45.369 ;
        RECT  261.792 2.151 261.912 45.369 ;
        RECT  256.392 2.151 256.512 45.369 ;
        RECT  250.992 2.151 251.112 45.369 ;
        RECT  245.592 2.151 245.712 45.369 ;
        RECT  240.192 2.151 240.312 45.369 ;
        RECT  234.792 2.151 234.912 45.369 ;
        RECT  229.392 2.151 229.512 45.369 ;
        RECT  223.992 2.151 224.112 45.369 ;
        RECT  218.592 2.151 218.712 45.369 ;
        RECT  213.192 2.151 213.312 45.369 ;
        RECT  207.792 2.151 207.912 45.369 ;
        RECT  202.392 2.151 202.512 45.369 ;
        RECT  196.992 2.151 197.112 45.369 ;
        RECT  191.592 2.151 191.712 45.369 ;
        RECT  186.192 2.151 186.312 45.369 ;
        RECT  180.792 2.151 180.912 45.369 ;
        RECT  175.392 2.151 175.512 45.369 ;
        RECT  169.992 2.151 170.112 45.369 ;
        RECT  164.592 2.151 164.712 45.369 ;
        RECT  159.192 2.151 159.312 45.369 ;
        RECT  153.792 2.151 153.912 45.369 ;
        RECT  148.392 2.151 148.512 45.369 ;
        RECT  142.992 2.151 143.112 45.369 ;
        RECT  137.592 2.151 137.712 45.369 ;
        RECT  132.192 2.151 132.312 45.369 ;
        RECT  126.792 2.151 126.912 45.369 ;
        RECT  121.392 2.151 121.512 45.369 ;
        RECT  115.992 2.151 116.112 45.369 ;
        RECT  110.592 2.151 110.712 45.369 ;
        RECT  105.192 2.151 105.312 45.369 ;
        RECT  99.792 2.151 99.912 45.369 ;
        RECT  94.392 2.151 94.512 45.369 ;
        RECT  88.992 2.151 89.112 45.369 ;
        RECT  83.592 2.151 83.712 45.369 ;
        RECT  78.192 2.151 78.312 45.369 ;
        RECT  72.792 2.151 72.912 45.369 ;
        RECT  67.392 2.151 67.512 45.369 ;
        RECT  61.992 2.151 62.112 45.369 ;
        RECT  56.592 2.151 56.712 45.369 ;
        RECT  51.192 2.151 51.312 45.369 ;
        RECT  45.792 2.151 45.912 45.369 ;
        RECT  40.392 2.151 40.512 45.369 ;
        RECT  34.992 2.151 35.112 45.369 ;
        RECT  29.592 2.151 29.712 45.369 ;
        RECT  24.192 2.151 24.312 45.369 ;
        RECT  18.792 2.151 18.912 45.369 ;
        RECT  13.392 2.151 13.512 45.369 ;
        RECT  7.992 2.151 8.112 45.369 ;
        RECT  2.592 2.151 2.712 45.369 ;
    END
  END VDD
  PIN VSS
    DIRECTION INOUT ;
    USE GROUND ;
    PORT
      LAYER M5 ;
        RECT  321 2.137 321.12 45.383 ;
        RECT  315.6 2.137 315.72 45.383 ;
        RECT  310.2 2.137 310.32 45.383 ;
        RECT  304.8 2.137 304.92 45.383 ;
        RECT  299.4 2.137 299.52 45.383 ;
        RECT  294 2.137 294.12 45.383 ;
        RECT  288.6 2.137 288.72 45.383 ;
        RECT  283.2 2.137 283.32 45.383 ;
        RECT  277.8 2.137 277.92 45.383 ;
        RECT  272.4 2.137 272.52 45.383 ;
        RECT  267 2.137 267.12 45.383 ;
        RECT  261.6 2.137 261.72 45.383 ;
        RECT  256.2 2.137 256.32 45.383 ;
        RECT  250.8 2.137 250.92 45.383 ;
        RECT  245.4 2.137 245.52 45.383 ;
        RECT  240 2.137 240.12 45.383 ;
        RECT  234.6 2.137 234.72 45.383 ;
        RECT  229.2 2.137 229.32 45.383 ;
        RECT  223.8 2.137 223.92 45.383 ;
        RECT  218.4 2.137 218.52 45.383 ;
        RECT  213 2.137 213.12 45.383 ;
        RECT  207.6 2.137 207.72 45.383 ;
        RECT  202.2 2.137 202.32 45.383 ;
        RECT  196.8 2.137 196.92 45.383 ;
        RECT  191.4 2.137 191.52 45.383 ;
        RECT  186 2.137 186.12 45.383 ;
        RECT  180.6 2.137 180.72 45.383 ;
        RECT  175.2 2.137 175.32 45.383 ;
        RECT  169.8 2.137 169.92 45.383 ;
        RECT  164.4 2.137 164.52 45.383 ;
        RECT  159 2.137 159.12 45.383 ;
        RECT  153.6 2.137 153.72 45.383 ;
        RECT  148.2 2.137 148.32 45.383 ;
        RECT  142.8 2.137 142.92 45.383 ;
        RECT  137.4 2.137 137.52 45.383 ;
        RECT  132 2.137 132.12 45.383 ;
        RECT  126.6 2.137 126.72 45.383 ;
        RECT  121.2 2.137 121.32 45.383 ;
        RECT  115.8 2.137 115.92 45.383 ;
        RECT  110.4 2.137 110.52 45.383 ;
        RECT  105 2.137 105.12 45.383 ;
        RECT  99.6 2.137 99.72 45.383 ;
        RECT  94.2 2.137 94.32 45.383 ;
        RECT  88.8 2.137 88.92 45.383 ;
        RECT  83.4 2.137 83.52 45.383 ;
        RECT  78 2.137 78.12 45.383 ;
        RECT  72.6 2.137 72.72 45.383 ;
        RECT  67.2 2.137 67.32 45.383 ;
        RECT  61.8 2.137 61.92 45.383 ;
        RECT  56.4 2.137 56.52 45.383 ;
        RECT  51 2.137 51.12 45.383 ;
        RECT  45.6 2.137 45.72 45.383 ;
        RECT  40.2 2.137 40.32 45.383 ;
        RECT  34.8 2.137 34.92 45.383 ;
        RECT  29.4 2.137 29.52 45.383 ;
        RECT  24 2.137 24.12 45.383 ;
        RECT  18.6 2.137 18.72 45.383 ;
        RECT  13.2 2.137 13.32 45.383 ;
        RECT  7.8 2.137 7.92 45.383 ;
        RECT  2.4 2.137 2.52 45.383 ;
    END
  END VSS
  OBS
    LAYER RVTN ;
     RECT  2.16 2.16 326.16 2.295 ;
     RECT  2.16 2.565 326.16 2.835 ;
     RECT  2.16 3.105 326.16 3.375 ;
     RECT  2.16 3.645 326.16 3.915 ;
     RECT  2.16 4.185 326.16 4.455 ;
     RECT  2.16 4.725 326.16 4.995 ;
     RECT  2.16 5.265 326.16 5.535 ;
     RECT  2.16 5.805 326.16 6.075 ;
     RECT  2.16 6.345 326.16 6.615 ;
     RECT  2.16 6.885 326.16 7.155 ;
     RECT  2.16 7.425 326.16 7.695 ;
     RECT  2.16 7.965 326.16 8.235 ;
     RECT  2.16 8.505 326.16 8.775 ;
     RECT  2.16 9.045 326.16 9.315 ;
     RECT  2.16 9.585 326.16 9.855 ;
     RECT  2.16 10.125 326.16 10.395 ;
     RECT  2.16 10.665 326.16 10.935 ;
     RECT  2.16 11.205 326.16 11.475 ;
     RECT  2.16 11.745 326.16 12.015 ;
     RECT  2.16 12.285 326.16 12.555 ;
     RECT  2.16 12.825 326.16 13.095 ;
     RECT  2.16 13.365 326.16 13.635 ;
     RECT  2.16 13.905 326.16 14.175 ;
     RECT  2.16 14.445 326.16 14.715 ;
     RECT  2.16 14.985 326.16 15.255 ;
     RECT  2.16 15.525 326.16 15.795 ;
     RECT  2.16 16.065 326.16 16.335 ;
     RECT  2.16 16.605 326.16 16.875 ;
     RECT  2.16 17.145 326.16 17.415 ;
     RECT  2.16 17.685 326.16 17.955 ;
     RECT  2.16 18.225 326.16 18.495 ;
     RECT  2.16 18.765 326.16 19.035 ;
     RECT  2.16 19.305 326.16 19.575 ;
     RECT  2.16 19.845 326.16 20.115 ;
     RECT  2.16 20.385 326.16 20.655 ;
     RECT  2.16 20.925 326.16 21.195 ;
     RECT  2.16 21.465 326.16 21.735 ;
     RECT  2.16 22.005 326.16 22.275 ;
     RECT  2.16 22.545 326.16 22.815 ;
     RECT  2.16 23.085 326.16 23.355 ;
     RECT  2.16 23.625 326.16 23.895 ;
     RECT  2.16 24.165 326.16 24.435 ;
     RECT  2.16 24.705 326.16 24.975 ;
     RECT  2.16 25.245 326.16 25.515 ;
     RECT  2.16 25.785 326.16 26.055 ;
     RECT  2.16 26.325 326.16 26.595 ;
     RECT  2.16 26.865 326.16 27.135 ;
     RECT  2.16 27.405 326.16 27.675 ;
     RECT  2.16 27.945 326.16 28.215 ;
     RECT  2.16 28.485 326.16 28.755 ;
     RECT  2.16 29.025 326.16 29.295 ;
     RECT  2.16 29.565 326.16 29.835 ;
     RECT  2.16 30.105 326.16 30.375 ;
     RECT  2.16 30.645 326.16 30.915 ;
     RECT  2.16 31.185 326.16 31.455 ;
     RECT  2.16 31.725 326.16 31.995 ;
     RECT  2.16 32.265 326.16 32.535 ;
     RECT  2.16 32.805 326.16 33.075 ;
     RECT  2.16 33.345 326.16 33.615 ;
     RECT  2.16 33.885 326.16 34.155 ;
     RECT  2.16 34.425 326.16 34.695 ;
     RECT  2.16 34.965 326.16 35.235 ;
     RECT  2.16 35.505 326.16 35.775 ;
     RECT  2.16 36.045 326.16 36.315 ;
     RECT  2.16 36.585 326.16 36.855 ;
     RECT  2.16 37.125 326.16 37.395 ;
     RECT  2.16 37.665 326.16 37.935 ;
     RECT  2.16 38.205 326.16 38.475 ;
     RECT  2.16 38.745 326.16 39.015 ;
     RECT  2.16 39.285 326.16 39.555 ;
     RECT  2.16 39.825 326.16 40.095 ;
     RECT  2.16 40.365 326.16 40.635 ;
     RECT  2.16 40.905 326.16 41.175 ;
     RECT  2.16 41.445 326.16 41.715 ;
     RECT  2.16 41.985 326.16 42.255 ;
     RECT  2.16 42.525 326.16 42.795 ;
     RECT  2.16 43.065 326.16 43.335 ;
     RECT  2.16 43.605 326.16 43.875 ;
     RECT  2.16 44.145 326.16 44.415 ;
     RECT  2.16 44.685 326.16 44.955 ;
     RECT  2.16 45.225 326.16 45.36 ;
    LAYER RVTP ;
     RECT  2.16 2.295 326.16 2.565 ;
     RECT  2.16 2.835 326.16 3.105 ;
     RECT  2.16 3.375 326.16 3.645 ;
     RECT  2.16 3.915 326.16 4.185 ;
     RECT  2.16 4.455 326.16 4.725 ;
     RECT  2.16 4.995 326.16 5.265 ;
     RECT  2.16 5.535 326.16 5.805 ;
     RECT  2.16 6.075 326.16 6.345 ;
     RECT  2.16 6.615 326.16 6.885 ;
     RECT  2.16 7.155 326.16 7.425 ;
     RECT  2.16 7.695 326.16 7.965 ;
     RECT  2.16 8.235 326.16 8.505 ;
     RECT  2.16 8.775 326.16 9.045 ;
     RECT  2.16 9.315 326.16 9.585 ;
     RECT  2.16 9.855 326.16 10.125 ;
     RECT  2.16 10.395 326.16 10.665 ;
     RECT  2.16 10.935 326.16 11.205 ;
     RECT  2.16 11.475 326.16 11.745 ;
     RECT  2.16 12.015 326.16 12.285 ;
     RECT  2.16 12.555 326.16 12.825 ;
     RECT  2.16 13.095 326.16 13.365 ;
     RECT  2.16 13.635 326.16 13.905 ;
     RECT  2.16 14.175 326.16 14.445 ;
     RECT  2.16 14.715 326.16 14.985 ;
     RECT  2.16 15.255 326.16 15.525 ;
     RECT  2.16 15.795 326.16 16.065 ;
     RECT  2.16 16.335 326.16 16.605 ;
     RECT  2.16 16.875 326.16 17.145 ;
     RECT  2.16 17.415 326.16 17.685 ;
     RECT  2.16 17.955 326.16 18.225 ;
     RECT  2.16 18.495 326.16 18.765 ;
     RECT  2.16 19.035 326.16 19.305 ;
     RECT  2.16 19.575 326.16 19.845 ;
     RECT  2.16 20.115 326.16 20.385 ;
     RECT  2.16 20.655 326.16 20.925 ;
     RECT  2.16 21.195 326.16 21.465 ;
     RECT  2.16 21.735 326.16 22.005 ;
     RECT  2.16 22.275 326.16 22.545 ;
     RECT  2.16 22.815 326.16 23.085 ;
     RECT  2.16 23.355 326.16 23.625 ;
     RECT  2.16 23.895 326.16 24.165 ;
     RECT  2.16 24.435 326.16 24.705 ;
     RECT  2.16 24.975 326.16 25.245 ;
     RECT  2.16 25.515 326.16 25.785 ;
     RECT  2.16 26.055 326.16 26.325 ;
     RECT  2.16 26.595 326.16 26.865 ;
     RECT  2.16 27.135 326.16 27.405 ;
     RECT  2.16 27.675 326.16 27.945 ;
     RECT  2.16 28.215 326.16 28.485 ;
     RECT  2.16 28.755 326.16 29.025 ;
     RECT  2.16 29.295 326.16 29.565 ;
     RECT  2.16 29.835 326.16 30.105 ;
     RECT  2.16 30.375 326.16 30.645 ;
     RECT  2.16 30.915 326.16 31.185 ;
     RECT  2.16 31.455 326.16 31.725 ;
     RECT  2.16 31.995 326.16 32.265 ;
     RECT  2.16 32.535 326.16 32.805 ;
     RECT  2.16 33.075 326.16 33.345 ;
     RECT  2.16 33.615 326.16 33.885 ;
     RECT  2.16 34.155 326.16 34.425 ;
     RECT  2.16 34.695 326.16 34.965 ;
     RECT  2.16 35.235 326.16 35.505 ;
     RECT  2.16 35.775 326.16 36.045 ;
     RECT  2.16 36.315 326.16 36.585 ;
     RECT  2.16 36.855 326.16 37.125 ;
     RECT  2.16 37.395 326.16 37.665 ;
     RECT  2.16 37.935 326.16 38.205 ;
     RECT  2.16 38.475 326.16 38.745 ;
     RECT  2.16 39.015 326.16 39.285 ;
     RECT  2.16 39.555 326.16 39.825 ;
     RECT  2.16 40.095 326.16 40.365 ;
     RECT  2.16 40.635 326.16 40.905 ;
     RECT  2.16 41.175 326.16 41.445 ;
     RECT  2.16 41.715 326.16 41.985 ;
     RECT  2.16 42.255 326.16 42.525 ;
     RECT  2.16 42.795 326.16 43.065 ;
     RECT  2.16 43.335 326.16 43.605 ;
     RECT  2.16 43.875 326.16 44.145 ;
     RECT  2.16 44.415 326.16 44.685 ;
     RECT  2.16 44.955 326.16 45.225 ;
    LAYER M1 ;
     RECT  2.16 2.151 326.16 45.369 ;
    LAYER M2 ;
     RECT  0.391 23.598 0.427 23.616 ;
     RECT  0.427 23.598 0.463 23.724 ;
     RECT  0.463 23.328 0.499 23.724 ;
     RECT  0.103 24.48 0.535 25.074 ;
     RECT  0.535 24.48 0.635 25.434 ;
     RECT  0.499 23.094 2.16 23.724 ;
     RECT  0.635 24.48 2.16 25.002 ;
     RECT  2.16 2.151 138.523 45.369 ;
     RECT  138.523 2.106 139.523 45.369 ;
     RECT  140.215 46.701 140.351 46.719 ;
     RECT  139.523 2.151 144.139 45.369 ;
     RECT  144.139 2.151 144.175 45.414 ;
     RECT  144.175 2.151 144.563 45.45 ;
     RECT  144.563 2.151 146.299 45.414 ;
     RECT  146.299 2.151 147.803 45.558 ;
     RECT  147.803 2.151 148.631 45.486 ;
     RECT  148.631 2.151 149.863 45.369 ;
     RECT  149.863 2.151 150.359 45.414 ;
     RECT  150.295 46.701 150.431 46.719 ;
     RECT  153.463 46.701 154.211 46.719 ;
     RECT  156.487 46.701 156.587 46.719 ;
     RECT  150.359 2.151 156.847 45.369 ;
     RECT  156.847 2.106 157.523 45.369 ;
     RECT  157.523 2.151 158.467 45.369 ;
     RECT  158.467 2.151 158.971 45.414 ;
     RECT  158.971 2.151 161.411 45.486 ;
     RECT  161.311 46.701 161.447 46.719 ;
     RECT  161.411 2.151 163.679 45.414 ;
     RECT  163.679 2.151 166.279 45.369 ;
     RECT  166.819 46.701 166.919 46.719 ;
     RECT  166.279 2.151 167.459 45.414 ;
     RECT  167.459 2.151 172.795 45.369 ;
     RECT  172.795 2.034 175.631 45.369 ;
     RECT  175.631 2.106 176.531 45.369 ;
     RECT  176.531 2.151 176.755 45.369 ;
     RECT  176.755 2.151 177.791 45.414 ;
     RECT  177.791 2.151 179.059 45.369 ;
     RECT  179.059 2.034 179.491 45.369 ;
     RECT  179.491 1.962 181.751 45.369 ;
     RECT  181.751 2.106 182.471 45.369 ;
     RECT  182.471 2.151 326.16 45.369 ;
     RECT  326.16 19.008 327.191 25.704 ;
     RECT  327.191 19.008 327.227 24.966 ;
     RECT  327.227 19.044 327.263 20.754 ;
     RECT  327.263 20.16 327.299 20.754 ;
     RECT  327.263 19.044 328.199 19.062 ;
     RECT  327.227 21.744 328.199 24.804 ;
     RECT  327.299 20.736 328.235 20.754 ;
     RECT  328.199 21.744 328.235 22.572 ;
     RECT  328.199 23.976 328.235 24.804 ;
    LAYER M3 ;
     RECT  174.384 0.043 174.402 0.091 ;
     RECT  175.896 0.043 175.914 0.091 ;
     RECT  173.916 0.091 174.942 0.139 ;
     RECT  175.896 0.091 176.418 0.139 ;
     RECT  180.576 0.091 181.098 0.139 ;
     RECT  182.088 0.091 182.106 0.139 ;
     RECT  173.916 0.139 176.418 0.173 ;
     RECT  157.86 0.091 157.878 0.187 ;
     RECT  158.616 0.091 158.922 0.187 ;
     RECT  165.708 0.091 165.726 0.187 ;
     RECT  143.244 0.091 143.586 0.269 ;
     RECT  157.86 0.187 158.922 0.317 ;
     RECT  143.388 0.269 143.586 0.365 ;
     RECT  157.86 0.317 158.778 0.365 ;
     RECT  157.86 0.365 158.022 0.523 ;
     RECT  179.82 0.091 179.838 0.523 ;
     RECT  180.576 0.139 182.106 0.523 ;
     RECT  162.252 0.091 162.27 0.571 ;
     RECT  179.82 0.523 182.106 0.571 ;
     RECT  173.916 0.173 175.626 1.051 ;
     RECT  176.4 0.173 176.418 1.051 ;
     RECT  140.724 0.091 140.742 1.099 ;
     RECT  157.248 0.523 158.022 1.099 ;
     RECT  179.676 0.571 182.466 1.099 ;
     RECT  173.916 1.051 176.418 1.147 ;
     RECT  173.808 1.147 176.418 1.675 ;
     RECT  137.88 0.091 137.898 1.723 ;
     RECT  140.724 1.099 140.778 1.723 ;
     RECT  143.388 0.365 143.406 1.723 ;
     RECT  151.632 1.147 151.65 1.723 ;
     RECT  155.664 1.675 155.682 1.723 ;
     RECT  156.636 1.099 158.022 1.723 ;
     RECT  158.76 0.365 158.778 1.723 ;
     RECT  160.272 0.091 160.29 1.723 ;
     RECT  162.252 0.571 162.306 1.723 ;
     RECT  164.34 0.139 164.358 1.723 ;
     RECT  173.304 1.675 176.418 1.723 ;
     RECT  135.252 1.723 142.506 1.771 ;
     RECT  143.388 1.723 145.314 1.771 ;
     RECT  146.16 1.723 153.486 1.771 ;
     RECT  154.368 1.723 160.29 1.771 ;
     RECT  161.892 1.723 163.278 1.771 ;
     RECT  164.016 1.723 164.358 1.771 ;
     RECT  179.676 1.099 182.502 1.957 ;
     RECT  173.304 1.723 176.562 2.029 ;
     RECT  179.496 1.957 182.502 2.029 ;
     RECT  135.252 1.771 164.358 2.143 ;
     RECT  239.364 2.059 239.382 2.143 ;
     RECT  240.192 2.059 240.21 2.143 ;
     RECT  230.4 2.059 230.418 2.155 ;
     RECT  196.815 2.143 196.905 2.191 ;
     RECT  207.615 2.143 207.705 2.191 ;
     RECT  218.415 2.143 218.505 2.191 ;
     RECT  237.6 2.059 237.618 2.191 ;
     RECT  230.4 2.155 230.454 2.219 ;
     RECT  172.8 2.029 176.562 2.227 ;
     RECT  179.064 2.029 182.502 2.227 ;
     RECT  196.704 2.191 197.01 2.237 ;
     RECT  207.504 2.191 207.81 2.237 ;
     RECT  218.304 2.191 218.61 2.237 ;
     RECT  226.296 2.059 226.314 2.237 ;
     RECT  239.364 2.143 240.21 2.237 ;
     RECT  237.312 2.191 237.618 2.242 ;
     RECT  230.4 2.219 230.418 2.251 ;
     RECT  230.112 2.251 230.418 2.285 ;
     RECT  237.312 2.242 237.33 2.285 ;
     RECT  230.112 2.285 230.13 2.291 ;
     RECT  244.26 2.191 244.278 2.371 ;
     RECT  2.415 2.143 2.505 2.413 ;
     RECT  7.815 2.143 7.905 2.413 ;
     RECT  13.215 2.143 13.305 2.413 ;
     RECT  18.615 2.143 18.705 2.413 ;
     RECT  24.015 2.143 24.105 2.413 ;
     RECT  29.415 2.143 29.505 2.413 ;
     RECT  34.815 2.143 34.905 2.413 ;
     RECT  40.215 2.143 40.305 2.413 ;
     RECT  45.615 2.143 45.705 2.413 ;
     RECT  51.015 2.143 51.105 2.413 ;
     RECT  56.415 2.143 56.505 2.413 ;
     RECT  61.815 2.143 61.905 2.413 ;
     RECT  67.215 2.143 67.305 2.413 ;
     RECT  72.615 2.143 72.705 2.413 ;
     RECT  78.015 2.143 78.105 2.413 ;
     RECT  83.415 2.143 83.505 2.413 ;
     RECT  88.815 2.143 88.905 2.413 ;
     RECT  94.215 2.143 94.305 2.413 ;
     RECT  99.615 2.143 99.705 2.413 ;
     RECT  105.015 2.143 105.105 2.413 ;
     RECT  110.415 2.143 110.505 2.413 ;
     RECT  115.815 2.143 115.905 2.413 ;
     RECT  121.215 2.143 121.305 2.413 ;
     RECT  126.615 2.143 126.705 2.413 ;
     RECT  132.015 2.143 132.105 2.413 ;
     RECT  135.252 2.143 164.505 2.413 ;
     RECT  169.815 2.143 169.905 2.413 ;
     RECT  170.784 2.371 170.802 2.413 ;
     RECT  186.015 2.143 186.105 2.413 ;
     RECT  191.415 2.143 191.505 2.413 ;
     RECT  196.815 2.237 197.01 2.413 ;
     RECT  202.215 2.143 202.305 2.413 ;
     RECT  207.615 2.237 207.81 2.413 ;
     RECT  213.015 2.143 213.105 2.413 ;
     RECT  218.415 2.237 218.61 2.413 ;
     RECT  223.815 2.143 223.905 2.413 ;
     RECT  229.215 2.143 229.305 2.413 ;
     RECT  234.615 2.143 234.705 2.413 ;
     RECT  240.015 2.237 240.21 2.413 ;
     RECT  245.415 2.143 245.505 2.413 ;
     RECT  250.815 2.143 250.905 2.413 ;
     RECT  256.215 2.143 256.305 2.413 ;
     RECT  261.615 2.143 261.705 2.413 ;
     RECT  267.015 2.143 267.105 2.413 ;
     RECT  272.415 2.143 272.505 2.413 ;
     RECT  277.815 2.143 277.905 2.413 ;
     RECT  283.215 2.143 283.305 2.413 ;
     RECT  288.615 2.143 288.705 2.413 ;
     RECT  294.015 2.143 294.105 2.413 ;
     RECT  299.415 2.143 299.505 2.413 ;
     RECT  304.815 2.143 304.905 2.413 ;
     RECT  310.215 2.143 310.305 2.413 ;
     RECT  315.615 2.143 315.705 2.413 ;
     RECT  321.015 2.143 321.105 2.413 ;
     RECT  172.764 2.227 176.562 2.461 ;
     RECT  244.26 2.371 244.53 2.489 ;
     RECT  172.296 2.461 176.562 2.497 ;
     RECT  135.252 2.413 164.697 2.525 ;
     RECT  178.884 2.227 182.502 2.641 ;
     RECT  172.188 2.497 176.562 2.669 ;
     RECT  135.36 2.525 164.697 2.803 ;
     RECT  165.708 0.187 165.978 2.803 ;
     RECT  172.188 2.669 176.526 2.803 ;
     RECT  177.984 2.641 182.502 2.803 ;
     RECT  244.512 2.489 244.53 2.861 ;
     RECT  177.84 2.803 182.502 2.911 ;
     RECT  166.752 1.963 166.77 3.029 ;
     RECT  135.36 2.803 165.978 3.065 ;
     RECT  172.044 2.803 176.526 3.299 ;
     RECT  172.044 3.299 172.062 3.307 ;
     RECT  166.86 3.145 166.878 3.569 ;
     RECT  135.504 3.065 165.978 3.605 ;
     RECT  135.576 3.605 165.978 3.811 ;
     RECT  135.576 3.811 166.446 3.911 ;
     RECT  167.22 3.721 167.562 4.157 ;
     RECT  135.576 3.911 165.978 4.217 ;
     RECT  171.972 3.307 172.062 4.261 ;
     RECT  167.472 4.157 167.562 4.379 ;
     RECT  167.472 4.379 167.49 4.415 ;
     RECT  171.576 4.261 172.062 4.649 ;
     RECT  171.828 4.649 172.062 4.651 ;
     RECT  172.8 3.299 176.526 4.651 ;
     RECT  171.828 4.651 176.526 4.829 ;
     RECT  171.828 4.829 172.062 5.845 ;
     RECT  172.8 4.829 176.526 5.845 ;
     RECT  135.648 4.217 164.697 5.881 ;
     RECT  165.492 4.217 165.978 5.881 ;
     RECT  169.815 2.413 170.802 6.007 ;
     RECT  171.828 5.845 176.526 6.007 ;
     RECT  169.815 6.007 176.526 6.539 ;
     RECT  135.648 5.881 165.978 6.691 ;
     RECT  169.815 6.539 176.49 6.691 ;
     RECT  135.648 6.691 166.194 7.079 ;
     RECT  135.648 7.079 166.05 7.655 ;
     RECT  135.864 7.655 166.05 7.925 ;
     RECT  136.368 7.925 166.05 8.159 ;
     RECT  167.04 7.231 167.058 8.311 ;
     RECT  136.368 8.159 165.978 8.735 ;
     RECT  169.74 6.691 176.49 8.815 ;
     RECT  177.66 2.911 182.502 8.815 ;
     RECT  161.892 8.735 165.978 8.941 ;
     RECT  166.86 8.311 167.058 8.941 ;
     RECT  136.368 8.735 161.154 9.691 ;
     RECT  161.892 8.941 167.058 9.691 ;
     RECT  169.74 8.815 182.502 10.831 ;
     RECT  191.415 2.413 191.697 11.131 ;
     RECT  193.536 11.101 193.554 11.165 ;
     RECT  222.3 10.987 222.318 11.165 ;
     RECT  191.415 11.131 192.654 11.171 ;
     RECT  136.368 9.691 167.058 11.281 ;
     RECT  136.368 11.281 167.094 11.371 ;
     RECT  186.015 2.413 186.297 11.371 ;
     RECT  191.415 11.171 191.697 11.371 ;
     RECT  192.636 11.171 192.654 11.399 ;
     RECT  185.904 11.371 186.297 11.408 ;
     RECT  191.304 11.371 191.697 11.408 ;
     RECT  136.368 11.371 167.49 12.389 ;
     RECT  136.368 12.389 136.386 12.427 ;
     RECT  136.188 12.427 136.386 12.479 ;
     RECT  168.624 13.243 168.642 13.565 ;
     RECT  169.74 10.831 182.574 14.521 ;
     RECT  169.74 14.521 182.646 14.909 ;
     RECT  169.74 14.909 182.502 14.945 ;
     RECT  169.74 14.945 182.322 15.449 ;
     RECT  169.74 15.449 182.25 15.521 ;
     RECT  310.215 2.413 310.497 15.871 ;
     RECT  309.672 15.871 311.238 16.105 ;
     RECT  308.052 16.069 308.142 16.141 ;
     RECT  309.06 16.105 311.238 16.141 ;
     RECT  312.768 15.871 312.894 16.141 ;
     RECT  313.704 15.871 313.722 16.141 ;
     RECT  315.615 2.413 315.897 16.141 ;
     RECT  304.815 2.413 305.097 16.231 ;
     RECT  312.768 16.141 314.01 16.231 ;
     RECT  312.552 16.231 314.01 16.303 ;
     RECT  312.48 16.303 314.37 16.339 ;
     RECT  312.408 16.339 314.37 16.375 ;
     RECT  304.815 16.231 305.478 16.405 ;
     RECT  300.924 16.267 300.942 16.411 ;
     RECT  304.128 16.405 305.478 16.411 ;
     RECT  307.98 16.141 308.142 16.411 ;
     RECT  309.06 16.141 311.49 16.411 ;
     RECT  301.86 16.411 302.094 16.501 ;
     RECT  303.48 16.411 305.478 16.501 ;
     RECT  307.836 16.411 311.49 16.501 ;
     RECT  312.336 16.375 314.37 16.501 ;
     RECT  317.196 16.411 317.214 16.501 ;
     RECT  300.924 16.411 301.086 16.573 ;
     RECT  301.86 16.501 305.478 16.573 ;
     RECT  299.415 2.413 299.697 16.609 ;
     RECT  300.924 16.573 305.514 16.609 ;
     RECT  317.196 16.501 317.394 16.645 ;
     RECT  299.415 16.609 299.754 16.681 ;
     RECT  300.816 16.609 305.514 16.681 ;
     RECT  300.744 16.681 305.514 16.799 ;
     RECT  307.836 16.501 314.37 16.799 ;
     RECT  299.415 16.681 299.79 16.807 ;
     RECT  317.088 16.645 317.394 16.807 ;
     RECT  299.415 16.807 299.826 16.879 ;
     RECT  309.06 16.799 314.37 16.879 ;
     RECT  315.144 16.141 315.897 16.879 ;
     RECT  299.376 16.879 299.898 16.915 ;
     RECT  300.744 16.799 305.478 16.915 ;
     RECT  169.74 15.521 171.342 16.951 ;
     RECT  172.188 15.521 182.25 16.951 ;
     RECT  316.872 16.807 317.394 16.951 ;
     RECT  296.496 16.267 296.514 17.041 ;
     RECT  297.396 17.041 297.414 17.077 ;
     RECT  294.015 2.413 294.297 17.113 ;
     RECT  296.496 17.041 296.658 17.113 ;
     RECT  294.015 17.113 294.678 17.149 ;
     RECT  297.396 17.077 297.558 17.149 ;
     RECT  296.352 17.113 296.658 17.185 ;
     RECT  297.396 17.149 297.774 17.185 ;
     RECT  316.62 16.951 317.394 17.185 ;
     RECT  294.015 17.149 294.966 17.221 ;
     RECT  309.06 16.879 315.897 17.221 ;
     RECT  316.62 17.185 317.466 17.221 ;
     RECT  294.015 17.221 295.614 17.311 ;
     RECT  296.352 17.185 298.17 17.311 ;
     RECT  299.376 16.915 305.478 17.339 ;
     RECT  299.376 17.339 303.57 17.383 ;
     RECT  137.124 12.389 167.49 17.455 ;
     RECT  169.74 16.951 171.378 17.455 ;
     RECT  172.188 16.951 182.502 17.455 ;
     RECT  291.492 17.419 291.51 17.491 ;
     RECT  136.764 17.455 167.49 17.501 ;
     RECT  291.42 17.491 291.51 17.581 ;
     RECT  294.015 17.311 298.17 17.581 ;
     RECT  307.836 16.799 308.25 17.581 ;
     RECT  309.06 17.221 317.682 17.581 ;
     RECT  307.836 17.581 317.682 17.651 ;
     RECT  299.268 17.383 303.57 17.653 ;
     RECT  304.596 17.339 305.478 17.761 ;
     RECT  321.015 2.413 321.297 17.761 ;
     RECT  169.74 17.455 182.502 17.851 ;
     RECT  307.908 17.651 317.682 17.887 ;
     RECT  318.456 17.185 318.474 17.887 ;
     RECT  319.752 17.761 319.77 17.887 ;
     RECT  320.616 17.761 321.297 17.887 ;
     RECT  137.16 17.501 167.49 17.915 ;
     RECT  294.015 17.581 298.242 17.959 ;
     RECT  299.196 17.653 303.57 17.959 ;
     RECT  307.908 17.887 318.474 17.995 ;
     RECT  319.752 17.887 321.297 17.995 ;
     RECT  306.576 17.581 306.594 18.031 ;
     RECT  304.596 17.761 305.838 18.121 ;
     RECT  169.74 17.851 182.682 18.149 ;
     RECT  294.015 17.959 303.57 18.187 ;
     RECT  307.908 17.995 321.297 18.221 ;
     RECT  304.452 18.121 305.838 18.229 ;
     RECT  306.576 18.031 306.774 18.229 ;
     RECT  311.832 18.221 321.297 18.257 ;
     RECT  304.452 18.229 306.774 18.265 ;
     RECT  311.868 18.257 321.297 18.265 ;
     RECT  326.016 18.193 326.034 18.265 ;
     RECT  293.904 18.187 303.57 18.301 ;
     RECT  304.308 18.265 306.774 18.301 ;
     RECT  311.868 18.265 321.318 18.329 ;
     RECT  304.308 18.301 306.954 18.391 ;
     RECT  307.908 18.221 310.698 18.391 ;
     RECT  304.308 18.391 310.698 18.419 ;
     RECT  169.74 18.149 182.43 18.455 ;
     RECT  293.868 18.301 303.57 18.455 ;
     RECT  304.308 18.419 309.222 18.535 ;
     RECT  311.94 18.329 321.318 18.535 ;
     RECT  325.728 18.265 326.034 18.535 ;
     RECT  169.776 18.455 182.43 18.689 ;
     RECT  311.94 18.535 321.39 18.689 ;
     RECT  322.74 18.661 322.758 18.697 ;
     RECT  323.856 18.301 323.874 18.697 ;
     RECT  325.26 18.535 326.034 18.697 ;
     RECT  311.94 18.689 321.297 18.725 ;
     RECT  322.74 18.697 324.378 18.733 ;
     RECT  325.188 18.697 326.034 18.733 ;
     RECT  322.74 18.733 326.034 18.763 ;
     RECT  243.036 3.883 243.054 18.841 ;
     RECT  290.808 17.581 291.51 18.841 ;
     RECT  293.868 18.455 303.534 18.841 ;
     RECT  312.084 18.725 321.297 18.845 ;
     RECT  290.124 18.841 291.51 18.959 ;
     RECT  293.256 18.841 303.534 18.959 ;
     RECT  292.428 17.383 292.446 18.967 ;
     RECT  293.256 18.959 293.274 18.967 ;
     RECT  304.272 18.535 309.222 19.031 ;
     RECT  292.428 18.967 293.274 19.103 ;
     RECT  312.12 18.845 321.297 19.103 ;
     RECT  292.428 19.103 293.202 19.111 ;
     RECT  290.196 18.959 291.51 19.195 ;
     RECT  292.284 19.111 293.202 19.195 ;
     RECT  242.856 18.841 243.054 19.229 ;
     RECT  319.752 19.103 321.297 19.229 ;
     RECT  322.56 18.763 326.034 19.229 ;
     RECT  169.776 18.689 182.394 19.301 ;
     RECT  290.196 19.195 293.202 19.373 ;
     RECT  322.56 19.229 325.998 19.381 ;
     RECT  294.015 18.959 303.534 19.387 ;
     RECT  304.272 19.031 308.754 19.387 ;
     RECT  319.824 19.229 321.297 19.409 ;
     RECT  241.164 19.381 241.182 19.499 ;
     RECT  244.044 4.189 244.062 19.499 ;
     RECT  312.12 19.103 319.014 19.579 ;
     RECT  322.236 19.381 325.998 19.579 ;
     RECT  244.116 19.507 244.134 19.607 ;
     RECT  327.204 19.003 327.222 19.615 ;
     RECT  320.94 19.409 321.297 19.651 ;
     RECT  322.02 19.579 325.998 19.651 ;
     RECT  242.244 19.579 242.262 19.679 ;
     RECT  290.196 19.373 293.058 19.679 ;
     RECT  284.724 19.507 284.742 19.769 ;
     RECT  294.015 19.387 308.754 19.877 ;
     RECT  284.616 19.867 284.634 19.913 ;
     RECT  297 19.877 308.754 19.921 ;
     RECT  297 19.921 308.79 19.949 ;
     RECT  309.996 18.419 310.626 20.011 ;
     RECT  311.94 19.579 319.014 20.011 ;
     RECT  243.36 19.651 243.378 20.039 ;
     RECT  328.176 19.039 328.194 20.045 ;
     RECT  297.144 19.949 308.79 20.047 ;
     RECT  288.615 2.413 288.897 20.059 ;
     RECT  297.144 20.047 309.006 20.059 ;
     RECT  309.996 20.011 310.662 20.059 ;
     RECT  319.824 19.409 319.878 20.149 ;
     RECT  327.204 19.615 327.258 20.155 ;
     RECT  285.804 20.107 285.822 20.183 ;
     RECT  319.824 20.149 320.166 20.191 ;
     RECT  320.94 19.651 325.998 20.191 ;
     RECT  169.776 19.301 182.034 20.309 ;
     RECT  311.832 20.011 319.014 20.317 ;
     RECT  311.724 20.317 319.014 20.395 ;
     RECT  319.824 20.191 325.998 20.425 ;
     RECT  327.204 20.155 327.294 20.425 ;
     RECT  297.144 20.059 310.662 20.453 ;
     RECT  290.196 19.679 292.806 20.461 ;
     RECT  294.015 19.877 296.226 20.461 ;
     RECT  301.752 20.453 310.662 20.461 ;
     RECT  311.724 20.395 319.086 20.461 ;
     RECT  290.196 20.461 292.986 20.659 ;
     RECT  293.76 20.461 296.226 20.659 ;
     RECT  301.752 20.461 319.086 20.687 ;
     RECT  290.088 20.659 296.226 20.695 ;
     RECT  297.144 20.453 300.978 20.695 ;
     RECT  288.615 20.059 289.098 20.731 ;
     RECT  319.824 20.425 327.294 20.909 ;
     RECT  315.576 20.687 319.086 20.965 ;
     RECT  319.824 20.909 327.222 20.965 ;
     RECT  172.548 20.309 182.034 21.001 ;
     RECT  288.615 20.731 289.314 21.127 ;
     RECT  290.088 20.695 300.978 21.127 ;
     RECT  169.776 20.309 171.81 21.235 ;
     RECT  172.548 21.001 182.718 21.235 ;
     RECT  301.752 20.687 314.838 21.235 ;
     RECT  169.776 21.235 182.718 21.389 ;
     RECT  301.716 21.235 314.838 21.497 ;
     RECT  288.615 21.127 300.978 21.541 ;
     RECT  301.716 21.497 314.226 21.541 ;
     RECT  315.576 20.965 327.222 21.667 ;
     RECT  288.615 21.541 314.226 21.787 ;
     RECT  246.78 21.739 246.798 21.811 ;
     RECT  315.288 21.667 327.222 21.839 ;
     RECT  169.776 21.389 182.538 21.929 ;
     RECT  315.324 21.839 327.222 21.929 ;
     RECT  222.408 11.281 222.426 21.965 ;
     RECT  315.612 21.929 319.806 21.965 ;
     RECT  288.432 21.787 314.226 22.013 ;
     RECT  250.815 2.413 251.097 22.027 ;
     RECT  320.904 21.929 327.222 22.027 ;
     RECT  328.212 20.203 328.23 22.027 ;
     RECT  169.02 18.697 169.038 22.045 ;
     RECT  249.012 21.787 249.03 22.045 ;
     RECT  261.615 2.413 261.897 22.072 ;
     RECT  272.415 2.413 272.697 22.072 ;
     RECT  283.215 2.413 283.497 22.072 ;
     RECT  137.415 17.915 167.49 22.081 ;
     RECT  168.336 22.045 169.038 22.081 ;
     RECT  248.436 22.045 249.03 22.081 ;
     RECT  320.904 22.027 328.23 22.157 ;
     RECT  246.528 21.811 246.798 22.199 ;
     RECT  248.436 22.081 249.102 22.199 ;
     RECT  250.815 22.027 251.622 22.199 ;
     RECT  286.164 21.787 286.182 22.219 ;
     RECT  288.432 22.013 314.19 22.243 ;
     RECT  248.868 22.199 249.102 22.267 ;
     RECT  137.415 22.081 169.038 22.279 ;
     RECT  169.776 21.929 182.106 22.279 ;
     RECT  250.815 22.199 251.154 22.315 ;
     RECT  281.808 22.207 281.826 22.315 ;
     RECT  272.304 22.072 272.697 22.351 ;
     RECT  285.876 22.219 286.182 22.351 ;
     RECT  287.532 22.315 287.55 22.351 ;
     RECT  244.044 22.315 244.062 22.441 ;
     RECT  214.776 22.351 214.794 22.469 ;
     RECT  244.044 22.441 244.53 22.469 ;
     RECT  271.26 22.081 271.278 22.469 ;
     RECT  186.015 11.408 186.297 22.477 ;
     RECT  272.16 22.351 272.697 22.477 ;
     RECT  285.876 22.351 286.218 22.477 ;
     RECT  244.512 22.469 244.53 22.493 ;
     RECT  250.236 22.315 251.154 22.505 ;
     RECT  271.116 22.477 271.134 22.541 ;
     RECT  319.788 21.965 319.806 22.541 ;
     RECT  287.352 22.351 287.55 22.549 ;
     RECT  242.244 22.477 242.262 22.577 ;
     RECT  250.815 22.505 251.154 22.577 ;
     RECT  281.628 22.315 282.222 22.585 ;
     RECT  284.868 22.513 284.886 22.585 ;
     RECT  287.352 22.549 287.622 22.585 ;
     RECT  320.904 22.157 327.186 22.613 ;
     RECT  283.104 22.072 283.497 22.621 ;
     RECT  284.292 22.585 284.886 22.621 ;
     RECT  261.504 22.072 261.897 22.649 ;
     RECT  281.124 22.585 282.222 22.649 ;
     RECT  283.104 22.621 284.886 22.649 ;
     RECT  248.868 22.267 249.462 22.739 ;
     RECT  283.215 22.649 284.886 22.739 ;
     RECT  285.732 22.477 286.218 22.739 ;
     RECT  285.804 22.739 286.218 22.747 ;
     RECT  287.028 22.585 287.622 22.747 ;
     RECT  271.908 22.477 272.697 22.775 ;
     RECT  247.752 22.747 247.77 22.795 ;
     RECT  320.904 22.613 326.61 22.811 ;
     RECT  137.415 22.279 182.106 22.819 ;
     RECT  186.015 22.477 186.534 22.819 ;
     RECT  245.415 2.413 245.697 22.843 ;
     RECT  288.396 22.243 314.19 22.855 ;
     RECT  283.215 22.739 284.31 22.883 ;
     RECT  137.415 22.819 182.43 22.891 ;
     RECT  288.396 22.855 314.442 22.891 ;
     RECT  315.612 21.965 319.014 22.891 ;
     RECT  186.015 22.819 187.002 22.919 ;
     RECT  186.015 22.919 186.93 22.981 ;
     RECT  281.124 22.649 282.186 22.981 ;
     RECT  285.804 22.747 287.622 22.981 ;
     RECT  245.415 22.843 246.222 23.009 ;
     RECT  247.176 22.795 247.77 23.009 ;
     RECT  253.008 22.891 253.026 23.009 ;
     RECT  283.215 22.883 284.058 23.009 ;
     RECT  288.396 22.891 319.014 23.009 ;
     RECT  320.904 22.811 326.43 23.009 ;
     RECT  185.364 22.981 186.93 23.017 ;
     RECT  280.584 22.981 282.186 23.021 ;
     RECT  294.015 23.009 319.014 23.035 ;
     RECT  294.015 23.035 319.194 23.045 ;
     RECT  196.815 2.413 197.097 23.053 ;
     RECT  248.868 22.739 249.066 23.08 ;
     RECT  281.124 23.021 282.186 23.081 ;
     RECT  285.804 22.981 287.658 23.081 ;
     RECT  287.46 23.081 287.658 23.083 ;
     RECT  288.396 23.009 293.058 23.083 ;
     RECT  248.472 23.08 249.066 23.117 ;
     RECT  286.164 23.081 286.326 23.117 ;
     RECT  322.056 23.009 326.43 23.153 ;
     RECT  0.504 23.089 0.522 23.161 ;
     RECT  277.815 2.413 278.097 23.161 ;
     RECT  185.292 23.017 186.93 23.189 ;
     RECT  281.16 23.081 282.186 23.189 ;
     RECT  185.292 23.189 186.858 23.251 ;
     RECT  230.292 23.089 230.31 23.251 ;
     RECT  185.148 23.251 186.858 23.279 ;
     RECT  230.292 23.251 230.418 23.279 ;
     RECT  231.228 23.089 231.246 23.279 ;
     RECT  294.015 23.045 314.622 23.279 ;
     RECT  320.904 23.009 321.297 23.287 ;
     RECT  295.308 23.279 296.514 23.309 ;
     RECT  277.815 23.161 278.19 23.315 ;
     RECT  281.52 23.189 282.186 23.315 ;
     RECT  287.46 23.083 293.058 23.315 ;
     RECT  0.504 23.161 0.558 23.323 ;
     RECT  185.148 23.279 186.786 23.323 ;
     RECT  134.532 22.351 134.55 23.351 ;
     RECT  184.968 23.323 186.786 23.351 ;
     RECT  230.4 23.279 230.418 23.351 ;
     RECT  297.36 23.279 314.622 23.351 ;
     RECT  137.415 22.891 182.502 23.359 ;
     RECT  184.968 23.351 186.678 23.359 ;
     RECT  234.615 2.413 234.897 23.359 ;
     RECT  328.032 22.157 328.23 23.371 ;
     RECT  311.436 23.351 314.622 23.405 ;
     RECT  250.815 22.577 251.097 23.419 ;
     RECT  183.492 23.161 183.51 23.431 ;
     RECT  184.86 23.359 186.678 23.431 ;
     RECT  234.396 23.359 234.897 23.431 ;
     RECT  245.415 23.009 245.826 23.431 ;
     RECT  230.472 23.359 230.49 23.459 ;
     RECT  191.415 11.408 191.697 23.515 ;
     RECT  315.615 23.045 319.194 23.515 ;
     RECT  240.015 2.413 240.297 23.521 ;
     RECT  241.128 23.125 241.146 23.521 ;
     RECT  183.492 23.431 186.678 23.549 ;
     RECT  232.272 23.371 232.29 23.549 ;
     RECT  240.015 23.521 241.146 23.549 ;
     RECT  249.984 23.275 250.002 23.549 ;
     RECT  297.36 23.351 298.458 23.549 ;
     RECT  191.415 23.515 191.79 23.555 ;
     RECT  315.615 23.515 319.446 23.557 ;
     RECT  79.128 22.351 79.146 23.563 ;
     RECT  183.492 23.549 184.914 23.585 ;
     RECT  0.468 23.323 0.558 23.593 ;
     RECT  315.615 23.557 319.518 23.593 ;
     RECT  320.292 23.287 321.297 23.593 ;
     RECT  249.048 23.117 249.066 23.597 ;
     RECT  250.815 23.419 251.19 23.597 ;
     RECT  137.415 23.359 182.574 23.621 ;
     RECT  287.82 23.315 293.058 23.621 ;
     RECT  183.492 23.585 183.582 23.629 ;
     RECT  240.015 23.549 240.678 23.645 ;
     RECT  231.948 23.611 231.966 23.657 ;
     RECT  234.324 23.431 234.897 23.657 ;
     RECT  294.015 23.279 294.354 23.657 ;
     RECT  288.216 23.621 293.058 23.693 ;
     RECT  311.544 23.405 314.622 23.693 ;
     RECT  250.815 23.597 251.097 23.701 ;
     RECT  327.888 23.371 328.23 23.701 ;
     RECT  288.216 23.693 292.986 23.729 ;
     RECT  295.308 23.309 296.442 23.729 ;
     RECT  183.456 23.629 183.582 23.741 ;
     RECT  295.308 23.729 296.406 23.741 ;
     RECT  0.396 23.593 0.558 23.789 ;
     RECT  196.815 23.053 197.226 23.791 ;
     RECT  207.615 2.413 207.897 23.791 ;
     RECT  218.415 2.413 218.697 23.791 ;
     RECT  229.215 2.413 229.497 23.791 ;
     RECT  261.615 22.649 261.897 23.791 ;
     RECT  272.415 22.775 272.697 23.791 ;
     RECT  283.215 23.009 283.497 23.791 ;
     RECT  315.615 23.593 321.297 23.791 ;
     RECT  79.128 23.563 79.362 23.819 ;
     RECT  184.428 23.585 184.914 23.819 ;
     RECT  185.904 23.549 186.678 23.819 ;
     RECT  242.856 23.659 242.874 23.819 ;
     RECT  245.232 23.431 245.826 23.819 ;
     RECT  247.356 23.009 247.374 23.819 ;
     RECT  295.344 23.741 296.406 23.819 ;
     RECT  311.94 23.693 314.622 23.819 ;
     RECT  183.564 23.741 183.582 23.837 ;
     RECT  184.428 23.819 184.842 23.837 ;
     RECT  196.704 23.791 197.226 23.837 ;
     RECT  207.504 23.791 207.897 23.837 ;
     RECT  218.304 23.791 218.697 23.837 ;
     RECT  229.104 23.791 229.497 23.837 ;
     RECT  261.504 23.791 261.897 23.837 ;
     RECT  272.304 23.791 272.697 23.837 ;
     RECT  283.104 23.791 283.497 23.837 ;
     RECT  286.164 23.117 286.29 23.837 ;
     RECT  184.428 23.837 184.77 23.855 ;
     RECT  240.015 23.645 240.354 23.863 ;
     RECT  0.396 23.789 0.522 23.885 ;
     RECT  179.928 23.621 182.574 23.891 ;
     RECT  239.4 23.863 240.354 23.891 ;
     RECT  246.852 23.851 246.87 23.891 ;
     RECT  295.884 23.819 296.406 23.891 ;
     RECT  322.056 23.153 326.394 23.899 ;
     RECT  327.204 23.701 328.23 23.899 ;
     RECT  179.928 23.891 182.538 23.927 ;
     RECT  186.015 23.819 186.678 23.927 ;
     RECT  196.815 23.837 197.226 23.933 ;
     RECT  238.284 23.803 238.302 23.933 ;
     RECT  286.164 23.837 286.254 23.933 ;
     RECT  315.504 23.791 321.297 23.935 ;
     RECT  322.056 23.899 328.23 23.935 ;
     RECT  313.992 23.819 314.622 23.971 ;
     RECT  315.504 23.935 328.23 23.971 ;
     RECT  0.396 23.885 0.486 23.981 ;
     RECT  288.216 23.729 292.95 23.981 ;
     RECT  252.936 23.161 252.954 23.999 ;
     RECT  313.992 23.971 328.23 23.999 ;
     RECT  0.396 23.981 0.45 24.077 ;
     RECT  299.415 23.351 307.242 24.133 ;
     RECT  307.98 23.351 310.662 24.133 ;
     RECT  72.615 2.413 72.897 24.139 ;
     RECT  2.415 2.413 2.697 24.232 ;
     RECT  13.215 2.413 13.497 24.232 ;
     RECT  24.015 2.413 24.297 24.232 ;
     RECT  34.815 2.413 35.097 24.232 ;
     RECT  45.615 2.413 45.897 24.232 ;
     RECT  56.415 2.413 56.697 24.232 ;
     RECT  67.215 2.413 67.497 24.232 ;
     RECT  78.015 2.413 78.297 24.232 ;
     RECT  88.815 2.413 89.097 24.232 ;
     RECT  99.615 2.413 99.897 24.232 ;
     RECT  110.415 2.413 110.697 24.232 ;
     RECT  121.215 2.413 121.497 24.232 ;
     RECT  132.015 2.413 132.297 24.232 ;
     RECT  72.144 24.139 72.897 24.235 ;
     RECT  250.236 23.701 251.097 24.269 ;
     RECT  288.432 23.981 292.95 24.359 ;
     RECT  299.415 24.133 310.662 24.359 ;
     RECT  134.568 24.241 134.586 24.379 ;
     RECT  137.415 23.621 179.19 24.395 ;
     RECT  299.415 24.359 303.57 24.395 ;
     RECT  3.42 24.367 3.438 24.403 ;
     RECT  297.36 23.549 298.35 24.403 ;
     RECT  134.532 24.379 134.586 24.431 ;
     RECT  311.94 23.819 313.254 24.467 ;
     RECT  0.396 24.077 0.414 24.475 ;
     RECT  239.4 23.891 240.297 24.503 ;
     RECT  314.064 23.999 328.23 24.503 ;
     RECT  288.468 24.359 292.95 24.509 ;
     RECT  288.615 24.509 292.95 24.511 ;
     RECT  294.015 23.657 294.297 24.511 ;
     RECT  304.488 24.359 310.662 24.511 ;
     RECT  304.488 24.511 311.094 24.601 ;
     RECT  311.94 24.467 313.218 24.601 ;
     RECT  72 24.235 72.897 24.619 ;
     RECT  295.776 24.601 295.794 24.619 ;
     RECT  137.415 24.395 161.55 24.629 ;
     RECT  288.615 24.511 294.297 24.629 ;
     RECT  295.632 24.619 295.794 24.637 ;
     RECT  288.615 24.629 293.022 24.653 ;
     RECT  319.752 24.503 328.23 24.653 ;
     RECT  71.964 24.619 72.897 24.665 ;
     RECT  295.524 24.637 295.794 24.673 ;
     RECT  299.415 24.395 301.302 24.673 ;
     RECT  289.62 24.653 293.022 24.701 ;
     RECT  304.488 24.601 313.218 24.701 ;
     RECT  294.015 24.629 294.297 24.709 ;
     RECT  295.38 24.673 295.794 24.737 ;
     RECT  162.324 24.395 179.19 24.745 ;
     RECT  179.928 23.927 181.89 24.745 ;
     RECT  294.015 24.709 294.606 24.745 ;
     RECT  295.38 24.737 295.722 24.745 ;
     RECT  297.36 24.403 298.494 24.745 ;
     RECT  299.376 24.673 301.302 24.745 ;
     RECT  186.015 23.927 186.297 24.763 ;
     RECT  196.815 23.933 197.097 24.763 ;
     RECT  207.615 23.837 207.897 24.763 ;
     RECT  218.415 23.837 218.697 24.763 ;
     RECT  229.215 23.837 229.497 24.763 ;
     RECT  261.615 23.837 261.897 24.763 ;
     RECT  272.415 23.837 272.697 24.763 ;
     RECT  283.215 23.837 283.497 24.763 ;
     RECT  77.904 24.232 78.297 24.781 ;
     RECT  88.704 24.232 89.097 24.797 ;
     RECT  99.504 24.232 99.897 24.797 ;
     RECT  110.304 24.232 110.697 24.797 ;
     RECT  121.104 24.232 121.497 24.797 ;
     RECT  131.904 24.232 132.297 24.797 ;
     RECT  286.164 23.933 286.182 24.797 ;
     RECT  13.104 24.232 13.497 24.809 ;
     RECT  23.904 24.232 24.297 24.809 ;
     RECT  34.704 24.232 35.097 24.809 ;
     RECT  45.504 24.232 45.897 24.809 ;
     RECT  56.304 24.232 56.697 24.809 ;
     RECT  67.104 24.232 67.497 24.809 ;
     RECT  185.904 24.763 186.297 24.809 ;
     RECT  196.704 24.763 197.097 24.809 ;
     RECT  207.504 24.763 207.897 24.809 ;
     RECT  218.304 24.763 218.697 24.809 ;
     RECT  229.104 24.763 229.497 24.809 ;
     RECT  239.904 24.503 240.297 24.809 ;
     RECT  250.704 24.269 251.097 24.809 ;
     RECT  261.504 24.763 261.897 24.809 ;
     RECT  272.304 24.763 272.697 24.809 ;
     RECT  283.104 24.763 283.497 24.809 ;
     RECT  304.488 24.701 312.93 24.809 ;
     RECT  328.212 24.653 328.23 24.809 ;
     RECT  0.108 24.475 0.414 24.871 ;
     RECT  77.724 24.781 78.297 24.899 ;
     RECT  294.015 24.745 295.722 24.899 ;
     RECT  297.36 24.745 301.302 24.899 ;
     RECT  134.532 24.431 134.55 24.935 ;
     RECT  297.36 24.899 297.918 24.941 ;
     RECT  299.34 24.899 301.302 24.941 ;
     RECT  314.064 24.503 319.014 24.943 ;
     RECT  3.42 24.403 3.51 24.971 ;
     RECT  77.94 24.899 78.297 24.971 ;
     RECT  0.108 24.871 0.522 24.979 ;
     RECT  2.304 24.232 2.697 24.979 ;
     RECT  3.42 24.971 3.438 24.979 ;
     RECT  2.304 24.979 3.438 24.989 ;
     RECT  295.2 24.899 295.398 25.007 ;
     RECT  302.076 24.395 303.57 25.007 ;
     RECT  290.124 24.701 292.806 25.037 ;
     RECT  294.015 24.899 294.462 25.043 ;
     RECT  295.2 25.007 295.218 25.043 ;
     RECT  299.415 24.941 301.302 25.043 ;
     RECT  2.304 24.989 2.862 25.079 ;
     RECT  299.415 25.043 300.474 25.079 ;
     RECT  313.992 24.943 319.014 25.085 ;
     RECT  319.752 24.653 327.222 25.133 ;
     RECT  299.415 25.079 300.438 25.169 ;
     RECT  301.212 25.043 301.302 25.169 ;
     RECT  304.488 24.809 306.702 25.169 ;
     RECT  299.415 25.169 300.294 25.205 ;
     RECT  316.62 25.085 319.014 25.205 ;
     RECT  0.108 24.979 0.558 25.229 ;
     RECT  299.415 25.205 299.79 25.241 ;
     RECT  304.488 25.169 305.766 25.243 ;
     RECT  302.58 25.007 303.57 25.249 ;
     RECT  304.38 25.243 305.766 25.249 ;
     RECT  0.18 25.229 0.558 25.277 ;
     RECT  302.58 25.249 305.766 25.277 ;
     RECT  138.744 24.629 161.55 25.285 ;
     RECT  316.692 25.205 319.014 25.285 ;
     RECT  319.752 25.133 327.186 25.285 ;
     RECT  138.744 25.285 161.586 25.321 ;
     RECT  162.324 24.745 181.89 25.321 ;
     RECT  307.656 24.809 312.93 25.349 ;
     RECT  316.692 25.285 327.186 25.349 ;
     RECT  0.504 25.277 0.558 25.411 ;
     RECT  321.015 25.349 327.186 25.421 ;
     RECT  307.656 25.349 312.858 25.439 ;
     RECT  313.992 25.085 315.897 25.439 ;
     RECT  316.692 25.349 320.166 25.439 ;
     RECT  0.504 25.411 0.63 25.469 ;
     RECT  76.608 25.321 76.986 25.469 ;
     RECT  297.36 24.941 297.378 25.475 ;
     RECT  301.572 25.321 301.59 25.475 ;
     RECT  76.608 25.469 76.626 25.511 ;
     RECT  0.504 25.469 0.522 25.517 ;
     RECT  313.992 25.439 314.622 25.531 ;
     RECT  319.608 25.439 320.166 25.547 ;
     RECT  307.656 25.439 312.426 25.583 ;
     RECT  313.884 25.531 314.622 25.583 ;
     RECT  316.692 25.439 318.87 25.583 ;
     RECT  319.608 25.547 319.626 25.583 ;
     RECT  326.592 25.421 327.186 25.619 ;
     RECT  138.744 25.321 182.394 25.681 ;
     RECT  290.124 25.037 292.698 25.709 ;
     RECT  302.58 25.277 305.097 25.709 ;
     RECT  327.168 25.619 327.186 25.709 ;
     RECT  302.58 25.709 302.886 25.745 ;
     RECT  321.015 25.421 325.386 25.745 ;
     RECT  307.656 25.583 312.39 25.781 ;
     RECT  308.592 25.781 312.39 25.805 ;
     RECT  316.692 25.583 317.466 25.853 ;
     RECT  138.744 25.681 182.466 25.979 ;
     RECT  290.124 25.709 292.41 25.979 ;
     RECT  302.58 25.745 302.598 25.979 ;
     RECT  304.38 25.709 305.097 25.979 ;
     RECT  316.692 25.853 317.286 25.979 ;
     RECT  322.056 25.745 325.386 25.979 ;
     RECT  315.615 25.439 315.897 26.011 ;
     RECT  290.124 25.979 292.338 26.015 ;
     RECT  315.615 26.011 316.314 26.051 ;
     RECT  308.592 25.805 312.354 26.087 ;
     RECT  317.124 25.979 317.214 26.087 ;
     RECT  307.656 25.781 307.674 26.093 ;
     RECT  310.215 26.087 311.094 26.093 ;
     RECT  138.744 25.979 161.586 26.123 ;
     RECT  290.124 26.015 292.122 26.123 ;
     RECT  308.592 26.087 308.61 26.123 ;
     RECT  309.348 26.087 309.366 26.123 ;
     RECT  312.336 26.087 312.354 26.123 ;
     RECT  317.196 26.087 317.214 26.123 ;
     RECT  322.596 25.979 324.81 26.159 ;
     RECT  162.324 25.979 181.89 26.249 ;
     RECT  322.596 26.159 324.27 26.249 ;
     RECT  163.188 26.249 181.89 26.285 ;
     RECT  291.528 26.123 292.122 26.285 ;
     RECT  322.596 26.249 324.162 26.285 ;
     RECT  323.136 26.285 323.154 26.321 ;
     RECT  291.528 26.285 291.546 26.357 ;
     RECT  290.7 26.123 290.718 26.429 ;
     RECT  138.744 26.123 161.406 27.481 ;
     RECT  162.324 26.249 162.342 27.481 ;
     RECT  163.188 26.285 181.782 27.635 ;
     RECT  163.44 27.635 181.782 28.139 ;
     RECT  138.744 27.481 162.342 28.795 ;
     RECT  138.6 28.795 162.342 28.831 ;
     RECT  138.6 28.831 162.486 29.069 ;
     RECT  138.924 29.069 162.486 29.371 ;
     RECT  163.44 28.139 181.566 29.371 ;
     RECT  138.924 29.371 181.566 29.789 ;
     RECT  163.44 29.789 181.566 30.029 ;
     RECT  138.924 29.789 162.702 30.065 ;
     RECT  163.44 30.029 181.422 31.291 ;
     RECT  163.26 31.291 181.422 31.927 ;
     RECT  163.26 31.927 181.566 31.955 ;
     RECT  163.44 31.955 181.566 32.459 ;
     RECT  163.44 32.459 181.422 33.539 ;
     RECT  163.44 33.539 179.766 33.719 ;
     RECT  138.924 30.065 162.342 33.845 ;
     RECT  163.44 33.719 179.694 33.917 ;
     RECT  184.428 23.855 184.446 34.259 ;
     RECT  180.615 33.539 181.422 34.349 ;
     RECT  180.615 34.349 180.897 34.357 ;
     RECT  180.432 34.357 180.897 34.397 ;
     RECT  139.104 33.845 162.342 34.603 ;
     RECT  180.576 34.397 180.897 34.685 ;
     RECT  139.104 34.603 162.486 34.733 ;
     RECT  139.104 34.733 162.342 35.851 ;
     RECT  163.44 33.917 178.398 35.885 ;
     RECT  163.44 35.885 173.826 36.239 ;
     RECT  171.936 36.239 173.826 36.625 ;
     RECT  174.672 35.885 178.398 36.625 ;
     RECT  139.104 35.851 162.378 37.021 ;
     RECT  171.936 36.625 178.398 37.049 ;
     RECT  139.104 37.021 162.594 37.085 ;
     RECT  139.32 37.085 162.594 37.589 ;
     RECT  163.44 36.239 170.946 37.741 ;
     RECT  163.368 37.741 170.946 38.371 ;
     RECT  171.936 37.049 177.93 38.371 ;
     RECT  163.368 38.371 177.93 38.399 ;
     RECT  139.392 37.589 162.486 38.551 ;
     RECT  163.368 38.399 172.638 38.551 ;
     RECT  173.448 38.399 177.93 38.635 ;
     RECT  173.448 38.635 178.11 38.641 ;
     RECT  179.172 33.917 179.694 38.669 ;
     RECT  139.392 38.551 172.638 38.939 ;
     RECT  179.28 38.669 179.694 38.939 ;
     RECT  173.448 38.641 178.218 39.055 ;
     RECT  173.448 39.055 178.506 39.209 ;
     RECT  180.615 34.685 180.897 39.355 ;
     RECT  180.468 39.355 180.897 39.865 ;
     RECT  180.324 39.865 180.897 39.917 ;
     RECT  139.392 38.939 154.17 40.639 ;
     RECT  155.16 38.939 172.638 40.639 ;
     RECT  174.672 39.209 178.506 41.819 ;
     RECT  139.392 40.639 172.638 42.359 ;
     RECT  155.16 42.359 172.638 42.449 ;
     RECT  155.16 42.449 172.134 43.339 ;
     RECT  173.448 39.209 173.826 43.529 ;
     RECT  139.392 42.359 154.386 43.609 ;
     RECT  155.16 43.339 172.458 43.609 ;
     RECT  139.392 43.609 172.458 43.681 ;
     RECT  139.392 43.681 172.638 43.799 ;
     RECT  139.392 43.799 171.99 44.105 ;
     RECT  139.428 44.105 171.99 44.141 ;
     RECT  139.428 44.141 171.558 44.339 ;
     RECT  174.708 41.819 178.506 44.443 ;
     RECT  179.28 38.939 179.514 44.443 ;
     RECT  180.615 39.917 180.897 44.443 ;
     RECT  173.448 43.529 173.466 44.519 ;
     RECT  174.708 44.443 180.897 44.879 ;
     RECT  174.708 44.879 178.578 44.915 ;
     RECT  179.316 44.879 179.55 44.915 ;
     RECT  2.415 25.079 2.697 45.107 ;
     RECT  7.815 2.413 8.097 45.107 ;
     RECT  13.215 24.809 13.497 45.107 ;
     RECT  18.615 2.413 18.897 45.107 ;
     RECT  24.015 24.809 24.297 45.107 ;
     RECT  29.415 2.413 29.697 45.107 ;
     RECT  34.815 24.809 35.097 45.107 ;
     RECT  40.215 2.413 40.497 45.107 ;
     RECT  45.615 24.809 45.897 45.107 ;
     RECT  51.015 2.413 51.297 45.107 ;
     RECT  56.415 24.809 56.697 45.107 ;
     RECT  61.815 2.413 62.097 45.107 ;
     RECT  67.215 24.809 67.497 45.107 ;
     RECT  72.615 24.665 72.897 45.107 ;
     RECT  78.015 24.971 78.297 45.107 ;
     RECT  83.415 2.413 83.697 45.107 ;
     RECT  88.815 24.797 89.097 45.107 ;
     RECT  94.215 2.413 94.497 45.107 ;
     RECT  99.615 24.797 99.897 45.107 ;
     RECT  105.015 2.413 105.297 45.107 ;
     RECT  110.415 24.797 110.697 45.107 ;
     RECT  115.815 2.413 116.097 45.107 ;
     RECT  121.215 24.797 121.497 45.107 ;
     RECT  126.615 2.413 126.897 45.107 ;
     RECT  132.015 24.797 132.297 45.107 ;
     RECT  137.415 24.629 137.697 45.107 ;
     RECT  180.615 44.879 180.897 45.107 ;
     RECT  186.015 24.809 186.297 45.107 ;
     RECT  191.415 23.555 191.697 45.107 ;
     RECT  196.815 24.809 197.097 45.107 ;
     RECT  202.215 2.413 202.497 45.107 ;
     RECT  207.615 24.809 207.897 45.107 ;
     RECT  213.015 2.413 213.297 45.107 ;
     RECT  218.415 24.809 218.697 45.107 ;
     RECT  223.815 2.413 224.097 45.107 ;
     RECT  229.215 24.809 229.497 45.107 ;
     RECT  234.615 23.657 234.897 45.107 ;
     RECT  240.015 24.809 240.297 45.107 ;
     RECT  245.415 23.819 245.697 45.107 ;
     RECT  250.815 24.809 251.097 45.107 ;
     RECT  256.215 2.413 256.497 45.107 ;
     RECT  261.615 24.809 261.897 45.107 ;
     RECT  267.015 2.413 267.297 45.107 ;
     RECT  272.415 24.809 272.697 45.107 ;
     RECT  277.815 23.315 278.097 45.107 ;
     RECT  283.215 24.809 283.497 45.107 ;
     RECT  288.615 24.653 288.897 45.107 ;
     RECT  294.015 25.043 294.297 45.107 ;
     RECT  299.415 25.241 299.697 45.107 ;
     RECT  304.815 25.979 305.097 45.107 ;
     RECT  310.215 26.093 310.497 45.107 ;
     RECT  315.615 26.051 315.897 45.107 ;
     RECT  321.015 25.745 321.297 45.107 ;
     RECT  139.428 44.339 171.522 45.149 ;
     RECT  179.496 44.915 179.55 45.149 ;
     RECT  139.428 45.149 171.45 45.185 ;
     RECT  139.428 45.185 170.91 45.257 ;
     RECT  179.532 45.149 179.55 45.293 ;
     RECT  174.708 44.915 178.506 45.329 ;
     RECT  152.712 45.257 170.91 45.341 ;
     RECT  2.415 45.107 2.505 45.377 ;
     RECT  7.815 45.107 7.905 45.377 ;
     RECT  13.215 45.107 13.305 45.377 ;
     RECT  18.615 45.107 18.705 45.377 ;
     RECT  24.015 45.107 24.105 45.377 ;
     RECT  29.415 45.107 29.505 45.377 ;
     RECT  34.815 45.107 34.905 45.377 ;
     RECT  40.215 45.107 40.305 45.377 ;
     RECT  45.615 45.107 45.705 45.377 ;
     RECT  51.015 45.107 51.105 45.377 ;
     RECT  56.415 45.107 56.505 45.377 ;
     RECT  61.815 45.107 61.905 45.377 ;
     RECT  67.215 45.107 67.305 45.377 ;
     RECT  72.615 45.107 72.705 45.377 ;
     RECT  78.015 45.107 78.105 45.377 ;
     RECT  83.415 45.107 83.505 45.377 ;
     RECT  88.815 45.107 88.905 45.377 ;
     RECT  94.215 45.107 94.305 45.377 ;
     RECT  99.615 45.107 99.705 45.377 ;
     RECT  105.015 45.107 105.105 45.377 ;
     RECT  110.415 45.107 110.505 45.377 ;
     RECT  115.815 45.107 115.905 45.377 ;
     RECT  121.215 45.107 121.305 45.377 ;
     RECT  126.615 45.107 126.705 45.377 ;
     RECT  132.015 45.107 132.105 45.377 ;
     RECT  137.415 45.107 137.505 45.377 ;
     RECT  152.712 45.341 164.505 45.377 ;
     RECT  175.215 45.329 178.506 45.377 ;
     RECT  180.615 45.107 180.705 45.377 ;
     RECT  186.015 45.107 186.105 45.377 ;
     RECT  191.415 45.107 191.505 45.377 ;
     RECT  196.815 45.107 196.905 45.377 ;
     RECT  202.215 45.107 202.305 45.377 ;
     RECT  207.615 45.107 207.705 45.377 ;
     RECT  213.015 45.107 213.105 45.377 ;
     RECT  218.415 45.107 218.505 45.377 ;
     RECT  223.815 45.107 223.905 45.377 ;
     RECT  229.215 45.107 229.305 45.377 ;
     RECT  234.615 45.107 234.705 45.377 ;
     RECT  240.015 45.107 240.105 45.377 ;
     RECT  245.415 45.107 245.505 45.377 ;
     RECT  250.815 45.107 250.905 45.377 ;
     RECT  256.215 45.107 256.305 45.377 ;
     RECT  261.615 45.107 261.705 45.377 ;
     RECT  267.015 45.107 267.105 45.377 ;
     RECT  272.415 45.107 272.505 45.377 ;
     RECT  277.815 45.107 277.905 45.377 ;
     RECT  283.215 45.107 283.305 45.377 ;
     RECT  288.615 45.107 288.705 45.377 ;
     RECT  294.015 45.107 294.105 45.377 ;
     RECT  299.415 45.107 299.505 45.377 ;
     RECT  304.815 45.107 304.905 45.377 ;
     RECT  310.215 45.107 310.305 45.377 ;
     RECT  315.615 45.107 315.705 45.377 ;
     RECT  321.015 45.107 321.105 45.377 ;
     RECT  175.356 45.377 178.506 45.419 ;
     RECT  139.428 45.257 151.974 45.437 ;
     RECT  139.428 45.437 151.794 45.485 ;
     RECT  176.976 45.419 177.498 45.485 ;
     RECT  165.672 45.341 168.858 45.533 ;
     RECT  169.596 45.341 170.298 45.533 ;
     RECT  176.976 45.485 177.282 45.533 ;
     RECT  139.464 45.485 151.794 45.581 ;
     RECT  152.712 45.377 164.394 45.581 ;
     RECT  165.672 45.533 167.778 45.581 ;
     RECT  168.84 45.533 168.858 45.581 ;
     RECT  169.596 45.533 169.614 45.581 ;
     RECT  175.356 45.419 176.094 45.581 ;
     RECT  178.488 45.419 178.506 45.581 ;
     RECT  144.396 45.581 151.326 45.629 ;
     RECT  176.976 45.533 177.03 45.629 ;
     RECT  145.008 45.629 151.326 46.157 ;
     RECT  152.712 45.581 157.41 46.157 ;
     RECT  146.268 46.157 151.326 46.205 ;
     RECT  165.672 45.581 167.526 46.205 ;
     RECT  176.004 45.581 176.022 46.205 ;
     RECT  158.22 45.581 164.394 46.301 ;
     RECT  158.22 46.301 159.714 46.445 ;
     RECT  139.932 45.581 143.406 46.733 ;
     RECT  147.672 46.205 151.038 46.733 ;
     RECT  152.712 46.157 154.53 46.733 ;
     RECT  155.34 46.157 157.41 46.733 ;
     RECT  160.632 46.301 164.394 46.733 ;
     RECT  139.968 46.733 141.282 46.781 ;
     RECT  146.268 46.205 146.934 46.781 ;
     RECT  147.672 46.733 148.014 46.781 ;
     RECT  152.712 46.733 154.026 46.781 ;
     RECT  155.412 46.733 157.41 46.781 ;
     RECT  160.632 46.733 162.198 46.781 ;
     RECT  163.836 46.733 164.394 46.781 ;
     RECT  166.068 46.205 167.49 46.781 ;
     RECT  176.976 45.629 176.994 46.781 ;
     RECT  139.968 46.781 141.174 46.829 ;
     RECT  153.36 46.781 154.026 46.829 ;
     RECT  158.796 46.445 159.714 46.829 ;
     RECT  163.836 46.781 163.854 46.829 ;
     RECT  166.176 46.781 166.194 46.829 ;
     RECT  166.932 46.781 166.95 46.829 ;
     RECT  140.94 46.829 141.174 46.877 ;
     RECT  153.54 46.829 154.026 46.877 ;
     RECT  160.704 46.781 161.874 46.877 ;
     RECT  141.156 46.877 141.174 46.925 ;
     RECT  150.372 46.733 150.426 47.309 ;
     RECT  176.796 47.131 176.814 47.309 ;
     RECT  139.968 46.829 140.13 47.357 ;
     RECT  143.208 46.733 143.406 47.357 ;
     RECT  158.796 46.829 159.426 47.357 ;
     RECT  139.968 47.357 139.986 47.405 ;
     RECT  142.236 46.733 142.254 47.405 ;
     RECT  143.388 47.357 143.406 47.405 ;
     RECT  145.008 46.157 145.026 47.405 ;
     RECT  146.268 46.781 146.898 47.405 ;
     RECT  147.996 46.781 148.014 47.405 ;
     RECT  150.372 47.309 150.39 47.405 ;
     RECT  155.412 46.781 155.43 47.405 ;
     RECT  156.528 46.781 157.122 47.405 ;
     RECT  158.796 47.357 158.994 47.405 ;
     RECT  160.704 46.877 160.722 47.405 ;
     RECT  165.348 47.227 165.366 47.405 ;
     RECT  175.5 47.275 175.518 47.405 ;
     RECT  152.244 47.323 152.55 47.453 ;
     RECT  157.104 47.405 157.122 47.453 ;
     RECT  152.532 47.453 152.55 47.501 ;
     RECT  158.976 47.405 158.994 47.501 ;
    LAYER M4 ;
     RECT  0.06 23.568 0.533 25.512 ;
     RECT  0.533 23.568 2.408 25.464 ;
     RECT  2.408 2.148 2.512 45.372 ;
     RECT  2.512 2.418 2.704 45.102 ;
     RECT  2.704 23.568 7.808 25.464 ;
     RECT  7.808 2.148 7.912 45.372 ;
     RECT  7.912 2.418 8.104 45.102 ;
     RECT  8.104 23.568 13.208 25.464 ;
     RECT  13.208 2.148 13.312 45.372 ;
     RECT  13.312 2.418 13.504 45.102 ;
     RECT  13.504 23.568 18.608 25.464 ;
     RECT  18.608 2.148 18.712 45.372 ;
     RECT  18.712 2.418 18.904 45.102 ;
     RECT  18.904 23.568 24.008 25.464 ;
     RECT  24.008 2.148 24.112 45.372 ;
     RECT  24.112 2.418 24.304 45.102 ;
     RECT  24.304 23.568 29.408 25.464 ;
     RECT  29.408 2.148 29.512 45.372 ;
     RECT  29.512 2.418 29.704 45.102 ;
     RECT  29.704 23.568 34.808 25.464 ;
     RECT  34.808 2.148 34.912 45.372 ;
     RECT  34.912 2.418 35.104 45.102 ;
     RECT  35.104 23.568 40.208 25.464 ;
     RECT  40.208 2.148 40.312 45.372 ;
     RECT  40.312 2.418 40.504 45.102 ;
     RECT  40.504 23.568 45.608 25.464 ;
     RECT  45.608 2.148 45.712 45.372 ;
     RECT  45.712 2.418 45.904 45.102 ;
     RECT  45.904 23.568 51.008 25.464 ;
     RECT  51.008 2.148 51.112 45.372 ;
     RECT  51.112 2.418 51.304 45.102 ;
     RECT  51.304 23.568 56.408 25.464 ;
     RECT  56.408 2.148 56.512 45.372 ;
     RECT  56.512 2.418 56.704 45.102 ;
     RECT  56.704 23.568 61.808 25.464 ;
     RECT  61.808 2.148 61.912 45.372 ;
     RECT  61.912 2.418 62.104 45.102 ;
     RECT  62.104 23.568 67.208 25.464 ;
     RECT  67.208 2.148 67.312 45.372 ;
     RECT  67.312 2.418 67.504 45.102 ;
     RECT  67.504 23.568 72.608 25.464 ;
     RECT  72.608 2.148 72.712 45.372 ;
     RECT  72.712 2.418 72.904 45.102 ;
     RECT  72.904 23.568 76.997 25.464 ;
     RECT  76.997 23.568 78.008 25.272 ;
     RECT  78.008 2.148 78.112 45.372 ;
     RECT  78.112 2.418 78.304 45.102 ;
     RECT  78.304 23.568 79.373 25.272 ;
     RECT  79.373 23.664 83.408 25.272 ;
     RECT  83.408 2.148 83.512 45.372 ;
     RECT  83.512 2.418 83.704 45.102 ;
     RECT  83.704 23.664 88.808 25.272 ;
     RECT  88.808 2.148 88.912 45.372 ;
     RECT  88.912 2.418 89.104 45.102 ;
     RECT  89.104 23.664 94.208 25.272 ;
     RECT  94.208 2.148 94.312 45.372 ;
     RECT  94.312 2.418 94.504 45.102 ;
     RECT  94.504 23.664 99.608 25.272 ;
     RECT  99.608 2.148 99.712 45.372 ;
     RECT  99.712 2.418 99.904 45.102 ;
     RECT  99.904 23.664 105.008 25.272 ;
     RECT  105.008 2.148 105.112 45.372 ;
     RECT  105.112 2.418 105.304 45.102 ;
     RECT  105.304 23.664 110.408 25.272 ;
     RECT  110.408 2.148 110.512 45.372 ;
     RECT  110.512 2.418 110.704 45.102 ;
     RECT  110.704 23.664 115.808 25.272 ;
     RECT  115.808 2.148 115.912 45.372 ;
     RECT  115.912 2.418 116.104 45.102 ;
     RECT  116.104 23.664 121.208 25.272 ;
     RECT  121.208 2.148 121.312 45.372 ;
     RECT  121.312 2.418 121.504 45.102 ;
     RECT  121.504 23.664 126.608 25.272 ;
     RECT  126.608 2.148 126.712 45.372 ;
     RECT  126.712 2.418 126.904 45.102 ;
     RECT  126.904 23.664 132.008 25.272 ;
     RECT  132.008 2.148 132.112 45.372 ;
     RECT  132.112 2.418 132.304 45.102 ;
     RECT  135.109 1.728 135.205 1.752 ;
     RECT  135.205 1.728 135.241 1.8 ;
     RECT  135.397 3.408 135.493 3.432 ;
     RECT  135.493 3.408 135.589 4.008 ;
     RECT  135.241 1.728 135.781 2.328 ;
     RECT  135.589 3.408 135.781 4.056 ;
     RECT  135.781 1.728 136.789 4.056 ;
     RECT  136.177 12.432 137.257 12.456 ;
     RECT  136.789 1.728 137.408 4.152 ;
     RECT  136.789 5.136 137.408 5.16 ;
     RECT  136.609 7.44 137.408 7.464 ;
     RECT  136.892 10.512 137.408 10.536 ;
     RECT  137.257 12.432 137.408 12.552 ;
     RECT  136.753 17.472 137.408 17.496 ;
     RECT  132.304 23.664 137.408 25.272 ;
     RECT  137.413 0.384 137.509 0.408 ;
     RECT  137.408 1.728 137.512 45.372 ;
     RECT  137.509 0.384 137.653 0.504 ;
     RECT  137.512 1.728 137.704 45.102 ;
     RECT  137.653 0.192 137.842 0.504 ;
     RECT  137.842 0.096 137.891 0.504 ;
     RECT  137.891 0.096 137.939 0.36 ;
     RECT  137.704 6.24 137.939 7.464 ;
     RECT  137.939 6.24 137.945 6.552 ;
     RECT  137.704 16.512 138.233 17.496 ;
     RECT  137.704 18.576 138.773 18.936 ;
     RECT  137.704 1.728 138.985 4.584 ;
     RECT  137.704 29.04 139.237 29.064 ;
     RECT  137.704 14.256 139.313 14.28 ;
     RECT  139.237 28.368 139.349 29.064 ;
     RECT  138.985 1.728 139.381 4.68 ;
     RECT  139.409 45.552 139.417 45.576 ;
     RECT  138.773 18.576 139.421 18.792 ;
     RECT  139.417 45.456 139.484 45.576 ;
     RECT  139.484 45.024 139.571 45.576 ;
     RECT  139.237 26.784 139.705 26.808 ;
     RECT  139.349 29.04 139.705 29.064 ;
     RECT  138.233 17.04 139.78 17.064 ;
     RECT  139.78 17.04 139.781 17.112 ;
     RECT  137.704 12.528 139.813 12.552 ;
     RECT  139.705 29.04 139.813 29.736 ;
     RECT  139.453 30.816 139.813 30.84 ;
     RECT  139.717 47.376 139.813 47.4 ;
     RECT  137.704 20.16 139.817 20.184 ;
     RECT  137.704 23.664 139.849 25.272 ;
     RECT  139.813 11.856 139.859 12.552 ;
     RECT  139.813 29.04 139.859 30.84 ;
     RECT  139.859 29.04 139.889 30.792 ;
     RECT  139.859 11.856 139.9 11.88 ;
     RECT  139.421 18.576 139.921 18.6 ;
     RECT  139.813 47.328 139.921 47.4 ;
     RECT  139.921 18.48 139.957 18.6 ;
     RECT  139.921 46.704 139.997 47.4 ;
     RECT  139.381 1.728 140.005 4.776 ;
     RECT  139.571 45.312 140.065 45.576 ;
     RECT  139.993 42.144 140.093 42.168 ;
     RECT  139.021 33.408 140.137 33.432 ;
     RECT  140.065 45.312 140.137 45.672 ;
     RECT  139.997 46.704 140.137 47.352 ;
     RECT  140.005 1.728 140.141 5.112 ;
     RECT  140.137 45.312 140.141 47.352 ;
     RECT  139.849 35.616 140.165 35.64 ;
     RECT  139.309 37.344 140.165 37.368 ;
     RECT  140.137 33.12 140.177 33.432 ;
     RECT  140.093 41.616 140.177 42.168 ;
     RECT  140.165 35.616 140.243 37.368 ;
     RECT  137.704 22.176 140.249 22.2 ;
     RECT  140.243 36.48 140.249 37.368 ;
     RECT  139.849 23.376 140.317 25.272 ;
     RECT  140.177 33.12 140.317 33.144 ;
     RECT  139.909 44.208 140.353 44.232 ;
     RECT  139.705 26.784 140.389 27.048 ;
     RECT  140.317 22.8 140.429 25.272 ;
     RECT  140.389 26.784 140.429 27.336 ;
     RECT  140.353 44.016 140.465 44.232 ;
     RECT  139.957 18.144 140.531 18.6 ;
     RECT  139.849 39.6 140.533 39.624 ;
     RECT  140.005 40.608 140.533 40.632 ;
     RECT  140.141 1.728 140.573 4.728 ;
     RECT  140.249 37.056 140.573 37.368 ;
     RECT  140.573 1.728 140.749 4.152 ;
     RECT  140.713 0.096 140.819 0.12 ;
     RECT  140.465 44.208 140.825 44.232 ;
     RECT  139.889 29.664 140.893 30.792 ;
     RECT  140.317 33.072 140.893 33.144 ;
     RECT  140.749 1.104 140.915 4.152 ;
     RECT  140.893 33.024 140.933 33.144 ;
     RECT  140.893 29.664 140.977 31.368 ;
     RECT  140.977 29.664 140.997 30.6 ;
     RECT  140.533 39.6 141.013 40.632 ;
     RECT  140.531 18.576 141.109 18.6 ;
     RECT  140.933 33.024 141.109 33.048 ;
     RECT  141.013 39.36 141.113 40.632 ;
     RECT  140.141 45.312 141.145 46.872 ;
     RECT  140.177 42.096 141.185 42.168 ;
     RECT  141.109 32.496 141.193 33.048 ;
     RECT  141.116 38.64 141.203 38.664 ;
     RECT  140.573 37.344 141.281 37.368 ;
     RECT  141.281 37.344 141.365 38.232 ;
     RECT  141.145 45.312 141.541 46.92 ;
     RECT  141.541 45.024 141.683 46.92 ;
     RECT  141.109 18.576 141.829 19.368 ;
     RECT  141.721 42.72 141.893 42.744 ;
     RECT  137.945 6.528 141.973 6.552 ;
     RECT  141.683 45.456 142.117 46.92 ;
     RECT  140.915 1.728 142.261 4.152 ;
     RECT  142.117 45.456 142.265 47.4 ;
     RECT  141.113 39.888 142.297 40.632 ;
     RECT  142.261 1.728 142.357 4.68 ;
     RECT  141.973 6.528 142.357 6.84 ;
     RECT  139.813 10.848 142.369 10.872 ;
     RECT  140.209 21.168 142.369 21.192 ;
     RECT  142.369 21.168 142.453 21.672 ;
     RECT  141.829 18.576 142.513 19.56 ;
     RECT  142.357 1.728 142.517 6.84 ;
     RECT  140.997 29.664 142.549 29.688 ;
     RECT  142.265 45.456 142.625 47.352 ;
     RECT  140.429 27.312 142.693 27.336 ;
     RECT  142.517 1.776 142.808 6.84 ;
     RECT  142.453 9.792 142.808 9.816 ;
     RECT  142.369 10.848 142.808 11.208 ;
     RECT  139.741 14.688 142.808 14.712 ;
     RECT  139.781 17.088 142.808 17.112 ;
     RECT  142.513 18.24 142.808 19.56 ;
     RECT  142.453 21.12 142.808 21.672 ;
     RECT  140.429 23.664 142.808 25.272 ;
     RECT  142.693 26.784 142.808 27.336 ;
     RECT  142.549 29.04 142.808 29.784 ;
     RECT  141.193 33.024 142.808 33.048 ;
     RECT  142.549 35.28 142.808 35.304 ;
     RECT  141.365 37.344 142.808 37.368 ;
     RECT  142.297 39.84 142.808 40.632 ;
     RECT  142.045 41.664 142.808 41.688 ;
     RECT  141.893 42.72 142.808 43.368 ;
     RECT  142.625 45.456 142.808 46.2 ;
     RECT  142.808 1.776 142.931 46.2 ;
     RECT  142.931 1.776 142.985 46.152 ;
     RECT  142.645 0.144 143.077 0.168 ;
     RECT  142.985 1.776 143.104 45.576 ;
     RECT  143.077 0.144 143.218 0.312 ;
     RECT  143.104 22.224 143.219 26.808 ;
     RECT  142.625 47.232 143.219 47.352 ;
     RECT  143.219 47.328 143.237 47.352 ;
     RECT  143.104 1.776 143.26 8.664 ;
     RECT  143.219 23.04 143.309 26.808 ;
     RECT  143.104 13.44 143.315 16.536 ;
     RECT  143.104 9.648 143.411 12.408 ;
     RECT  143.218 0.096 143.413 0.312 ;
     RECT  143.333 47.376 143.417 47.4 ;
     RECT  143.411 9.648 143.425 10.872 ;
     RECT  143.104 29.04 143.453 29.784 ;
     RECT  143.315 13.44 143.459 16.152 ;
     RECT  143.413 0.096 143.597 0.36 ;
     RECT  143.597 0.096 143.603 0.216 ;
     RECT  143.26 1.776 143.633 7.992 ;
     RECT  143.104 44.448 143.633 45.576 ;
     RECT  143.603 0.096 143.641 0.12 ;
     RECT  143.633 1.776 143.653 7.464 ;
     RECT  143.459 13.44 143.699 14.664 ;
     RECT  143.653 1.728 143.741 7.464 ;
     RECT  143.699 14.208 143.777 14.664 ;
     RECT  143.425 10.848 143.921 10.872 ;
     RECT  143.104 39.84 143.921 41.688 ;
     RECT  143.104 37.344 144.097 37.368 ;
     RECT  143.425 9.648 144.133 9.672 ;
     RECT  143.633 45.024 144.179 45.576 ;
     RECT  143.741 6.24 144.227 7.464 ;
     RECT  143.921 40.416 144.229 41.688 ;
     RECT  144.097 43.296 144.229 43.32 ;
     RECT  143.741 1.728 144.245 5.112 ;
     RECT  143.411 12 144.245 12.408 ;
     RECT  144.179 45.312 144.38 45.576 ;
     RECT  144.133 9.408 144.389 9.672 ;
     RECT  144.245 2.832 144.425 5.112 ;
     RECT  143.459 16.128 144.524 16.152 ;
     RECT  144.524 15.84 144.565 16.152 ;
     RECT  144.565 15.84 144.611 16.68 ;
     RECT  144.313 38.352 144.661 38.376 ;
     RECT  144.245 1.728 144.677 1.848 ;
     RECT  144.227 6.24 144.677 6.84 ;
     RECT  144.661 38.352 144.748 39.336 ;
     RECT  144.097 36.72 144.749 37.368 ;
     RECT  144.245 12.192 144.773 12.408 ;
     RECT  144.773 12.192 144.857 13.08 ;
     RECT  144.38 45.312 144.901 45.624 ;
     RECT  144.229 40.416 145.177 43.32 ;
     RECT  144.901 45.312 145.189 46.152 ;
     RECT  144.748 38.352 145.325 38.808 ;
     RECT  144.611 16.656 145.333 16.68 ;
     RECT  145.249 27.936 145.333 27.96 ;
     RECT  145.333 16.656 145.379 17.64 ;
     RECT  145.325 38.352 145.397 38.376 ;
     RECT  144.425 2.88 145.525 5.112 ;
     RECT  143.309 23.04 145.525 26.232 ;
     RECT  145.525 23.04 145.573 26.424 ;
     RECT  145.189 45.264 145.609 46.152 ;
     RECT  143.453 29.04 145.669 29.064 ;
     RECT  144.677 1.728 145.765 1.8 ;
     RECT  145.525 2.832 145.765 5.112 ;
     RECT  144.677 6.24 145.765 6.312 ;
     RECT  145.285 7.968 145.789 7.992 ;
     RECT  145.669 29.04 145.813 29.352 ;
     RECT  145.789 7.872 145.825 7.992 ;
     RECT  145.765 1.728 145.861 5.112 ;
     RECT  145.765 6.24 145.861 6.792 ;
     RECT  144.389 9.648 145.865 9.672 ;
     RECT  145.813 29.04 145.868 30.264 ;
     RECT  145.868 29.04 145.909 31.032 ;
     RECT  143.104 33.024 145.909 33.048 ;
     RECT  143.104 19.536 145.925 19.56 ;
     RECT  143.104 35.28 145.957 35.304 ;
     RECT  144.749 36.72 145.957 36.744 ;
     RECT  145.925 18.816 146.041 19.56 ;
     RECT  145.957 35.28 146.041 36.744 ;
     RECT  146.041 35.28 146.053 37.08 ;
     RECT  146.041 18.816 146.081 19.848 ;
     RECT  146.053 34.752 146.081 37.08 ;
     RECT  145.909 29.04 146.099 33.144 ;
     RECT  146.081 34.752 146.099 35.304 ;
     RECT  146.099 31.776 146.117 32.376 ;
     RECT  145.177 40.416 146.149 43.8 ;
     RECT  146.081 19.824 146.252 19.848 ;
     RECT  143.104 21.12 146.252 21.144 ;
     RECT  146.252 19.824 146.293 21.144 ;
     RECT  146.099 29.04 146.329 29.784 ;
     RECT  146.149 40.416 146.329 43.848 ;
     RECT  146.293 19.824 146.339 21.432 ;
     RECT  146.099 34.752 146.441 34.776 ;
     RECT  145.573 23.04 146.483 27.336 ;
     RECT  145.861 1.728 146.509 6.792 ;
     RECT  145.825 7.872 146.509 8.52 ;
     RECT  146.329 40.32 146.509 43.848 ;
     RECT  145.609 45.024 146.509 46.152 ;
     RECT  146.509 1.728 146.513 8.52 ;
     RECT  146.509 40.32 146.533 46.152 ;
     RECT  144.805 47.376 146.533 47.4 ;
     RECT  146.329 28.704 146.549 29.784 ;
     RECT  146.483 23.04 146.761 26.76 ;
     RECT  146.081 18.816 146.801 18.84 ;
     RECT  146.533 40.32 146.909 47.4 ;
     RECT  146.117 31.872 147.025 32.376 ;
     RECT  146.909 40.32 147.053 46.776 ;
     RECT  146.513 1.728 147.125 7.992 ;
     RECT  146.761 22.8 147.125 26.76 ;
     RECT  147.125 1.728 147.197 5.208 ;
     RECT  146.725 39.216 147.337 39.24 ;
     RECT  146.081 36.72 147.397 37.08 ;
     RECT  143.777 14.208 147.637 14.232 ;
     RECT  147.337 38.736 147.733 39.24 ;
     RECT  147.053 40.32 147.733 45.048 ;
     RECT  147.637 13.68 147.74 14.232 ;
     RECT  147.053 46.128 147.985 46.776 ;
     RECT  147.733 38.736 148.093 45.048 ;
     RECT  147.985 46.128 148.093 47.4 ;
     RECT  147.197 1.728 148.208 5.16 ;
     RECT  147.125 6.24 148.208 7.992 ;
     RECT  148.069 9.264 148.208 9.288 ;
     RECT  146.257 10.896 148.208 10.92 ;
     RECT  144.857 12.192 148.208 12.216 ;
     RECT  147.74 13.44 148.208 14.232 ;
     RECT  145.379 17.616 148.208 17.64 ;
     RECT  146.339 19.824 148.208 19.848 ;
     RECT  146.339 21.12 148.208 21.432 ;
     RECT  147.125 23.664 148.208 26.76 ;
     RECT  146.549 28.704 148.208 29.352 ;
     RECT  147.025 32.208 148.208 32.376 ;
     RECT  147.397 36.48 148.208 37.08 ;
     RECT  148.093 38.736 148.208 47.4 ;
     RECT  148.208 1.728 148.307 47.4 ;
     RECT  148.307 1.728 148.504 46.728 ;
     RECT  148.504 10.848 148.643 11.16 ;
     RECT  148.504 40.416 148.709 41.688 ;
     RECT  148.021 0.144 148.739 0.168 ;
     RECT  148.709 40.848 148.817 41.688 ;
     RECT  148.504 7.44 148.876 8.04 ;
     RECT  148.504 36.576 148.889 37.896 ;
     RECT  148.876 7.44 149.123 7.992 ;
     RECT  148.504 9.072 149.123 9.864 ;
     RECT  149.123 7.44 149.141 7.656 ;
     RECT  149.123 9.072 149.141 9.096 ;
     RECT  148.643 10.848 149.429 10.92 ;
     RECT  148.504 12.528 149.429 12.552 ;
     RECT  148.504 19.392 149.509 19.848 ;
     RECT  148.504 21.072 149.509 21.192 ;
     RECT  149.509 19.392 149.596 21.192 ;
     RECT  148.504 1.728 149.641 6.12 ;
     RECT  148.504 32.208 149.641 32.232 ;
     RECT  149.653 35.328 149.74 35.352 ;
     RECT  149.533 16.08 149.785 16.104 ;
     RECT  148.504 17.616 149.785 17.64 ;
     RECT  148.817 41.664 149.789 41.688 ;
     RECT  148.504 42.72 149.797 46.728 ;
     RECT  148.504 28.416 149.821 29.352 ;
     RECT  149.596 21.072 149.845 21.192 ;
     RECT  149.605 10.272 149.933 10.296 ;
     RECT  149.596 19.392 149.941 19.512 ;
     RECT  148.504 39.36 150.145 39.384 ;
     RECT  149.785 16.08 150.181 17.64 ;
     RECT  149.941 18.816 150.181 19.512 ;
     RECT  149.797 41.76 150.181 46.728 ;
     RECT  148.504 23.664 150.253 26.424 ;
     RECT  150.181 41.76 150.329 47.4 ;
     RECT  150.145 39.36 150.332 40.008 ;
     RECT  150.329 43.968 150.401 47.4 ;
     RECT  150.332 39.216 150.419 40.008 ;
     RECT  150.253 23.328 150.421 26.424 ;
     RECT  150.401 43.968 150.437 47.304 ;
     RECT  150.421 23.328 150.469 27.336 ;
     RECT  149.821 28.416 150.473 29.496 ;
     RECT  149.641 1.728 150.581 6.312 ;
     RECT  150.469 22.992 150.721 27.336 ;
     RECT  149.641 31.344 150.721 32.232 ;
     RECT  150.721 30.72 150.761 32.232 ;
     RECT  150.721 22.992 150.833 27.96 ;
     RECT  149.785 11.376 150.865 11.4 ;
     RECT  148.504 33.792 150.865 33.816 ;
     RECT  150.865 10.8 150.869 11.4 ;
     RECT  150.181 16.08 150.869 19.512 ;
     RECT  148.889 36.576 150.869 36.648 ;
     RECT  148.504 14.208 150.901 14.232 ;
     RECT  150.901 13.824 150.905 14.232 ;
     RECT  150.869 16.08 150.905 17.352 ;
     RECT  150.865 33.792 150.905 34.2 ;
     RECT  150.437 43.968 150.905 46.728 ;
     RECT  150.473 29.232 150.977 29.496 ;
     RECT  150.329 41.76 150.997 42.696 ;
     RECT  150.997 41.712 151.043 42.696 ;
     RECT  150.833 22.992 151.045 26.424 ;
     RECT  150.905 44.448 151.049 46.728 ;
     RECT  149.141 7.44 151.237 7.464 ;
     RECT  151.049 44.448 151.265 46.2 ;
     RECT  150.833 27.936 151.331 27.96 ;
     RECT  151.045 22.896 151.337 26.424 ;
     RECT  151.265 45.024 151.337 46.2 ;
     RECT  150.905 17.328 151.373 17.352 ;
     RECT  150.869 18.816 151.373 19.512 ;
     RECT  149.845 21.072 151.477 21.528 ;
     RECT  150.581 1.728 151.621 5.976 ;
     RECT  151.621 1.152 151.657 5.976 ;
     RECT  151.237 7.056 151.657 7.464 ;
     RECT  151.373 19.488 151.661 19.512 ;
     RECT  151.657 1.152 151.697 7.464 ;
     RECT  151.697 1.152 151.705 7.416 ;
     RECT  151.477 20.544 151.724 21.528 ;
     RECT  151.724 20.544 151.811 21.672 ;
     RECT  151.705 1.728 152.093 7.416 ;
     RECT  151.811 20.544 152.197 21.528 ;
     RECT  150.761 30.72 152.233 30.744 ;
     RECT  151.621 43.248 152.233 43.272 ;
     RECT  152.189 47.328 152.233 47.352 ;
     RECT  152.093 1.728 152.237 5.448 ;
     RECT  152.197 19.968 152.237 21.528 ;
     RECT  152.233 30.624 152.345 30.744 ;
     RECT  152.237 1.728 152.387 2.232 ;
     RECT  151.337 45.024 152.389 45.576 ;
     RECT  150.869 10.8 152.413 10.824 ;
     RECT  152.093 7.344 152.417 7.416 ;
     RECT  152.413 10.32 152.453 10.824 ;
     RECT  152.233 47.328 152.521 47.448 ;
     RECT  152.233 43.248 152.525 43.608 ;
     RECT  152.237 3.216 152.561 5.448 ;
     RECT  150.905 16.08 152.593 16.104 ;
     RECT  152.525 43.584 152.629 43.608 ;
     RECT  152.389 44.976 152.629 45.576 ;
     RECT  152.593 15.984 152.633 16.104 ;
     RECT  150.905 34.176 152.693 34.2 ;
     RECT  152.521 47.328 152.701 47.496 ;
     RECT  152.237 19.968 152.737 19.992 ;
     RECT  150.869 36.576 152.917 36.6 ;
     RECT  148.889 37.872 152.917 37.896 ;
     RECT  152.629 43.584 153.025 45.576 ;
     RECT  152.701 46.752 153.025 47.496 ;
     RECT  150.977 29.232 153.205 29.352 ;
     RECT  151.337 22.992 153.277 26.424 ;
     RECT  152.387 1.728 153.493 1.848 ;
     RECT  152.345 30.72 153.493 30.744 ;
     RECT  150.761 32.208 153.493 32.232 ;
     RECT  150.905 13.824 153.601 13.848 ;
     RECT  153.493 1.728 153.608 2.28 ;
     RECT  152.561 3.312 153.608 4.248 ;
     RECT  152.561 5.424 153.608 5.448 ;
     RECT  152.417 7.344 153.608 7.368 ;
     RECT  151.297 8.736 153.608 8.76 ;
     RECT  152.453 10.32 153.608 10.344 ;
     RECT  150.829 12.768 153.608 12.792 ;
     RECT  153.601 13.824 153.608 14.76 ;
     RECT  152.633 15.984 153.608 16.008 ;
     RECT  153.493 18.24 153.608 18.264 ;
     RECT  152.737 19.392 153.608 19.992 ;
     RECT  152.237 21.504 153.608 21.528 ;
     RECT  153.277 22.752 153.608 26.424 ;
     RECT  153.493 27.888 153.608 27.912 ;
     RECT  153.205 29.232 153.608 29.64 ;
     RECT  153.493 30.624 153.608 32.232 ;
     RECT  152.693 34.176 153.608 34.824 ;
     RECT  152.917 36.576 153.608 37.896 ;
     RECT  153.241 40.368 153.608 40.392 ;
     RECT  151.043 41.712 153.608 41.736 ;
     RECT  153.025 43.584 153.608 47.496 ;
     RECT  153.608 1.728 153.904 47.496 ;
     RECT  153.904 43.584 153.965 47.496 ;
     RECT  153.904 22.752 154.001 26.136 ;
     RECT  153.904 29.328 154.001 29.352 ;
     RECT  153.904 13.824 154.451 16.008 ;
     RECT  154.451 13.824 154.469 15.144 ;
     RECT  153.904 18.24 154.505 18.456 ;
     RECT  153.904 34.176 154.505 34.824 ;
     RECT  153.965 43.728 154.577 43.752 ;
     RECT  153.904 6.864 154.793 6.888 ;
     RECT  153.904 8.736 154.793 8.76 ;
     RECT  153.904 36.576 154.793 38.808 ;
     RECT  153.904 1.728 154.883 4.008 ;
     RECT  153.904 5.04 154.937 5.064 ;
     RECT  154.001 22.8 154.973 26.136 ;
     RECT  154.793 36.576 155.029 38.184 ;
     RECT  155.029 36.192 155.075 38.184 ;
     RECT  155.075 36.192 155.153 37.128 ;
     RECT  153.904 27.888 155.185 27.912 ;
     RECT  155.077 8.352 155.225 8.568 ;
     RECT  155.185 27.792 155.225 27.912 ;
     RECT  153.904 20.688 155.401 21.672 ;
     RECT  154.973 22.8 155.401 25.464 ;
     RECT  153.904 10.32 155.461 10.344 ;
     RECT  153.904 11.712 155.461 11.736 ;
     RECT  155.437 6.24 155.521 6.264 ;
     RECT  154.469 13.824 155.545 14.76 ;
     RECT  154.885 33.6 155.549 33.624 ;
     RECT  154.505 34.8 155.557 34.824 ;
     RECT  155.557 33.984 155.603 34.824 ;
     RECT  154.883 1.728 155.612 3.864 ;
     RECT  155.225 8.544 155.657 8.568 ;
     RECT  155.545 13.008 155.657 14.76 ;
     RECT  155.401 20.688 155.801 25.464 ;
     RECT  155.612 1.68 156.013 3.864 ;
     RECT  153.965 44.784 156.017 47.496 ;
     RECT  153.904 41.616 156.049 41.64 ;
     RECT  156.013 1.68 156.085 4.008 ;
     RECT  155.461 10.32 156.089 11.736 ;
     RECT  153.904 30.624 156.157 30.648 ;
     RECT  156.085 1.68 156.169 4.104 ;
     RECT  156.169 1.68 156.179 4.008 ;
     RECT  156.049 41.616 156.227 42.312 ;
     RECT  153.904 32.208 156.229 32.232 ;
     RECT  155.801 21.072 156.269 25.464 ;
     RECT  156.229 32.208 156.275 32.712 ;
     RECT  155.075 38.16 156.277 38.184 ;
     RECT  156.017 44.784 156.301 45.576 ;
     RECT  156.157 16.56 156.305 16.584 ;
     RECT  156.277 38.16 156.323 38.808 ;
     RECT  156.301 43.92 156.373 45.576 ;
     RECT  155.225 27.792 156.409 27.816 ;
     RECT  155.153 36.192 156.445 36.6 ;
     RECT  156.157 30.624 156.449 30.888 ;
     RECT  156.449 30.816 156.469 30.888 ;
     RECT  156.227 42.144 156.521 42.168 ;
     RECT  156.445 35.904 156.529 36.6 ;
     RECT  156.089 10.32 156.545 11.16 ;
     RECT  156.179 1.68 156.625 3.96 ;
     RECT  156.545 10.224 156.629 11.16 ;
     RECT  155.657 13.008 156.665 13.848 ;
     RECT  156.661 6.24 156.745 6.264 ;
     RECT  156.469 30.816 156.755 31.32 ;
     RECT  154.505 18.432 156.841 18.456 ;
     RECT  156.121 5.088 156.877 5.112 ;
     RECT  156.269 21.648 156.881 25.464 ;
     RECT  156.841 18.432 156.913 19.416 ;
     RECT  156.409 27.264 156.917 27.816 ;
     RECT  156.86 6.816 156.947 6.84 ;
     RECT  156.86 16.176 156.947 16.536 ;
     RECT  156.017 46.752 156.997 47.496 ;
     RECT  156.913 18.432 157.025 20.232 ;
     RECT  156.997 46.704 157.169 47.496 ;
     RECT  156.625 1.104 157.228 3.96 ;
     RECT  157.228 1.104 157.237 2.28 ;
     RECT  156.323 38.784 157.244 38.808 ;
     RECT  153.904 40.368 157.244 40.392 ;
     RECT  156.947 16.512 157.309 16.536 ;
     RECT  157.237 0.528 157.331 2.28 ;
     RECT  157.244 38.784 157.331 40.392 ;
     RECT  157.228 3.408 157.417 3.96 ;
     RECT  156.877 5.088 157.417 5.736 ;
     RECT  157.309 16.512 157.475 16.584 ;
     RECT  156.755 30.816 157.529 30.888 ;
     RECT  157.331 38.784 157.573 38.808 ;
     RECT  155.603 33.984 157.601 34.008 ;
     RECT  157.331 40.368 157.633 40.392 ;
     RECT  156.529 36.096 157.669 36.6 ;
     RECT  156.881 23.088 157.673 25.464 ;
     RECT  157.345 42.288 157.724 42.312 ;
     RECT  156.373 43.584 157.724 45.576 ;
     RECT  157.633 40.368 157.733 40.728 ;
     RECT  157.724 42.288 157.811 45.576 ;
     RECT  157.331 0.528 157.849 1.8 ;
     RECT  157.733 40.368 157.861 41.304 ;
     RECT  157.811 42.288 157.861 42.792 ;
     RECT  157.669 36.096 157.889 36.888 ;
     RECT  157.573 38.208 157.921 38.808 ;
     RECT  156.881 21.648 157.925 22.008 ;
     RECT  156.917 27.264 157.993 27.288 ;
     RECT  157.529 30.816 158.065 30.84 ;
     RECT  157.849 0.096 158.099 1.8 ;
     RECT  157.417 3.408 158.101 5.736 ;
     RECT  158.099 0.096 158.195 0.6 ;
     RECT  157.811 43.92 158.209 45.576 ;
     RECT  157.169 46.752 158.209 47.496 ;
     RECT  158.065 30.768 158.245 30.84 ;
     RECT  158.101 3.408 158.281 6.024 ;
     RECT  157.861 40.368 158.341 42.792 ;
     RECT  157.475 16.512 158.425 16.536 ;
     RECT  158.281 2.832 158.437 6.024 ;
     RECT  158.101 7.584 158.437 7.608 ;
     RECT  158.099 1.728 158.533 1.8 ;
     RECT  158.533 1.728 158.713 1.848 ;
     RECT  158.437 2.832 158.713 7.608 ;
     RECT  157.993 27.024 158.785 27.288 ;
     RECT  158.785 26.928 158.849 27.288 ;
     RECT  158.785 29.04 158.849 29.064 ;
     RECT  158.195 0.096 158.963 0.36 ;
     RECT  158.245 30.336 158.965 30.84 ;
     RECT  156.275 32.688 158.965 32.712 ;
     RECT  158.209 43.92 159.005 47.496 ;
     RECT  158.713 1.728 159.008 7.608 ;
     RECT  156.629 10.848 159.008 11.16 ;
     RECT  156.665 13.824 159.008 13.848 ;
     RECT  158.425 16.272 159.008 16.536 ;
     RECT  158.425 17.664 159.008 17.688 ;
     RECT  157.025 19.392 159.008 20.232 ;
     RECT  157.925 21.936 159.008 22.008 ;
     RECT  157.673 23.088 159.008 24.12 ;
     RECT  157.673 25.248 159.008 25.464 ;
     RECT  158.849 26.928 159.008 29.064 ;
     RECT  158.965 30.336 159.008 32.712 ;
     RECT  158.497 34.8 159.008 34.824 ;
     RECT  157.889 36.096 159.008 36.6 ;
     RECT  157.921 38.112 159.008 38.808 ;
     RECT  158.341 39.888 159.008 42.792 ;
     RECT  159.005 43.92 159.008 47.352 ;
     RECT  158.963 0.144 159.205 0.36 ;
     RECT  159.008 1.728 159.304 47.352 ;
     RECT  159.304 29.04 159.437 30.792 ;
     RECT  159.304 36.336 159.437 37.08 ;
     RECT  159.205 0.144 159.443 0.456 ;
     RECT  159.304 1.728 159.443 6.408 ;
     RECT  159.304 42.432 159.443 47.352 ;
     RECT  159.443 0.144 159.491 0.36 ;
     RECT  159.443 1.728 159.491 4.152 ;
     RECT  159.304 21.936 159.581 24.12 ;
     RECT  159.491 0.144 159.587 0.168 ;
     RECT  159.443 42.432 159.587 47.304 ;
     RECT  159.304 16.272 159.653 16.44 ;
     RECT  159.587 42.432 159.827 46.824 ;
     RECT  159.491 1.728 159.877 4.008 ;
     RECT  159.304 31.776 159.905 31.8 ;
     RECT  159.437 29.04 159.923 30.6 ;
     RECT  159.304 9.696 159.941 9.72 ;
     RECT  159.443 5.712 160.013 6.408 ;
     RECT  159.304 39.888 160.019 40.344 ;
     RECT  159.827 42.432 160.019 42.456 ;
     RECT  159.437 36.576 160.265 37.08 ;
     RECT  160.165 0.096 160.301 0.12 ;
     RECT  159.923 29.04 160.301 29.688 ;
     RECT  160.013 6.384 160.333 6.408 ;
     RECT  159.304 27.36 160.337 27.432 ;
     RECT  159.877 1.728 160.445 3.96 ;
     RECT  160.337 27.408 160.481 27.432 ;
     RECT  160.333 6.384 160.595 6.888 ;
     RECT  160.445 3.936 160.633 3.96 ;
     RECT  159.827 43.584 160.645 46.824 ;
     RECT  160.645 43.584 160.733 47.4 ;
     RECT  159.304 10.848 160.769 11.448 ;
     RECT  159.581 21.936 160.801 23.928 ;
     RECT  160.445 1.728 160.877 2.856 ;
     RECT  160.441 34.752 161.045 34.776 ;
     RECT  161.045 34.752 161.077 35.352 ;
     RECT  161.077 34.608 161.129 35.352 ;
     RECT  159.304 19.584 161.269 19.608 ;
     RECT  161.269 3.984 161.305 4.008 ;
     RECT  161.269 19.488 161.315 19.608 ;
     RECT  160.595 6.384 161.377 6.408 ;
     RECT  161.377 6.24 161.417 6.408 ;
     RECT  161.305 3.984 161.521 4.584 ;
     RECT  161.521 3.984 161.693 4.632 ;
     RECT  160.733 43.584 161.701 46.872 ;
     RECT  161.693 3.984 161.845 4.728 ;
     RECT  161.605 9.696 161.849 9.72 ;
     RECT  161.701 42.768 161.885 46.872 ;
     RECT  160.877 1.728 162.025 2.712 ;
     RECT  161.845 3.984 162.025 5.208 ;
     RECT  160.769 10.848 162.025 10.968 ;
     RECT  160.801 21.12 162.101 23.928 ;
     RECT  162.025 10.224 162.133 10.968 ;
     RECT  162.025 1.728 162.209 5.208 ;
     RECT  161.417 6.24 162.245 6.264 ;
     RECT  162.241 0.096 162.277 0.12 ;
     RECT  162.209 1.728 162.353 2.904 ;
     RECT  162.209 4.08 162.353 5.208 ;
     RECT  161.885 43.584 162.419 46.872 ;
     RECT  160.265 37.056 162.421 37.08 ;
     RECT  161.129 34.608 162.457 34.632 ;
     RECT  162.421 37.056 162.461 37.608 ;
     RECT  162.133 10.224 162.467 11.688 ;
     RECT  162.457 34.608 162.497 34.728 ;
     RECT  162.277 0.096 162.515 0.6 ;
     RECT  162.353 4.08 162.533 4.584 ;
     RECT  162.419 43.584 162.605 46.728 ;
     RECT  162.515 0.096 162.611 0.12 ;
     RECT  161.315 19.488 162.673 19.512 ;
     RECT  160.301 29.664 162.673 29.688 ;
     RECT  159.653 16.416 162.701 16.44 ;
     RECT  162.701 16.416 162.709 17.112 ;
     RECT  162.467 10.752 162.713 10.92 ;
     RECT  162.673 19.488 162.713 19.944 ;
     RECT  162.673 29.664 162.713 29.784 ;
     RECT  162.709 15.84 162.755 17.112 ;
     RECT  162.755 17.088 162.785 17.112 ;
     RECT  160.297 8.448 162.817 8.472 ;
     RECT  162.713 10.8 162.893 10.92 ;
     RECT  159.304 41.376 162.925 41.4 ;
     RECT  162.101 21.936 162.929 23.928 ;
     RECT  162.605 43.632 162.965 46.728 ;
     RECT  159.304 25.152 163.001 25.656 ;
     RECT  162.893 10.8 163.145 10.872 ;
     RECT  162.781 12.912 163.213 12.936 ;
     RECT  162.929 23.04 163.213 23.928 ;
     RECT  163.001 25.152 163.213 25.176 ;
     RECT  160.693 31.296 163.289 31.32 ;
     RECT  162.353 1.728 163.361 2.52 ;
     RECT  162.169 7.44 163.493 7.464 ;
     RECT  162.817 8.448 163.493 8.568 ;
     RECT  163.493 14.832 163.525 14.856 ;
     RECT  163.493 7.44 163.621 8.568 ;
     RECT  162.929 21.936 163.621 22.056 ;
     RECT  163.813 5.136 163.82 5.16 ;
     RECT  162.965 45.552 163.825 46.728 ;
     RECT  163.82 5.136 163.861 5.736 ;
     RECT  163.621 6.864 163.861 8.568 ;
     RECT  162.713 29.76 163.861 29.784 ;
     RECT  164.005 28.416 164.041 28.44 ;
     RECT  162.533 4.08 164.077 4.104 ;
     RECT  163.861 5.136 164.077 8.568 ;
     RECT  164.041 28.416 164.113 28.536 ;
     RECT  163.213 12.912 164.149 13.656 ;
     RECT  162.965 43.632 164.185 44.472 ;
     RECT  163.361 1.728 164.269 2.328 ;
     RECT  164.005 0.096 164.285 0.12 ;
     RECT  163.145 10.848 164.293 10.872 ;
     RECT  163.537 32.16 164.365 32.184 ;
     RECT  164.285 0.096 164.368 0.168 ;
     RECT  164.269 1.968 164.408 2.328 ;
     RECT  164.077 4.08 164.408 8.568 ;
     RECT  164.293 10.848 164.408 10.968 ;
     RECT  164.149 11.952 164.408 13.656 ;
     RECT  163.525 14.64 164.408 14.856 ;
     RECT  162.755 15.84 164.408 15.864 ;
     RECT  163.933 18.432 164.408 18.456 ;
     RECT  162.713 19.92 164.408 19.944 ;
     RECT  163.621 21.648 164.408 22.056 ;
     RECT  163.213 23.04 164.408 25.176 ;
     RECT  163.573 26.544 164.408 26.568 ;
     RECT  164.113 28.224 164.408 28.536 ;
     RECT  163.861 29.568 164.408 29.784 ;
     RECT  164.005 31.152 164.408 31.176 ;
     RECT  164.365 32.16 164.408 32.328 ;
     RECT  162.497 34.704 164.408 34.728 ;
     RECT  164.293 36.432 164.408 36.456 ;
     RECT  162.461 37.584 164.408 37.608 ;
     RECT  162.925 41.376 164.408 42.168 ;
     RECT  164.185 43.296 164.408 44.472 ;
     RECT  163.825 45.552 164.408 46.824 ;
     RECT  164.408 1.968 164.531 46.824 ;
     RECT  164.531 46.752 164.627 46.824 ;
     RECT  164.531 1.968 164.704 45.336 ;
     RECT  164.627 46.8 164.723 46.824 ;
     RECT  164.704 37.584 164.801 37.608 ;
     RECT  164.704 21.936 164.837 25.176 ;
     RECT  164.704 8.544 164.981 8.568 ;
     RECT  164.704 14.64 165.017 14.664 ;
     RECT  164.704 13.056 165.059 13.08 ;
     RECT  164.704 32.304 165.107 33.288 ;
     RECT  164.773 47.184 165.109 47.208 ;
     RECT  164.704 15.84 165.125 15.864 ;
     RECT  164.704 6.24 165.251 6.84 ;
     RECT  165.109 47.184 165.298 47.304 ;
     RECT  165.251 6.288 165.305 6.84 ;
     RECT  164.704 4.176 165.341 4.2 ;
     RECT  164.704 26.208 165.449 30.6 ;
     RECT  164.704 42.72 165.521 45.336 ;
     RECT  165.449 26.208 165.539 27.816 ;
     RECT  165.449 29.04 165.587 30.6 ;
     RECT  164.704 40.416 165.587 41.4 ;
     RECT  165.298 47.184 165.587 47.4 ;
     RECT  165.587 47.184 165.635 47.256 ;
     RECT  165.521 43.152 165.661 45.336 ;
     RECT  164.704 10.896 165.665 11.832 ;
     RECT  165.661 43.152 165.673 46.2 ;
     RECT  164.704 39.312 165.701 39.336 ;
     RECT  165.673 43.152 165.701 43.368 ;
     RECT  164.368 0.096 165.737 0.216 ;
     RECT  165.305 6.816 165.917 6.84 ;
     RECT  165.665 11.088 165.981 11.832 ;
     RECT  165.737 0.192 165.989 0.216 ;
     RECT  165.673 44.64 166.057 46.2 ;
     RECT  165.107 32.304 166.129 32.328 ;
     RECT  165.539 26.208 166.169 26.232 ;
     RECT  165.539 27.6 166.205 27.816 ;
     RECT  165.701 43.2 166.259 43.368 ;
     RECT  164.837 25.152 166.345 25.176 ;
     RECT  166.259 43.248 166.739 43.368 ;
     RECT  164.704 1.968 166.781 1.992 ;
     RECT  164.837 21.936 166.892 23.928 ;
     RECT  166.345 25.104 166.892 25.176 ;
     RECT  166.892 21.936 166.933 25.176 ;
     RECT  166.129 31.68 166.957 32.328 ;
     RECT  166.933 21.936 166.979 25.944 ;
     RECT  166.979 24.912 167.02 25.944 ;
     RECT  166.957 31.68 167.033 32.472 ;
     RECT  166.739 43.344 167.084 43.368 ;
     RECT  166.057 44.64 167.084 46.824 ;
     RECT  167.084 43.344 167.123 46.824 ;
     RECT  165.587 41.376 167.245 41.4 ;
     RECT  167.123 43.344 167.249 46.776 ;
     RECT  167.245 41.04 167.285 41.4 ;
     RECT  165.587 30.576 167.357 30.6 ;
     RECT  167.249 43.872 167.699 46.776 ;
     RECT  167.708 38.16 167.795 38.184 ;
     RECT  167.699 43.872 167.795 46.2 ;
     RECT  167.033 32.448 167.929 32.472 ;
     RECT  167.893 37.584 167.987 37.608 ;
     RECT  166.205 27.6 168.044 27.624 ;
     RECT  168.044 27.6 168.081 28.44 ;
     RECT  168.081 27.216 168.131 28.44 ;
     RECT  165.587 29.472 168.145 29.496 ;
     RECT  168.145 29.472 168.257 30.408 ;
     RECT  167.929 32.448 168.293 33.048 ;
     RECT  167.02 24.912 168.469 25.176 ;
     RECT  165.877 13.536 168.613 13.56 ;
     RECT  168.613 13.248 168.653 13.56 ;
     RECT  168.541 30.816 168.653 30.84 ;
     RECT  165.981 11.088 168.661 11.112 ;
     RECT  168.661 11.088 168.707 11.256 ;
     RECT  168.653 13.248 168.707 13.368 ;
     RECT  168.257 29.472 168.721 29.496 ;
     RECT  168.721 28.992 168.761 29.496 ;
     RECT  167.795 43.872 168.805 45.576 ;
     RECT  168.253 37.056 168.829 37.08 ;
     RECT  166.979 21.936 168.949 23.928 ;
     RECT  168.469 24.912 168.949 25.32 ;
     RECT  164.704 34.704 168.949 34.728 ;
     RECT  168.293 32.928 168.973 33.048 ;
     RECT  168.949 34.704 168.973 35.448 ;
     RECT  169.081 42.336 169.217 42.36 ;
     RECT  167.285 41.04 169.237 41.304 ;
     RECT  169.217 42.336 169.237 42.792 ;
     RECT  169.261 31.392 169.441 31.416 ;
     RECT  168.973 32.928 169.477 35.448 ;
     RECT  168.829 36.432 169.477 37.08 ;
     RECT  169.237 41.04 169.477 42.792 ;
     RECT  169.477 40.416 169.613 42.792 ;
     RECT  168.805 43.824 169.621 45.576 ;
     RECT  168.131 27.216 169.801 28.008 ;
     RECT  168.761 28.992 169.801 29.016 ;
     RECT  165.841 4.128 169.808 4.152 ;
     RECT  168.707 11.232 169.808 11.256 ;
     RECT  168.707 13.344 169.808 13.368 ;
     RECT  164.704 18.432 169.808 18.456 ;
     RECT  168.949 21.936 169.808 25.32 ;
     RECT  169.801 27.216 169.808 29.016 ;
     RECT  169.441 31.392 169.808 31.944 ;
     RECT  169.477 32.928 169.808 37.08 ;
     RECT  169.613 39.888 169.808 42.792 ;
     RECT  169.621 43.824 169.808 45.672 ;
     RECT  169.808 2.148 169.811 45.672 ;
     RECT  169.811 2.148 169.912 45.528 ;
     RECT  169.912 2.418 170.104 45.528 ;
     RECT  169.957 47.328 170.149 47.352 ;
     RECT  170.149 47.232 170.243 47.352 ;
     RECT  170.243 47.232 170.245 47.256 ;
     RECT  170.104 4.128 170.291 4.68 ;
     RECT  170.104 6.816 170.291 6.84 ;
     RECT  170.104 41.76 170.309 45.528 ;
     RECT  170.104 21.936 170.339 29.064 ;
     RECT  170.245 47.136 170.339 47.256 ;
     RECT  170.339 21.936 170.387 29.016 ;
     RECT  170.339 47.136 170.531 47.16 ;
     RECT  170.104 35.424 170.597 37.32 ;
     RECT  170.104 18.432 170.605 19.416 ;
     RECT  170.387 26.4 170.668 29.016 ;
     RECT  170.104 31.392 170.741 31.896 ;
     RECT  170.309 41.76 170.813 45.336 ;
     RECT  170.813 41.76 170.849 43.368 ;
     RECT  170.813 45.024 170.921 45.336 ;
     RECT  170.104 13.008 170.963 13.368 ;
     RECT  170.104 8.448 171.059 11.4 ;
     RECT  170.741 31.632 171.389 31.896 ;
     RECT  170.921 45.024 171.461 45.048 ;
     RECT  171.205 16.944 171.541 16.968 ;
     RECT  170.605 18.432 171.541 18.456 ;
     RECT  171.059 10.56 171.569 11.4 ;
     RECT  171.541 16.944 171.587 18.456 ;
     RECT  170.849 42.384 171.587 43.368 ;
     RECT  170.668 27.36 171.605 29.016 ;
     RECT  171.692 38.592 171.779 38.616 ;
     RECT  171.605 27.36 171.877 28.824 ;
     RECT  170.387 21.936 172.021 25.224 ;
     RECT  172.021 21.936 172.108 25.944 ;
     RECT  170.104 34.08 172.145 34.104 ;
     RECT  171.877 27.312 172.217 28.824 ;
     RECT  170.597 35.52 172.253 37.32 ;
     RECT  170.291 4.656 172.285 4.68 ;
     RECT  171.587 43.344 172.469 43.368 ;
     RECT  171.587 17.472 172.541 18.456 ;
     RECT  171.389 31.872 172.681 31.896 ;
     RECT  172.681 31.872 172.721 31.992 ;
     RECT  172.217 28.8 172.933 28.824 ;
     RECT  172.108 21.936 172.969 25.224 ;
     RECT  172.933 28.8 173.02 29.208 ;
     RECT  172.969 21.792 173.041 25.224 ;
     RECT  173.02 28.8 173.081 28.824 ;
     RECT  170.963 13.008 173.125 13.032 ;
     RECT  172.541 17.472 173.185 17.496 ;
     RECT  173.125 12.864 173.212 13.848 ;
     RECT  173.185 17.088 173.225 17.496 ;
     RECT  172.285 4.656 173.269 4.824 ;
     RECT  173.185 2.304 173.293 2.328 ;
     RECT  172.721 31.968 173.293 31.992 ;
     RECT  173.269 3.936 173.315 4.824 ;
     RECT  171.529 6.144 173.315 6.168 ;
     RECT  173.041 21.648 173.329 25.224 ;
     RECT  173.293 31.968 173.333 32.472 ;
     RECT  173.315 3.936 173.356 3.96 ;
     RECT  172.249 33.984 173.365 34.008 ;
     RECT  173.365 33.984 173.449 35.16 ;
     RECT  173.293 1.68 173.555 2.328 ;
     RECT  173.225 17.088 173.581 17.112 ;
     RECT  173.509 19.392 173.581 19.416 ;
     RECT  172.253 36.48 173.657 37.32 ;
     RECT  173.657 36.864 173.693 37.32 ;
     RECT  171.569 11.376 173.701 11.4 ;
     RECT  173.555 1.68 173.797 1.752 ;
     RECT  173.581 19.2 173.797 19.416 ;
     RECT  173.449 33.984 173.801 34.008 ;
     RECT  173.269 7.44 173.873 7.464 ;
     RECT  173.797 19.2 173.893 19.608 ;
     RECT  173.861 0.096 173.944 0.12 ;
     RECT  173.125 14.832 173.945 14.856 ;
     RECT  173.581 16.512 173.977 17.112 ;
     RECT  173.893 19.2 173.977 19.656 ;
     RECT  173.701 10.992 174.013 11.4 ;
     RECT  173.212 12.864 174.013 12.888 ;
     RECT  173.977 15.984 174.053 17.112 ;
     RECT  173.797 1.152 174.131 1.752 ;
     RECT  173.944 0.096 174.157 0.168 ;
     RECT  172.217 27.312 174.188 27.384 ;
     RECT  174.188 26.736 174.229 27.384 ;
     RECT  173.977 19.2 174.301 20.568 ;
     RECT  173.329 21.648 174.301 25.656 ;
     RECT  174.157 0.096 174.373 0.648 ;
     RECT  174.013 10.992 174.409 12.888 ;
     RECT  174.181 29.088 174.421 29.112 ;
     RECT  171.493 30.288 174.421 30.312 ;
     RECT  174.421 29.088 174.469 30.84 ;
     RECT  173.333 32.448 174.469 32.472 ;
     RECT  173.449 35.136 174.476 35.16 ;
     RECT  174.131 1.68 174.661 1.752 ;
     RECT  174.053 17.088 174.733 17.112 ;
     RECT  171.397 41.376 174.769 41.4 ;
     RECT  174.757 44.736 174.805 44.76 ;
     RECT  174.805 44.544 174.853 44.76 ;
     RECT  174.769 41.376 174.908 42.168 ;
     RECT  174.853 44.448 174.949 44.76 ;
     RECT  174.733 17.088 174.997 17.64 ;
     RECT  174.301 19.2 174.997 25.656 ;
     RECT  174.949 43.92 174.997 44.76 ;
     RECT  174.476 35.136 175.021 35.88 ;
     RECT  174.997 43.92 175.045 45.72 ;
     RECT  174.053 15.984 175.093 16.008 ;
     RECT  174.661 1.68 175.208 1.8 ;
     RECT  171.059 9.024 175.208 9.048 ;
     RECT  174.409 10.896 175.208 12.888 ;
     RECT  175.093 15.312 175.208 16.008 ;
     RECT  174.997 17.088 175.208 25.656 ;
     RECT  174.229 26.736 175.208 27.624 ;
     RECT  174.469 29.088 175.208 32.472 ;
     RECT  173.905 33.552 175.208 33.576 ;
     RECT  175.021 34.896 175.208 35.88 ;
     RECT  173.693 36.864 175.208 36.888 ;
     RECT  174.908 41.232 175.208 42.168 ;
     RECT  175.045 43.536 175.208 45.72 ;
     RECT  175.093 47.328 175.474 47.352 ;
     RECT  175.208 1.68 175.504 45.72 ;
     RECT  174.373 0.048 175.561 0.648 ;
     RECT  175.504 16.56 175.565 18.168 ;
     RECT  175.474 47.28 175.573 47.4 ;
     RECT  175.573 47.28 175.619 47.352 ;
     RECT  175.504 36.864 175.637 36.888 ;
     RECT  175.504 12.528 175.853 13.032 ;
     RECT  175.504 26.784 175.853 30.84 ;
     RECT  175.561 0.048 175.925 0.696 ;
     RECT  175.504 33.552 175.955 34.92 ;
     RECT  175.619 47.328 175.955 47.352 ;
     RECT  175.504 42.768 175.993 45.72 ;
     RECT  175.504 1.68 176.051 2.28 ;
     RECT  175.925 0.096 176.101 0.696 ;
     RECT  176.051 1.68 176.101 1.896 ;
     RECT  175.504 9.024 176.105 9.672 ;
     RECT  176.101 0.096 176.147 1.896 ;
     RECT  175.993 42.768 176.177 46.2 ;
     RECT  176.177 45.024 176.243 46.2 ;
     RECT  175.853 26.784 176.321 27.624 ;
     RECT  176.147 0.096 176.339 1.752 ;
     RECT  175.504 41.376 176.357 41.4 ;
     RECT  175.853 29.04 176.38 30.84 ;
     RECT  176.38 29.904 176.393 30.84 ;
     RECT  176.339 0.096 176.473 0.12 ;
     RECT  175.504 20.64 176.533 20.664 ;
     RECT  175.504 21.792 176.533 25.272 ;
     RECT  176.339 1.728 176.573 1.752 ;
     RECT  175.504 19.584 176.669 19.608 ;
     RECT  176.533 20.64 176.669 25.272 ;
     RECT  176.669 19.584 176.753 25.272 ;
     RECT  176.393 29.904 176.753 30.792 ;
     RECT  176.741 47.28 176.78 47.304 ;
     RECT  176.753 19.584 176.893 19.608 ;
     RECT  176.177 42.768 176.917 43.944 ;
     RECT  176.753 30.144 176.969 30.792 ;
     RECT  176.753 20.64 177.005 25.272 ;
     RECT  175.565 16.56 177.013 17.544 ;
     RECT  176.893 19.392 177.013 19.608 ;
     RECT  177.013 16.56 177.059 19.608 ;
     RECT  176.243 45.024 177.062 45.624 ;
     RECT  176.105 9.024 177.113 9.096 ;
     RECT  176.917 42.672 177.181 43.944 ;
     RECT  177.062 45.024 177.181 45.576 ;
     RECT  177.113 9.024 177.185 9.048 ;
     RECT  175.955 34.896 177.185 34.92 ;
     RECT  177.059 18.24 177.251 19.608 ;
     RECT  177.181 42.672 177.293 45.576 ;
     RECT  176.78 46.752 177.395 47.304 ;
     RECT  177.251 18.24 177.401 19.32 ;
     RECT  177.293 43.152 177.443 45.576 ;
     RECT  176.497 40.416 177.493 40.44 ;
     RECT  175.504 31.872 177.577 31.896 ;
     RECT  177.443 43.2 177.581 45.576 ;
     RECT  177.397 47.328 177.587 47.352 ;
     RECT  177.577 31.872 177.617 32.088 ;
     RECT  177.581 43.728 177.731 45.576 ;
     RECT  177.731 43.872 177.779 45.576 ;
     RECT  177.779 44.448 177.833 45.576 ;
     RECT  177.005 20.64 178.045 25.08 ;
     RECT  175.504 10.896 178.049 11.16 ;
     RECT  175.504 38.352 178.076 38.376 ;
     RECT  177.493 39.6 178.076 40.44 ;
     RECT  178.076 38.352 178.085 40.44 ;
     RECT  175.955 33.552 178.117 33.576 ;
     RECT  178.085 38.352 178.163 39.384 ;
     RECT  178.049 10.992 178.261 11.16 ;
     RECT  176.321 27.312 178.261 27.624 ;
     RECT  178.085 40.416 178.265 40.44 ;
     RECT  178.163 39.36 178.345 39.384 ;
     RECT  175.504 15.312 178.357 15.336 ;
     RECT  177.059 16.56 178.357 16.584 ;
     RECT  178.357 15.312 178.373 16.584 ;
     RECT  178.373 15.84 178.403 16.584 ;
     RECT  177.833 45.552 178.517 45.576 ;
     RECT  178.261 26.784 178.585 27.624 ;
     RECT  176.969 30.144 178.621 30.168 ;
     RECT  177.401 19.296 178.657 19.32 ;
     RECT  178.045 20.592 178.661 25.08 ;
     RECT  178.621 30 178.661 30.168 ;
     RECT  177.617 32.064 178.693 32.088 ;
     RECT  177.401 18.24 178.697 18.264 ;
     RECT  178.585 26.64 178.697 27.624 ;
     RECT  178.697 26.784 178.741 27.624 ;
     RECT  177.833 44.448 178.777 44.472 ;
     RECT  178.403 15.84 178.913 16.248 ;
     RECT  178.661 20.88 178.981 25.08 ;
     RECT  178.981 20.88 178.985 25.752 ;
     RECT  178.741 27.312 178.985 27.624 ;
     RECT  178.661 30 178.988 30.024 ;
     RECT  178.985 21.936 179.057 25.752 ;
     RECT  178.988 29.04 179.075 30.024 ;
     RECT  179.057 21.984 179.129 25.752 ;
     RECT  178.693 32.064 179.129 32.472 ;
     RECT  178.261 10.992 179.197 11.208 ;
     RECT  179.197 10.8 179.221 11.208 ;
     RECT  178.985 27.6 179.237 27.624 ;
     RECT  179.221 10.8 179.281 11.256 ;
     RECT  178.117 33.552 179.489 34.392 ;
     RECT  179.129 32.064 179.561 32.088 ;
     RECT  175.853 13.008 179.773 13.032 ;
     RECT  179.621 0.576 179.809 0.6 ;
     RECT  179.749 1.728 179.837 1.752 ;
     RECT  178.913 16.224 179.893 16.248 ;
     RECT  179.893 16.224 179.917 17.064 ;
     RECT  179.809 0.096 180.025 0.6 ;
     RECT  179.837 1.728 180.025 1.8 ;
     RECT  180.025 0.096 180.109 1.8 ;
     RECT  179.129 22.032 180.169 25.752 ;
     RECT  179.485 27.888 180.325 27.912 ;
     RECT  178.657 19.296 180.38 19.368 ;
     RECT  179.917 15.36 180.383 17.064 ;
     RECT  180.38 18.384 180.383 19.368 ;
     RECT  179.989 39.888 180.457 39.912 ;
     RECT  179.075 30 180.469 30.024 ;
     RECT  179.489 34.368 180.469 34.392 ;
     RECT  180.109 1.728 180.493 1.8 ;
     RECT  180.169 21.984 180.493 25.752 ;
     RECT  178.985 20.88 180.601 20.904 ;
     RECT  180.493 21.936 180.601 25.752 ;
     RECT  180.493 1.728 180.608 1.848 ;
     RECT  179.281 10.992 180.608 11.256 ;
     RECT  179.773 12.864 180.608 13.032 ;
     RECT  180.383 15.36 180.608 19.368 ;
     RECT  180.601 20.88 180.608 25.752 ;
     RECT  180.325 27.312 180.608 27.912 ;
     RECT  180.469 29.472 180.608 30.024 ;
     RECT  180.469 34.368 180.608 34.68 ;
     RECT  180.457 39.36 180.608 39.912 ;
     RECT  179.989 44.448 180.608 44.472 ;
     RECT  180.608 1.728 180.712 45.372 ;
     RECT  180.712 1.728 180.904 45.102 ;
     RECT  180.904 19.056 181.139 19.32 ;
     RECT  180.109 0.096 181.141 0.648 ;
     RECT  180.904 1.728 181.141 2.28 ;
     RECT  180.904 20.592 181.18 25.752 ;
     RECT  181.18 20.976 181.433 25.752 ;
     RECT  181.433 20.976 181.505 24.792 ;
     RECT  180.904 15.984 181.649 16.008 ;
     RECT  181.505 21.12 181.757 24.792 ;
     RECT  181.141 0.096 181.811 2.28 ;
     RECT  180.904 12.528 181.945 12.552 ;
     RECT  181.757 21.696 182.081 24.792 ;
     RECT  180.904 17.616 182.261 17.64 ;
     RECT  181.811 0.096 182.291 1.8 ;
     RECT  181.139 19.056 182.333 19.08 ;
     RECT  182.291 0.096 182.369 1.752 ;
     RECT  182.369 0.096 182.387 1.128 ;
     RECT  182.387 0.192 182.579 1.128 ;
     RECT  182.579 0.192 182.675 0.216 ;
     RECT  180.904 10.992 186.008 11.4 ;
     RECT  182.081 22.032 186.008 24.792 ;
     RECT  186.008 2.148 186.112 45.372 ;
     RECT  186.112 2.418 186.304 45.102 ;
     RECT  186.304 10.992 191.408 11.4 ;
     RECT  186.304 22.032 191.408 22.056 ;
     RECT  186.304 23.088 191.408 24.792 ;
     RECT  191.408 2.148 191.512 45.372 ;
     RECT  191.512 2.208 191.704 45.102 ;
     RECT  191.704 2.208 196.808 2.232 ;
     RECT  191.704 10.992 196.808 11.16 ;
     RECT  191.704 22.032 196.808 22.056 ;
     RECT  191.704 23.088 196.808 24.792 ;
     RECT  196.808 2.148 196.912 45.372 ;
     RECT  196.912 2.208 197.104 45.102 ;
     RECT  197.104 2.208 202.208 2.232 ;
     RECT  197.104 10.992 202.208 11.16 ;
     RECT  197.104 22.032 202.208 22.056 ;
     RECT  197.104 23.088 202.208 24.792 ;
     RECT  202.208 2.148 202.312 45.372 ;
     RECT  202.312 2.208 202.504 45.102 ;
     RECT  202.504 2.208 207.608 2.232 ;
     RECT  202.504 10.992 207.608 11.16 ;
     RECT  202.504 22.032 207.608 22.056 ;
     RECT  202.504 23.088 207.608 24.792 ;
     RECT  207.608 2.148 207.712 45.372 ;
     RECT  207.712 2.208 207.904 45.102 ;
     RECT  207.904 2.208 213.008 2.232 ;
     RECT  207.904 10.992 213.008 11.16 ;
     RECT  207.904 22.032 213.008 22.056 ;
     RECT  207.904 23.088 213.008 24.792 ;
     RECT  213.008 2.148 213.112 45.372 ;
     RECT  213.112 2.208 213.304 45.102 ;
     RECT  213.304 2.208 218.408 2.232 ;
     RECT  213.304 10.992 218.408 11.16 ;
     RECT  213.304 22.032 218.408 22.056 ;
     RECT  213.304 23.088 218.408 24.792 ;
     RECT  218.408 2.148 218.512 45.372 ;
     RECT  218.512 2.208 218.704 45.102 ;
     RECT  218.704 10.992 222.329 11.16 ;
     RECT  218.704 2.208 223.808 2.232 ;
     RECT  222.329 11.136 223.808 11.16 ;
     RECT  218.704 22.032 223.808 22.056 ;
     RECT  218.704 23.088 223.808 24.792 ;
     RECT  223.808 2.148 223.912 45.372 ;
     RECT  223.912 2.208 224.104 45.102 ;
     RECT  224.104 2.208 226.285 2.232 ;
     RECT  226.285 2.064 226.325 2.232 ;
     RECT  226.325 2.064 229.208 2.088 ;
     RECT  224.104 11.136 229.208 11.16 ;
     RECT  224.104 22.032 229.208 22.056 ;
     RECT  224.104 23.088 229.208 24.792 ;
     RECT  229.208 2.064 229.312 45.372 ;
     RECT  229.312 2.064 229.504 45.102 ;
     RECT  229.504 2.064 230.429 2.28 ;
     RECT  230.429 2.064 230.465 2.184 ;
     RECT  230.465 2.064 232.261 2.088 ;
     RECT  232.261 2.064 234.608 2.28 ;
     RECT  229.504 11.136 234.608 11.16 ;
     RECT  229.504 22.032 234.608 22.056 ;
     RECT  229.504 23.088 234.608 24.792 ;
     RECT  234.608 2.064 234.712 45.372 ;
     RECT  234.712 2.064 234.904 45.102 ;
     RECT  234.904 2.064 237.341 2.28 ;
     RECT  237.341 2.064 237.629 2.232 ;
     RECT  237.629 2.208 239.353 2.232 ;
     RECT  239.353 2.064 240.008 2.232 ;
     RECT  234.904 11.136 240.008 11.16 ;
     RECT  234.904 22.032 240.008 22.056 ;
     RECT  234.904 23.088 240.008 24.792 ;
     RECT  240.008 2.064 240.112 45.372 ;
     RECT  240.112 2.064 240.221 45.102 ;
     RECT  240.221 2.208 240.304 45.102 ;
     RECT  240.304 2.208 244.289 2.232 ;
     RECT  240.304 22.032 244.501 22.056 ;
     RECT  240.304 23.088 244.501 24.792 ;
     RECT  244.501 22.032 244.789 24.792 ;
     RECT  244.501 2.832 245.408 2.856 ;
     RECT  240.304 11.136 245.408 11.16 ;
     RECT  244.789 21.12 245.408 24.792 ;
     RECT  245.408 2.148 245.512 45.372 ;
     RECT  245.512 2.418 245.704 45.102 ;
     RECT  245.704 11.136 250.808 11.16 ;
     RECT  245.704 21.12 250.808 24.792 ;
     RECT  250.808 2.148 250.912 45.372 ;
     RECT  250.912 2.418 251.104 45.102 ;
     RECT  251.104 11.136 256.208 11.16 ;
     RECT  251.104 21.12 256.208 24.792 ;
     RECT  256.208 2.148 256.312 45.372 ;
     RECT  256.312 2.418 256.504 45.102 ;
     RECT  256.504 11.136 261.608 11.16 ;
     RECT  256.504 21.12 261.608 24.792 ;
     RECT  261.608 2.148 261.712 45.372 ;
     RECT  261.712 2.418 261.904 45.102 ;
     RECT  261.904 11.136 267.008 11.16 ;
     RECT  261.904 21.12 267.008 24.792 ;
     RECT  267.008 2.148 267.112 45.372 ;
     RECT  267.112 2.418 267.304 45.102 ;
     RECT  267.304 11.136 272.408 11.16 ;
     RECT  267.304 21.12 272.408 24.792 ;
     RECT  272.408 2.148 272.512 45.372 ;
     RECT  272.512 2.418 272.704 45.102 ;
     RECT  272.704 11.136 277.808 11.16 ;
     RECT  272.704 21.12 277.808 24.792 ;
     RECT  277.808 2.148 277.912 45.372 ;
     RECT  277.912 2.418 278.104 45.102 ;
     RECT  278.104 11.136 283.208 11.16 ;
     RECT  278.104 21.12 283.208 24.792 ;
     RECT  283.208 2.148 283.312 45.372 ;
     RECT  283.312 2.418 283.504 45.102 ;
     RECT  284.605 19.872 285.793 19.896 ;
     RECT  283.504 21.12 286.193 24.792 ;
     RECT  283.504 11.136 288.608 11.16 ;
     RECT  285.793 19.872 288.608 20.136 ;
     RECT  286.193 21.12 288.608 24.696 ;
     RECT  288.608 2.148 288.712 45.372 ;
     RECT  288.712 2.418 288.904 45.102 ;
     RECT  288.904 21.12 290.113 24.696 ;
     RECT  290.113 21.12 290.197 25.752 ;
     RECT  288.904 19.872 290.473 20.136 ;
     RECT  290.197 21.12 290.473 24.648 ;
     RECT  290.197 25.728 291.229 25.752 ;
     RECT  290.473 19.872 291.805 24.648 ;
     RECT  291.229 25.728 291.913 25.8 ;
     RECT  291.805 19.392 291.985 24.648 ;
     RECT  291.985 19.392 292.057 24.696 ;
     RECT  291.913 25.728 292.057 25.992 ;
     RECT  292.057 19.392 292.129 25.992 ;
     RECT  292.129 19.2 292.355 25.992 ;
     RECT  292.355 19.2 293.852 25.032 ;
     RECT  293.852 18.72 293.893 25.032 ;
     RECT  288.904 11.136 294.008 11.16 ;
     RECT  293.893 18.192 294.008 25.032 ;
     RECT  294.008 2.148 294.112 45.372 ;
     RECT  294.112 2.418 294.304 45.102 ;
     RECT  294.304 17.568 294.473 25.032 ;
     RECT  294.473 17.568 295.693 24.936 ;
     RECT  295.693 17.472 296.243 24.936 ;
     RECT  296.243 17.568 296.453 24.936 ;
     RECT  296.453 19.632 296.525 24.936 ;
     RECT  294.304 11.136 296.675 11.16 ;
     RECT  296.525 19.872 297.673 24.936 ;
     RECT  296.453 17.568 297.709 18.264 ;
     RECT  297.673 19.536 297.709 24.936 ;
     RECT  297.709 17.568 297.749 24.936 ;
     RECT  297.749 17.568 297.857 17.64 ;
     RECT  297.857 17.568 297.929 17.592 ;
     RECT  296.485 16.272 299.408 16.296 ;
     RECT  297.749 18.72 299.408 24.936 ;
     RECT  299.408 2.148 299.512 45.372 ;
     RECT  299.512 2.418 299.704 45.102 ;
     RECT  299.704 21.504 300.521 24.936 ;
     RECT  299.704 16.272 300.953 20.424 ;
     RECT  300.953 16.512 301.277 20.424 ;
     RECT  301.277 16.512 302.033 18.792 ;
     RECT  302.033 18.048 302.141 18.792 ;
     RECT  301.277 19.824 302.293 20.424 ;
     RECT  300.521 21.504 302.293 24.408 ;
     RECT  302.293 19.824 302.38 24.408 ;
     RECT  302.141 18.144 302.537 18.792 ;
     RECT  302.38 21.504 302.569 24.408 ;
     RECT  302.537 18.144 302.573 18.168 ;
     RECT  302.033 16.512 302.681 16.92 ;
     RECT  302.569 21.504 302.915 25.704 ;
     RECT  302.38 19.824 303.397 20.424 ;
     RECT  303.397 19.68 304.045 20.424 ;
     RECT  302.681 16.512 304.117 16.776 ;
     RECT  304.117 16.416 304.316 16.776 ;
     RECT  304.045 19.392 304.765 20.424 ;
     RECT  304.316 16.416 304.808 17.208 ;
     RECT  304.765 18.72 304.808 20.424 ;
     RECT  302.915 21.504 304.808 25.272 ;
     RECT  304.808 2.148 304.912 45.372 ;
     RECT  304.912 2.418 305.104 45.102 ;
     RECT  305.104 16.944 305.201 17.112 ;
     RECT  305.104 18.432 305.777 25.272 ;
     RECT  305.777 18.432 305.849 25.176 ;
     RECT  305.849 18.432 305.921 18.744 ;
     RECT  305.921 18.432 307.069 18.504 ;
     RECT  307.069 18.432 307.177 18.792 ;
     RECT  307.177 18.432 307.249 18.84 ;
     RECT  305.849 19.872 307.645 25.176 ;
     RECT  305.201 16.944 307.813 16.968 ;
     RECT  307.249 18.432 307.813 18.888 ;
     RECT  307.813 16.944 307.825 18.888 ;
     RECT  307.825 16.656 307.9 18.888 ;
     RECT  307.645 19.872 308.003 26.088 ;
     RECT  307.9 18.432 308.149 18.888 ;
     RECT  308.003 19.872 308.149 25.08 ;
     RECT  308.149 18.432 308.225 25.08 ;
     RECT  308.225 18.816 308.873 25.08 ;
     RECT  308.873 19.632 309.125 25.08 ;
     RECT  307.9 16.656 309.661 16.68 ;
     RECT  309.877 18.144 310.069 18.168 ;
     RECT  309.661 15.936 310.208 16.68 ;
     RECT  310.069 18.048 310.208 18.168 ;
     RECT  309.125 19.632 310.208 24.504 ;
     RECT  308.003 26.064 310.208 26.088 ;
     RECT  310.208 2.148 310.312 45.372 ;
     RECT  310.312 2.418 310.504 45.102 ;
     RECT  310.504 19.632 310.643 24.408 ;
     RECT  310.504 26.064 311.105 26.088 ;
     RECT  310.504 18.144 311.605 18.168 ;
     RECT  310.643 19.776 311.677 24.408 ;
     RECT  311.605 17.904 312.001 18.168 ;
     RECT  312.001 17.904 312.073 18.216 ;
     RECT  311.677 19.776 312.073 24.792 ;
     RECT  312.073 17.904 312.293 24.792 ;
     RECT  311.605 25.776 312.401 25.8 ;
     RECT  310.504 15.888 312.797 16.584 ;
     RECT  312.797 16.416 312.941 16.584 ;
     RECT  312.293 17.904 313.621 24.456 ;
     RECT  313.621 17.568 314.053 24.456 ;
     RECT  313.873 25.536 314.053 25.56 ;
     RECT  314.053 17.568 314.099 25.56 ;
     RECT  314.099 17.568 314.201 25.416 ;
     RECT  312.941 16.416 314.237 16.44 ;
     RECT  314.201 17.664 315.608 25.416 ;
     RECT  315.608 2.148 315.712 45.372 ;
     RECT  315.712 2.418 315.904 45.102 ;
     RECT  315.904 17.664 316.325 26.04 ;
     RECT  316.325 19.152 316.403 26.04 ;
     RECT  316.403 19.152 317.369 25.56 ;
     RECT  316.325 17.664 317.441 18.168 ;
     RECT  317.369 19.152 317.555 24.936 ;
     RECT  317.441 17.952 318.053 18.168 ;
     RECT  317.555 19.248 318.841 24.936 ;
     RECT  318.053 18.144 319.133 18.168 ;
     RECT  318.841 19.248 319.993 25.08 ;
     RECT  319.993 18.768 320.173 25.08 ;
     RECT  320.173 18 321.008 25.08 ;
     RECT  321.008 2.148 321.112 45.372 ;
     RECT  321.112 2.418 321.304 45.102 ;
     RECT  321.304 19.872 322.661 24.648 ;
     RECT  322.661 19.872 323.093 24.408 ;
     RECT  321.304 18.768 323.161 18.792 ;
     RECT  323.161 18.768 323.233 18.888 ;
     RECT  323.093 19.872 323.233 20.52 ;
     RECT  323.233 18.768 323.273 20.52 ;
     RECT  323.273 18.864 323.633 20.52 ;
     RECT  323.093 21.744 323.665 24.408 ;
     RECT  323.633 18.864 324.569 20.136 ;
     RECT  324.569 19.344 324.749 20.136 ;
     RECT  323.665 21.744 325.249 24.504 ;
     RECT  324.749 19.872 325.285 20.136 ;
     RECT  325.249 21.504 325.285 24.504 ;
     RECT  325.285 19.872 325.397 24.504 ;
     RECT  325.397 19.872 325.469 20.328 ;
     RECT  325.397 21.504 326.041 24.504 ;
     RECT  326.041 21.504 326.365 25.416 ;
     RECT  326.365 21.456 326.401 25.416 ;
     RECT  325.469 19.92 326.581 20.328 ;
     RECT  326.401 21.36 326.581 25.416 ;
     RECT  326.581 19.92 326.617 25.416 ;
     RECT  326.617 19.92 328.284 25.512 ;
    LAYER M5 ;
     RECT  135.12 0.016 164.424 0.227 ;
     RECT  179.664 0.016 182.664 0.227 ;
     RECT  179.664 0.227 182.568 0.611 ;
     RECT  179.76 0.611 182.568 1.139 ;
     RECT  135.12 0.227 164.232 1.763 ;
     RECT  173.52 0.016 176.52 1.763 ;
     RECT  179.76 1.139 182.28 1.763 ;
     RECT  135.216 1.763 164.232 1.811 ;
     RECT  173.52 1.763 176.136 1.811 ;
     RECT  179.856 1.763 182.28 1.811 ;
     RECT  180.528 1.811 181.8 1.859 ;
     RECT  175.2 1.811 176.136 1.907 ;
     RECT  135.312 1.811 164.232 2.137 ;
     RECT  2.4 2.137 2.52 2.151 ;
     RECT  7.8 2.137 7.92 2.151 ;
     RECT  13.2 2.137 13.32 2.151 ;
     RECT  18.6 2.137 18.72 2.151 ;
     RECT  24 2.137 24.12 2.151 ;
     RECT  29.4 2.137 29.52 2.151 ;
     RECT  34.8 2.137 34.92 2.151 ;
     RECT  40.2 2.137 40.32 2.151 ;
     RECT  45.6 2.137 45.72 2.151 ;
     RECT  51 2.137 51.12 2.151 ;
     RECT  56.4 2.137 56.52 2.151 ;
     RECT  61.8 2.137 61.92 2.151 ;
     RECT  67.2 2.137 67.32 2.151 ;
     RECT  72.6 2.137 72.72 2.151 ;
     RECT  78 2.137 78.12 2.151 ;
     RECT  83.4 2.137 83.52 2.151 ;
     RECT  88.8 2.137 88.92 2.151 ;
     RECT  94.2 2.137 94.32 2.151 ;
     RECT  99.6 2.137 99.72 2.151 ;
     RECT  105 2.137 105.12 2.151 ;
     RECT  110.4 2.137 110.52 2.151 ;
     RECT  115.8 2.137 115.92 2.151 ;
     RECT  121.2 2.137 121.32 2.151 ;
     RECT  126.6 2.137 126.72 2.151 ;
     RECT  132 2.137 132.12 2.151 ;
     RECT  135.312 2.137 164.52 2.151 ;
     RECT  169.8 2.137 169.92 2.151 ;
     RECT  186 2.137 186.12 2.151 ;
     RECT  191.4 2.137 191.52 2.151 ;
     RECT  196.8 2.137 196.92 2.151 ;
     RECT  202.2 2.137 202.32 2.151 ;
     RECT  207.6 2.137 207.72 2.151 ;
     RECT  213 2.137 213.12 2.151 ;
     RECT  218.4 2.137 218.52 2.151 ;
     RECT  223.8 2.137 223.92 2.151 ;
     RECT  229.2 2.137 229.32 2.151 ;
     RECT  230.304 2.053 230.328 2.151 ;
     RECT  234.6 2.137 234.72 2.151 ;
     RECT  240 2.137 240.12 2.151 ;
     RECT  245.4 2.137 245.52 2.151 ;
     RECT  250.8 2.137 250.92 2.151 ;
     RECT  256.2 2.137 256.32 2.151 ;
     RECT  261.6 2.137 261.72 2.151 ;
     RECT  267 2.137 267.12 2.151 ;
     RECT  272.4 2.137 272.52 2.151 ;
     RECT  277.8 2.137 277.92 2.151 ;
     RECT  283.2 2.137 283.32 2.151 ;
     RECT  288.6 2.137 288.72 2.151 ;
     RECT  294 2.137 294.12 2.151 ;
     RECT  299.4 2.137 299.52 2.151 ;
     RECT  304.8 2.137 304.92 2.151 ;
     RECT  310.2 2.137 310.32 2.151 ;
     RECT  315.6 2.137 315.72 2.151 ;
     RECT  321 2.137 321.12 2.151 ;
     RECT  229.2 2.151 230.328 2.195 ;
     RECT  191.4 2.151 191.712 2.197 ;
     RECT  175.2 1.907 176.04 2.291 ;
     RECT  180.6 1.859 181.8 2.291 ;
     RECT  135.312 2.151 164.712 2.339 ;
     RECT  173.52 1.811 173.736 2.339 ;
     RECT  135.408 2.339 164.712 2.483 ;
     RECT  245.4 2.151 245.712 2.821 ;
     RECT  135.408 2.483 162.12 2.915 ;
     RECT  135.408 2.915 155.112 3.443 ;
     RECT  135.504 3.443 155.112 3.491 ;
     RECT  156.096 2.915 156.168 3.925 ;
     RECT  157.152 2.915 162.12 3.925 ;
     RECT  173.712 2.339 173.736 3.925 ;
     RECT  135.504 3.491 154.872 4.019 ;
     RECT  135.6 4.019 135.624 4.067 ;
     RECT  136.8 4.019 154.344 4.067 ;
     RECT  156.096 3.925 162.12 4.115 ;
     RECT  169.8 2.151 170.112 4.117 ;
     RECT  153.408 4.067 154.344 4.259 ;
     RECT  136.8 4.067 152.376 4.595 ;
     RECT  156.912 4.115 162.12 4.595 ;
     RECT  145.2 4.595 152.376 4.643 ;
     RECT  139.008 4.595 144.216 4.691 ;
     RECT  145.296 4.643 152.376 4.691 ;
     RECT  161.616 4.595 161.736 4.739 ;
     RECT  139.392 4.691 141.336 4.787 ;
     RECT  156.912 4.595 160.584 4.883 ;
     RECT  136.8 4.595 137.712 5.171 ;
     RECT  145.296 4.691 151.56 5.747 ;
     RECT  142.368 4.691 144.216 5.843 ;
     RECT  137.4 5.171 137.712 6.229 ;
     RECT  156.912 4.883 157.464 6.229 ;
     RECT  163.536 2.483 164.712 6.229 ;
     RECT  158.688 4.883 160.584 6.805 ;
     RECT  169.8 4.117 170.28 6.851 ;
     RECT  158.448 6.805 160.584 6.899 ;
     RECT  158.448 6.899 160.152 6.947 ;
     RECT  145.296 5.747 151.272 7.381 ;
     RECT  137.4 6.229 137.928 7.475 ;
     RECT  142.464 5.843 144.216 7.475 ;
     RECT  173.28 3.925 173.736 7.475 ;
     RECT  158.544 6.947 160.152 7.619 ;
     RECT  145.296 7.381 151.32 8.003 ;
     RECT  163.536 6.229 165.24 8.003 ;
     RECT  169.8 6.851 170.112 8.437 ;
     RECT  163.632 8.003 165.24 8.579 ;
     RECT  175.2 2.291 175.512 9.637 ;
     RECT  161.616 4.739 161.64 9.731 ;
     RECT  142.464 7.475 143.448 9.827 ;
     RECT  156.672 6.229 157.464 10.213 ;
     RECT  137.4 7.475 137.712 10.501 ;
     RECT  169.8 8.437 171.048 10.595 ;
     RECT  140.016 4.787 141.336 10.837 ;
     RECT  164.4 8.579 165.24 10.837 ;
     RECT  155.472 6.229 155.496 10.883 ;
     RECT  164.304 10.837 165.24 10.979 ;
     RECT  173.712 7.475 173.736 11.027 ;
     RECT  175.2 9.637 176.088 11.027 ;
     RECT  164.4 10.979 165.24 11.123 ;
     RECT  179.232 10.789 179.256 11.125 ;
     RECT  191.4 2.197 192.024 11.171 ;
     RECT  180.6 2.291 180.912 11.221 ;
     RECT  178.368 11.125 179.256 11.267 ;
     RECT  162.432 10.213 162.456 11.699 ;
     RECT  175.2 11.027 175.512 11.893 ;
     RECT  164.4 11.123 164.712 11.941 ;
     RECT  136.944 10.501 137.712 12.467 ;
     RECT  139.824 10.837 141.336 12.563 ;
     RECT  180.6 11.221 181.896 12.563 ;
     RECT  174.192 11.893 175.512 12.899 ;
     RECT  164.16 11.941 164.712 12.995 ;
     RECT  145.536 8.003 151.32 13.045 ;
     RECT  164.4 12.995 164.712 13.045 ;
     RECT  165.888 11.797 165.912 13.045 ;
     RECT  168.672 11.077 168.696 13.283 ;
     RECT  169.8 10.595 170.952 13.379 ;
     RECT  142.56 9.827 143.448 13.429 ;
     RECT  164.4 13.045 165.912 13.571 ;
     RECT  142.56 13.429 143.688 14.243 ;
     RECT  164.4 13.571 165.048 14.629 ;
     RECT  153.504 4.259 154.344 14.725 ;
     RECT  163.536 14.629 165.048 14.867 ;
     RECT  173.136 12.853 173.16 14.867 ;
     RECT  174.192 12.899 174.216 15.301 ;
     RECT  175.2 12.899 175.512 15.301 ;
     RECT  142.56 14.243 143.448 15.491 ;
     RECT  144.816 13.045 151.32 15.829 ;
     RECT  310.2 2.151 310.512 15.925 ;
     RECT  153.504 14.725 154.44 16.019 ;
     RECT  174.192 15.301 175.512 16.019 ;
     RECT  180.6 12.563 180.912 16.213 ;
     RECT  296.64 11.125 296.664 16.307 ;
     RECT  304.8 2.151 305.112 16.405 ;
     RECT  178.368 11.267 178.392 16.549 ;
     RECT  156.576 10.213 157.464 16.595 ;
     RECT  177.984 16.549 178.392 16.595 ;
     RECT  144.576 15.829 151.32 16.691 ;
     RECT  179.904 16.213 180.912 17.075 ;
     RECT  162.72 15.829 162.744 17.123 ;
     RECT  304.368 16.405 305.112 17.219 ;
     RECT  301.488 16.501 301.512 17.363 ;
     RECT  177.984 16.595 178.008 17.509 ;
     RECT  314.064 16.405 314.088 17.603 ;
     RECT  174.192 16.019 174.216 18.133 ;
     RECT  175.2 16.019 175.512 18.133 ;
     RECT  153.504 16.019 154.344 18.275 ;
     RECT  180.432 17.075 180.912 18.419 ;
     RECT  169.8 13.379 170.112 18.421 ;
     RECT  171.552 16.933 171.576 18.467 ;
     RECT  307.824 17.605 307.848 18.467 ;
     RECT  304.8 17.219 305.112 18.469 ;
     RECT  140.016 12.563 141.336 18.565 ;
     RECT  142.56 15.491 143.304 18.565 ;
     RECT  299.4 2.151 299.712 18.613 ;
     RECT  294 2.151 294.312 18.709 ;
     RECT  137.4 12.467 137.712 18.805 ;
     RECT  144.816 16.691 151.32 18.851 ;
     RECT  137.4 18.805 138.648 18.947 ;
     RECT  296.208 17.461 296.232 18.995 ;
     RECT  293.904 18.709 294.312 19.235 ;
     RECT  180.6 18.419 180.912 19.285 ;
     RECT  169.8 18.421 170.568 19.427 ;
     RECT  177.024 17.509 178.008 19.427 ;
     RECT  174.192 18.133 175.512 19.429 ;
     RECT  304.8 18.469 305.352 19.475 ;
     RECT  140.016 18.565 143.304 19.571 ;
     RECT  177.216 19.427 178.008 19.619 ;
     RECT  309.696 15.925 310.512 19.621 ;
     RECT  173.904 19.429 175.512 19.667 ;
     RECT  164.4 14.867 165.048 19.909 ;
     RECT  299.4 18.613 300.168 20.003 ;
     RECT  309.696 19.621 310.632 20.053 ;
     RECT  317.52 19.141 317.544 20.149 ;
     RECT  294 19.235 294.312 20.437 ;
     RECT  150.768 18.851 151.32 20.533 ;
     RECT  316.896 20.149 317.544 20.579 ;
     RECT  318.72 19.909 318.744 20.581 ;
     RECT  174.192 19.667 175.512 20.629 ;
     RECT  176.688 20.485 176.712 20.629 ;
     RECT  302.304 18.613 302.328 20.867 ;
     RECT  316.896 20.579 316.92 21.011 ;
     RECT  294 20.437 295.08 21.107 ;
     RECT  142.8 19.571 143.304 21.109 ;
     RECT  144.816 18.851 149.688 21.109 ;
     RECT  150.768 20.533 151.8 21.109 ;
     RECT  142.464 21.109 143.304 21.155 ;
     RECT  244.8 2.821 245.712 21.155 ;
     RECT  318.096 20.581 318.744 21.155 ;
     RECT  144.816 21.109 151.8 21.203 ;
     RECT  309.504 20.053 310.632 21.299 ;
     RECT  288.6 2.151 288.912 21.397 ;
     RECT  177.984 19.619 178.008 21.493 ;
     RECT  149.856 21.203 151.8 21.539 ;
     RECT  174.192 20.629 176.712 21.539 ;
     RECT  318.384 21.155 318.744 21.635 ;
     RECT  142.464 21.155 143.112 21.683 ;
     RECT  156.576 16.595 156.936 21.683 ;
     RECT  163.632 19.909 165.048 21.683 ;
     RECT  304.8 19.475 305.208 21.733 ;
     RECT  304.416 21.733 305.208 21.877 ;
     RECT  177.984 21.493 178.44 21.925 ;
     RECT  180.6 19.285 181.128 21.925 ;
     RECT  156.576 21.683 156.792 21.971 ;
     RECT  309.504 21.299 310.512 21.971 ;
     RECT  294 21.107 294.312 21.973 ;
     RECT  304.224 21.877 305.208 22.067 ;
     RECT  302.592 21.925 302.616 22.069 ;
     RECT  169.8 19.427 170.112 22.165 ;
     RECT  142.8 21.683 143.112 22.213 ;
     RECT  161.28 19.477 161.304 22.259 ;
     RECT  312.336 21.637 312.36 22.451 ;
     RECT  174.192 21.539 176.184 22.499 ;
     RECT  302.592 22.069 303.768 22.499 ;
     RECT  312.432 22.453 312.456 22.549 ;
     RECT  312.432 22.549 312.552 22.595 ;
     RECT  168.96 22.165 170.112 22.741 ;
     RECT  312.528 22.595 312.552 22.787 ;
     RECT  308.352 22.693 308.376 22.789 ;
     RECT  309.6 21.971 310.512 22.789 ;
     RECT  177.984 21.925 178.968 22.835 ;
     RECT  295.824 22.693 295.848 22.835 ;
     RECT  302.592 22.499 302.856 22.933 ;
     RECT  308.112 22.789 308.616 22.933 ;
     RECT  312.864 22.837 312.888 22.979 ;
     RECT  297.264 22.309 297.288 22.981 ;
     RECT  299.4 20.003 299.712 22.981 ;
     RECT  150.768 21.539 151.8 23.027 ;
     RECT  142.8 22.213 143.208 23.075 ;
     RECT  309.6 22.789 310.632 23.077 ;
     RECT  304.8 22.067 305.208 23.123 ;
     RECT  308.016 22.933 308.616 23.267 ;
     RECT  309.6 23.077 310.728 23.267 ;
     RECT  153.6 18.275 154.344 23.269 ;
     RECT  296.4 22.981 297.288 23.315 ;
     RECT  299.4 22.981 300.168 23.315 ;
     RECT  302.112 22.933 302.856 23.315 ;
     RECT  310.2 23.267 310.728 23.315 ;
     RECT  180.6 21.925 181.8 23.317 ;
     RECT  168.96 22.741 170.52 23.411 ;
     RECT  232.272 2.245 232.296 23.411 ;
     RECT  324.096 23.365 324.12 23.507 ;
     RECT  180.48 23.317 181.8 23.509 ;
     RECT  166.944 23.557 166.968 23.605 ;
     RECT  293.664 21.973 294.312 23.605 ;
     RECT  180.48 23.509 181.896 23.651 ;
     RECT  308.016 23.267 308.136 23.653 ;
     RECT  180.48 23.651 181.8 23.699 ;
     RECT  307.968 23.653 308.136 23.699 ;
     RECT  292.992 23.605 294.312 23.843 ;
     RECT  174.192 22.499 175.512 23.845 ;
     RECT  287.856 21.397 288.912 23.891 ;
     RECT  180.48 23.699 181.608 23.893 ;
     RECT  153.312 23.269 154.344 24.035 ;
     RECT  302.592 23.315 302.856 24.085 ;
     RECT  296.976 23.315 297.288 24.131 ;
     RECT  142.8 23.075 143.112 24.181 ;
     RECT  140.016 19.571 141.336 24.325 ;
     RECT  142.512 24.181 143.112 24.467 ;
     RECT  302.592 24.085 303.24 24.467 ;
     RECT  0.288 24.325 0.312 24.469 ;
     RECT  304.8 23.123 305.112 24.469 ;
     RECT  292.608 24.373 292.632 24.515 ;
     RECT  174.192 23.845 175.608 24.563 ;
     RECT  180.432 23.893 181.608 24.563 ;
     RECT  318.384 21.635 318.408 24.563 ;
     RECT  296.976 24.131 297 24.659 ;
     RECT  168.96 23.411 170.328 24.707 ;
     RECT  295.296 23.701 295.32 24.947 ;
     RECT  0.192 24.469 0.312 25.043 ;
     RECT  177.984 22.835 178.728 25.043 ;
     RECT  315.6 2.151 315.912 25.045 ;
     RECT  0.288 25.043 0.312 25.139 ;
     RECT  290.16 24.469 290.184 25.187 ;
     RECT  304.8 24.469 306.072 25.187 ;
     RECT  173.04 24.469 173.064 25.235 ;
     RECT  156.576 21.971 156.696 25.429 ;
     RECT  314.064 24.421 314.088 25.571 ;
     RECT  302.592 24.467 302.904 25.715 ;
     RECT  180.432 24.563 180.912 25.763 ;
     RECT  166.944 23.605 167.88 25.955 ;
     RECT  172.032 25.189 172.056 25.955 ;
     RECT  292.32 24.613 292.344 26.003 ;
     RECT  315.6 25.045 316.392 26.051 ;
     RECT  169.008 24.707 170.328 26.053 ;
     RECT  307.968 23.699 307.992 26.099 ;
     RECT  164.4 21.683 165.048 26.197 ;
     RECT  169.008 26.053 170.376 26.389 ;
     RECT  142.8 24.467 143.112 26.773 ;
     RECT  164.4 26.197 165.528 26.819 ;
     RECT  178.704 25.043 178.728 26.819 ;
     RECT  167.856 25.955 167.88 27.205 ;
     RECT  169.008 26.389 170.616 27.205 ;
     RECT  150.768 23.027 151.32 27.301 ;
     RECT  180.48 25.763 180.912 27.301 ;
     RECT  142.704 26.773 143.112 27.347 ;
     RECT  167.856 27.205 170.616 27.395 ;
     RECT  158.688 7.619 160.152 27.443 ;
     RECT  174.192 24.563 175.512 27.589 ;
     RECT  164.4 26.819 165.048 27.781 ;
     RECT  153.6 24.035 154.344 27.877 ;
     RECT  180.336 27.301 180.912 27.923 ;
     RECT  150.432 27.301 151.32 27.971 ;
     RECT  171.888 27.301 171.912 28.019 ;
     RECT  139.248 24.325 141.336 28.403 ;
     RECT  150.432 27.971 150.456 28.451 ;
     RECT  164.4 27.781 165.48 29.029 ;
     RECT  174.192 27.589 175.8 29.029 ;
     RECT  174.192 29.029 176.328 29.123 ;
     RECT  172.944 27.349 172.968 29.219 ;
     RECT  144.816 21.203 148.512 29.363 ;
     RECT  153.504 27.877 154.344 29.605 ;
     RECT  158.688 27.443 159.312 29.653 ;
     RECT  139.776 28.403 141.336 29.747 ;
     RECT  174.432 29.123 176.328 29.939 ;
     RECT  179.04 29.029 179.064 30.035 ;
     RECT  180.48 27.923 180.912 30.035 ;
     RECT  145.824 29.363 148.512 30.275 ;
     RECT  158.688 29.653 159.912 30.611 ;
     RECT  164.4 29.029 165.576 30.611 ;
     RECT  139.824 29.747 141.336 30.851 ;
     RECT  174.432 29.939 175.512 30.851 ;
     RECT  156.576 25.429 156.744 31.285 ;
     RECT  156.48 31.285 156.744 31.331 ;
     RECT  156.48 31.331 156.696 32.197 ;
     RECT  174.48 30.851 175.512 32.483 ;
     RECT  156.24 32.197 156.696 32.723 ;
     RECT  153.216 29.605 154.344 33.589 ;
     RECT  178.704 32.437 178.728 33.589 ;
     RECT  175.2 32.483 175.512 33.925 ;
     RECT  153.216 33.589 154.92 33.973 ;
     RECT  156.48 32.723 156.696 33.973 ;
     RECT  153.216 33.973 156.696 34.165 ;
     RECT  178.272 33.589 178.728 34.357 ;
     RECT  180.6 30.035 180.912 34.645 ;
     RECT  152.736 34.165 156.696 34.835 ;
     RECT  173.376 33.973 173.4 34.835 ;
     RECT  161.088 34.597 161.112 35.363 ;
     RECT  167.856 27.395 170.376 35.605 ;
     RECT  175.2 33.925 175.944 35.845 ;
     RECT  153.216 34.835 156.696 35.939 ;
     RECT  153.216 35.939 155.592 36.227 ;
     RECT  164.4 30.611 165.48 36.421 ;
     RECT  167.856 35.605 170.616 36.515 ;
     RECT  149.664 33.781 149.688 36.659 ;
     RECT  174.528 35.845 175.944 36.899 ;
     RECT  153.216 36.227 155.064 37.429 ;
     RECT  152.928 37.429 155.064 37.571 ;
     RECT  164.304 36.421 165.48 37.619 ;
     RECT  152.928 37.571 154.92 37.907 ;
     RECT  156.576 35.939 156.696 38.149 ;
     RECT  167.856 36.515 170.376 38.149 ;
     RECT  156.288 38.149 156.696 38.197 ;
     RECT  157.68 36.853 157.704 38.197 ;
     RECT  140.016 30.851 141.336 38.243 ;
     RECT  140.016 38.243 141.192 38.675 ;
     RECT  153.216 37.907 154.92 38.819 ;
     RECT  156.288 38.197 157.704 38.819 ;
     RECT  144.816 29.363 144.84 39.301 ;
     RECT  164.4 37.619 165.48 39.301 ;
     RECT  140.016 38.675 141.048 39.395 ;
     RECT  178.128 34.357 178.728 39.395 ;
     RECT  156.576 38.819 157.704 39.877 ;
     RECT  158.688 30.611 159.312 39.877 ;
     RECT  180.48 34.645 180.912 39.877 ;
     RECT  150.384 37.861 150.408 40.019 ;
     RECT  144.672 39.301 144.84 40.451 ;
     RECT  140.016 39.395 140.568 40.499 ;
     RECT  140.016 40.499 140.136 40.643 ;
     RECT  175.2 36.899 175.944 41.221 ;
     RECT  167.76 38.149 170.376 41.315 ;
     RECT  171.744 38.581 171.768 41.365 ;
     RECT  171.408 41.365 171.768 41.411 ;
     RECT  156.576 39.877 160.008 41.605 ;
     RECT  144.816 40.451 144.84 41.653 ;
     RECT  167.856 41.315 170.376 41.749 ;
     RECT  145.92 30.275 148.512 41.795 ;
     RECT  144.24 41.653 144.84 41.941 ;
     RECT  145.92 41.795 147.096 41.941 ;
     RECT  164.4 39.301 165.672 42.133 ;
     RECT  174.96 41.221 175.944 42.133 ;
     RECT  156.192 41.605 160.008 42.323 ;
     RECT  171.408 41.411 171.432 42.373 ;
     RECT  156.576 42.323 160.008 42.467 ;
     RECT  177.504 39.589 177.528 42.661 ;
     RECT  151.008 41.701 151.032 42.707 ;
     RECT  142.8 27.347 143.112 42.709 ;
     RECT  163.92 42.133 165.672 43.189 ;
     RECT  163.92 43.189 166.248 43.237 ;
     RECT  167.856 41.749 170.424 43.285 ;
     RECT  171.408 42.373 171.576 43.285 ;
     RECT  174.816 42.133 175.944 43.285 ;
     RECT  176.928 42.661 177.528 43.285 ;
     RECT  144.24 41.941 147.096 43.331 ;
     RECT  141.936 42.709 143.112 43.379 ;
     RECT  167.856 43.285 171.576 43.379 ;
     RECT  174.816 43.285 177.528 43.717 ;
     RECT  163.92 43.237 166.728 43.813 ;
     RECT  167.856 43.379 170.76 43.813 ;
     RECT  174.816 43.717 177.72 43.861 ;
     RECT  178.704 39.395 178.728 43.861 ;
     RECT  144.336 43.331 147.096 43.909 ;
     RECT  148.2 41.795 148.512 43.909 ;
     RECT  153.216 38.819 153.912 44.053 ;
     RECT  140.112 40.643 140.136 44.197 ;
     RECT  153.168 44.053 153.912 44.341 ;
     RECT  156.576 42.467 159.816 44.341 ;
     RECT  142.8 43.379 143.112 44.437 ;
     RECT  149.808 41.749 149.832 44.437 ;
     RECT  161.856 43.765 161.88 44.437 ;
     RECT  163.92 43.813 170.76 44.437 ;
     RECT  174.816 43.861 178.728 44.483 ;
     RECT  180 39.877 180.912 44.483 ;
     RECT  174.816 44.483 177.768 44.725 ;
     RECT  152.784 44.341 153.912 44.869 ;
     RECT  156.576 44.341 160.2 44.917 ;
     RECT  151.632 43.237 151.656 44.965 ;
     RECT  152.688 44.869 153.912 44.965 ;
     RECT  156.432 44.917 160.2 44.965 ;
     RECT  161.856 44.437 170.76 44.965 ;
     RECT  139.92 44.197 140.136 45.013 ;
     RECT  142.8 44.437 143.208 45.013 ;
     RECT  144.336 43.909 148.512 45.013 ;
     RECT  149.808 44.437 150.312 45.013 ;
     RECT  151.632 44.965 153.912 45.013 ;
     RECT  154.896 38.819 154.92 45.061 ;
     RECT  156.432 44.965 170.76 45.061 ;
     RECT  139.536 45.013 140.136 45.301 ;
     RECT  154.896 45.061 170.76 45.301 ;
     RECT  139.536 45.301 140.232 45.349 ;
     RECT  2.4 2.151 2.712 45.369 ;
     RECT  7.8 2.151 8.112 45.369 ;
     RECT  13.2 2.151 13.512 45.369 ;
     RECT  18.6 2.151 18.912 45.369 ;
     RECT  24 2.151 24.312 45.369 ;
     RECT  29.4 2.151 29.712 45.369 ;
     RECT  34.8 2.151 35.112 45.369 ;
     RECT  40.2 2.151 40.512 45.369 ;
     RECT  45.6 2.151 45.912 45.369 ;
     RECT  51 2.151 51.312 45.369 ;
     RECT  56.4 2.151 56.712 45.369 ;
     RECT  61.8 2.151 62.112 45.369 ;
     RECT  67.2 2.151 67.512 45.369 ;
     RECT  72.6 2.151 72.912 45.369 ;
     RECT  78 2.151 78.312 45.369 ;
     RECT  83.4 2.151 83.712 45.369 ;
     RECT  88.8 2.151 89.112 45.369 ;
     RECT  94.2 2.151 94.512 45.369 ;
     RECT  99.6 2.151 99.912 45.369 ;
     RECT  105 2.151 105.312 45.369 ;
     RECT  110.4 2.151 110.712 45.369 ;
     RECT  115.8 2.151 116.112 45.369 ;
     RECT  121.2 2.151 121.512 45.369 ;
     RECT  126.6 2.151 126.912 45.369 ;
     RECT  132 2.151 132.312 45.369 ;
     RECT  137.4 18.947 137.712 45.369 ;
     RECT  180.6 44.483 180.912 45.369 ;
     RECT  186 2.151 186.312 45.369 ;
     RECT  191.4 11.171 191.712 45.369 ;
     RECT  196.8 2.151 197.112 45.369 ;
     RECT  202.2 2.151 202.512 45.369 ;
     RECT  207.6 2.151 207.912 45.369 ;
     RECT  213 2.151 213.312 45.369 ;
     RECT  218.4 2.151 218.712 45.369 ;
     RECT  223.8 2.151 224.112 45.369 ;
     RECT  229.2 2.195 229.512 45.369 ;
     RECT  234.6 2.151 234.912 45.369 ;
     RECT  240 2.151 240.312 45.369 ;
     RECT  245.4 21.155 245.712 45.369 ;
     RECT  250.8 2.151 251.112 45.369 ;
     RECT  256.2 2.151 256.512 45.369 ;
     RECT  261.6 2.151 261.912 45.369 ;
     RECT  267 2.151 267.312 45.369 ;
     RECT  272.4 2.151 272.712 45.369 ;
     RECT  277.8 2.151 278.112 45.369 ;
     RECT  283.2 2.151 283.512 45.369 ;
     RECT  288.6 23.891 288.912 45.369 ;
     RECT  294 23.843 294.312 45.369 ;
     RECT  299.4 23.315 299.712 45.369 ;
     RECT  304.8 25.187 305.112 45.369 ;
     RECT  310.2 23.315 310.512 45.369 ;
     RECT  315.6 26.051 315.912 45.369 ;
     RECT  321 2.151 321.312 45.369 ;
     RECT  2.4 45.369 2.52 45.383 ;
     RECT  7.8 45.369 7.92 45.383 ;
     RECT  13.2 45.369 13.32 45.383 ;
     RECT  18.6 45.369 18.72 45.383 ;
     RECT  24 45.369 24.12 45.383 ;
     RECT  29.4 45.369 29.52 45.383 ;
     RECT  34.8 45.369 34.92 45.383 ;
     RECT  40.2 45.369 40.32 45.383 ;
     RECT  45.6 45.369 45.72 45.383 ;
     RECT  51 45.369 51.12 45.383 ;
     RECT  56.4 45.369 56.52 45.383 ;
     RECT  61.8 45.369 61.92 45.383 ;
     RECT  67.2 45.369 67.32 45.383 ;
     RECT  72.6 45.369 72.72 45.383 ;
     RECT  78 45.369 78.12 45.383 ;
     RECT  83.4 45.369 83.52 45.383 ;
     RECT  88.8 45.369 88.92 45.383 ;
     RECT  94.2 45.369 94.32 45.383 ;
     RECT  99.6 45.369 99.72 45.383 ;
     RECT  105 45.369 105.12 45.383 ;
     RECT  110.4 45.369 110.52 45.383 ;
     RECT  115.8 45.369 115.92 45.383 ;
     RECT  121.2 45.369 121.32 45.383 ;
     RECT  126.6 45.369 126.72 45.383 ;
     RECT  132 45.369 132.12 45.383 ;
     RECT  137.4 45.369 137.52 45.383 ;
     RECT  180.6 45.369 180.72 45.383 ;
     RECT  186 45.369 186.12 45.383 ;
     RECT  191.4 45.369 191.52 45.383 ;
     RECT  196.8 45.369 196.92 45.383 ;
     RECT  202.2 45.369 202.32 45.383 ;
     RECT  207.6 45.369 207.72 45.383 ;
     RECT  213 45.369 213.12 45.383 ;
     RECT  218.4 45.369 218.52 45.383 ;
     RECT  223.8 45.369 223.92 45.383 ;
     RECT  229.2 45.369 229.32 45.383 ;
     RECT  234.6 45.369 234.72 45.383 ;
     RECT  240 45.369 240.12 45.383 ;
     RECT  245.4 45.369 245.52 45.383 ;
     RECT  250.8 45.369 250.92 45.383 ;
     RECT  256.2 45.369 256.32 45.383 ;
     RECT  261.6 45.369 261.72 45.383 ;
     RECT  267 45.369 267.12 45.383 ;
     RECT  272.4 45.369 272.52 45.383 ;
     RECT  277.8 45.369 277.92 45.383 ;
     RECT  283.2 45.369 283.32 45.383 ;
     RECT  288.6 45.369 288.72 45.383 ;
     RECT  294 45.369 294.12 45.383 ;
     RECT  299.4 45.369 299.52 45.383 ;
     RECT  304.8 45.369 304.92 45.383 ;
     RECT  310.2 45.369 310.32 45.383 ;
     RECT  315.6 45.369 315.72 45.383 ;
     RECT  321 45.369 321.12 45.383 ;
     RECT  139.536 45.349 140.424 45.541 ;
     RECT  141.648 45.013 141.672 45.541 ;
     RECT  142.8 45.013 153.912 45.541 ;
     RECT  154.896 45.301 170.856 45.541 ;
     RECT  139.44 45.541 140.424 45.589 ;
     RECT  141.648 45.541 170.856 45.589 ;
     RECT  139.44 45.589 170.856 47.504 ;
     RECT  174.768 44.725 177.768 47.504 ;
  END
END ot_engc_t_win
END LIBRARY
